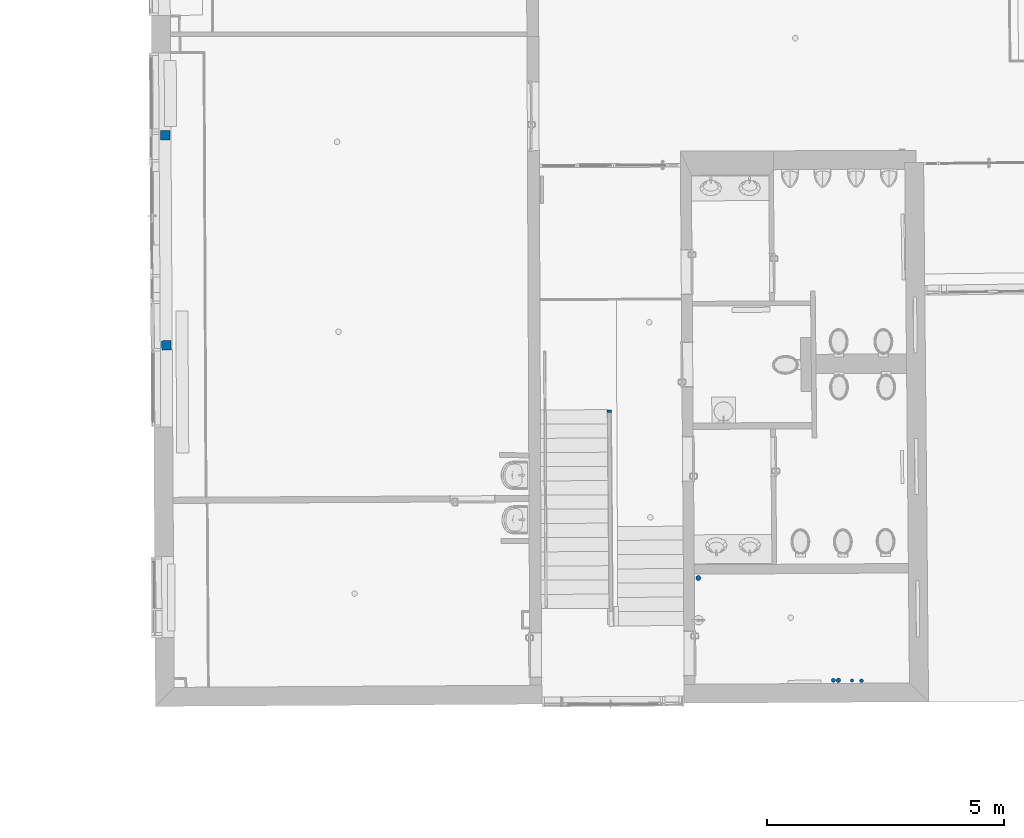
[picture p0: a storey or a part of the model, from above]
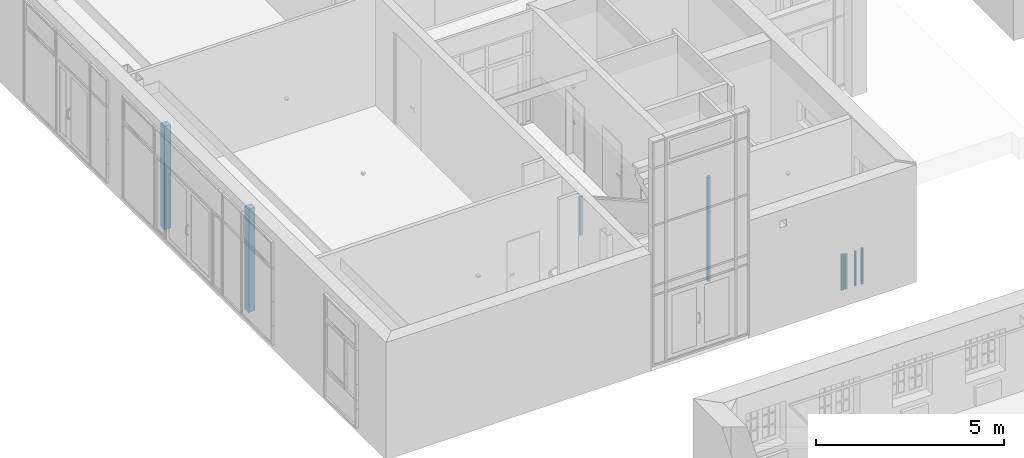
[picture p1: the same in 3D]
Properties of the parts of a building model (IFC2X3), part 1 of 4

# File
Description: ViewDefinition [CoordinationView_V2.0], Option [Elements to export: Filtered elements], Option [Partial Structure Display: Entire Model], Option [IFC Domain: Custom], Option [Structural Function: All Elements], Option [Convert Grid elements: On], Option [Convert IFC Annotations and ARCHICAD 2D elements: Off], Option [Convert 2D symbols of Doors and Windows: Off], Option [Export geometries that Participates in Collision Detection only: Off], Option [Split complex elements: Off], Option [Material Preservation: Explode where necessary], Option [Elements in Solid Element Operations: Extruded/revolved], Option [Elements with junctions: Extruded/revolved without junctions], Option [IFC Model position: Survey Point and Project Origin], Option [Curtain Wall export mode: Single Element], Option [Railing export mode: Single Element], Option [Stair export mode: Single Element], Option [Properties To Export: All properties], Option [Space containment: Off], Option [Bounding Box: Off], Option [Geometry to type objects: Off], Option [Element Properties: Off], Option [Building Material Properties: Off], Option [Element Parameters: Off], Option [Component Parameters: Off], Option [IFC Base Quantities: Off], Option [Door Window Parameters: Off], Option [IFC Space boundaries: Off], Option [ARCHICAD Zone Categories as IFC Space classification data: Off], Option [Element Classifications: On]
File name: C:\Users\BEB-Olaf\BEB\BEB - Dokumente\Mitarbeiter Cloud\1. Projekte\23-643_EichwaldeHumboldGym_Bahnhofstr_80\231116 Eichwalde, Bahnhofstr. 80\3D\231116_Eichwalde_Humbold_Gymnasium_Bahnhofstr_80.ifc
Time: 2023-11-17T09:39:34
Author: Architect
Organization: Jantzen 3D-Vermessung & 3D-Modellierung
Written by: The EXPRESS Data Manager Version 5.02.0100.09 : 26 Sep 2013
Made in: IFC file generated by GRAPHISOFT ARCHICAD 25.0.0 GER FULL Windows version (IFC add-on version: 6000 GER FULL).
Authorization: The authorising person

# IfcSite, Gelände
RefLatitude: 52, 31, 0, 0; RefLongitude: 13, 24, 0, 0; RefElevation: 0 m

# IfcBuildingStorey (6)
In: Gebäude
Name | Elevation (m)
SPITZBODEN | 13.9
DACHGESCHOSS | 10.9
2.OBERGESCHOSS | 7.9
1.OBERGESCHOSS | 3.7
ERDGESCHOSS | 0
KELLERGESCHOSS | -3

# IfcSpace: Bildung, Unterricht und Kultur
In: 1.OBERGESCHOSS
LongName: Lehrerzimmer 215; InteriorOrExteriorSpace: INTERNAL
Pset_SpaceCommon - Category: Bildung, Unterricht und Kultur
AC_Pset_RenovationAndPhasing - Renovation Status: Existing

# IfcSpace: Sonstige Nutzungen (9)
In: 1.OBERGESCHOSS
InteriorOrExteriorSpace: INTERNAL
Pset_SpaceCommon - Category: Sonstige Nutzungen
AC_Pset_RenovationAndPhasing - Renovation Status: Existing
Name | LongName
3 x  | Flur
 | Toiletten Herren 217
001 | Toiletten Herren 216
001 | Toiletten Damen 219
002 | Toiletten Herren 216
002 | Toiletten Damen 219
003 | Toiletten Damen 219

# IfcSpace: Wohnen und Aufenthalt (132)
InteriorOrExteriorSpace: INTERNAL
Pset_SpaceCommon - Category: Wohnen und Aufenthalt
AC_Pset_RenovationAndPhasing - Renovation Status: Existing
Name | In | LongName
 | 2.OBERGESCHOSS | Klassenraum Mathematik 308
 | 2.OBERGESCHOSS | 315
 | 2.OBERGESCHOSS | 301
 | 2.OBERGESCHOSS | Informatik 310
 | 2.OBERGESCHOSS | Behindertentoilette 311
 | 2.OBERGESCHOSS | Klassenraum Mathematik 306
 | 2.OBERGESCHOSS | Mathematik 304
 | 2.OBERGESCHOSS | Abstellraum 305
 | 2.OBERGESCHOSS | Klassenraum Mathematik 303
 | 2.OBERGESCHOSS | Vorbereitung/Sammlung Mathematik/Informatik 302
 | 2.OBERGESCHOSS | Informatik 309
 | 2.OBERGESCHOSS | Kammer 314
 | 2.OBERGESCHOSS | Aula 307
001 | 2.OBERGESCHOSS | Toilette Damen 313
001 | 2.OBERGESCHOSS | Flur
001 | 2.OBERGESCHOSS | Toilette Herren 312
002 | 2.OBERGESCHOSS | Toilette Herren 312
002 | 2.OBERGESCHOSS | Flur
002 | 2.OBERGESCHOSS | Toilette Damen 313
003 | 2.OBERGESCHOSS | Flur
004 | 2.OBERGESCHOSS | Flur
 | 1.OBERGESCHOSS | Beratungsraum 214
 | 1.OBERGESCHOSS | Sekretariat 205
 | 1.OBERGESCHOSS | Klassenraum 220
 | 1.OBERGESCHOSS | 213/214
 | 1.OBERGESCHOSS | Keine Bezeichnung
 | 1.OBERGESCHOSS | Klassenraum 202
 | 1.OBERGESCHOSS | Sanitätsraum 213
 | 1.OBERGESCHOSS | Stellv. Schulleiter 204
 | 1.OBERGESCHOSS | Klassenraum 201
 | 1.OBERGESCHOSS | Schulleiter 206
 | 1.OBERGESCHOSS | Klassenraum 203
 | 1.OBERGESCHOSS | Vorbereitung Bio 211
001 | 1.OBERGESCHOSS | Flur
002 | 1.OBERGESCHOSS | Flur
003 | 1.OBERGESCHOSS | Flur
Chemie | 1.OBERGESCHOSS | Klassenraum 208
Chemie | 1.OBERGESCHOSS | Vorbereitung 209
Chemie | 1.OBERGESCHOSS | Klassenraum 210
Chemie | 1.OBERGESCHOSS | Klassenraum 207
 | ERDGESCHOSS | N 2.6
 | ERDGESCHOSS | Kunst Vorbereitung N 2.2
 | ERDGESCHOSS | Klassenraum 102
 | ERDGESCHOSS | Klassenraum 105
 | ERDGESCHOSS | Klassenraum 101
 | ERDGESCHOSS | Treppenhaus
 | ERDGESCHOSS | Kunst N 2.3
 | ERDGESCHOSS | Klassenraum 104
 | ERDGESCHOSS | Geschichte N 2.4
 | ERDGESCHOSS | Flur
 | ERDGESCHOSS | Vorbereitung Physik 107
 | ERDGESCHOSS | Vorbereitungsraum Erdkunde 110
 | ERDGESCHOSS | Vorbereitungsraum Erdkunde 111
 | ERDGESCHOSS | Toiletten Herren 114
 | ERDGESCHOSS | Physik 106
 | ERDGESCHOSS | Klassenraum 117
 | ERDGESCHOSS | Toiletten Damen 115
 | ERDGESCHOSS | Kunst N 2.1
 | ERDGESCHOSS | N 2.5
 | ERDGESCHOSS | Schulsozialarbeit 109
 | ERDGESCHOSS | Physik 108
 | ERDGESCHOSS | Klassenraum 103
001 | ERDGESCHOSS | Toiletten Herren 113
001 | ERDGESCHOSS | Toiletten Damen 116
001 | ERDGESCHOSS | Vorbereitungsraum 112
001 | ERDGESCHOSS | Flur
002 | ERDGESCHOSS | Flur
002 | ERDGESCHOSS | Treppenhaus
002 | ERDGESCHOSS | Toiletten Damen 116
002 | ERDGESCHOSS | Vorbereitungsraum 112
002 | ERDGESCHOSS | Toiletten Herren 113
003 | ERDGESCHOSS | Flur
003 | ERDGESCHOSS | Toiletten Damen 116
004 | ERDGESCHOSS | Flur
005 | ERDGESCHOSS | Flur
006 | ERDGESCHOSS | Flur
 | KELLERGESCHOSS | N 1.6
2 x  | KELLERGESCHOSS | Treppenhaus
3 x  | KELLERGESCHOSS
 | KELLERGESCHOSS | Hausanschlussraum 003
 | KELLERGESCHOSS | Sammlungsraum 002
 | KELLERGESCHOSS | Kammer 022
2 x  | KELLERGESCHOSS | Flur
 | KELLERGESCHOSS | Klassenraum 004
 | KELLERGESCHOSS | Hausmeister Herr Hoppe 014
 | KELLERGESCHOSS | Sprachenvorbereitung 005
 | KELLERGESCHOSS | Heizung 016
 | KELLERGESCHOSS | N 1.3
 | KELLERGESCHOSS | Klassenraum 007
 | KELLERGESCHOSS | Buchraum 006
 | KELLERGESCHOSS | Klassenraum 009
 | KELLERGESCHOSS | Klassenraum 010
 | KELLERGESCHOSS | Klassenraum 011
 | KELLERGESCHOSS | 09
 | KELLERGESCHOSS | Klassenraum 008
 | KELLERGESCHOSS | Toilette Damen 019
 | KELLERGESCHOSS | 05
 | KELLERGESCHOSS | Bad Hausmeister 014
 | KELLERGESCHOSS | Toilette Herren 018
 | KELLERGESCHOSS | 02
 | KELLERGESCHOSS | 04
 | KELLERGESCHOSS | 03
 | KELLERGESCHOSS | 07
 | KELLERGESCHOSS | 06
 | KELLERGESCHOSS | 08
 | KELLERGESCHOSS | 01
 | KELLERGESCHOSS | Klassenraum 001
 | KELLERGESCHOSS | N 1.7
 | KELLERGESCHOSS | N 1.8
 | KELLERGESCHOSS | N 1.1
 | KELLERGESCHOSS | N 1.2
001 | KELLERGESCHOSS | 021
001 | KELLERGESCHOSS | Toilette Damen 020
001 | KELLERGESCHOSS | Toilette Herren 017
001 | KELLERGESCHOSS | N 1.5
001 | KELLERGESCHOSS | Flur
001 | KELLERGESCHOSS | Windfang
002 | KELLERGESCHOSS | Toilette Damen 020
002 | KELLERGESCHOSS | 021
3 x 002 | KELLERGESCHOSS | Flur
002 | KELLERGESCHOSS | Heizung 016
2 x 002 | KELLERGESCHOSS | N 1.5
002 | KELLERGESCHOSS | Toilette Herren 017
002 | KELLERGESCHOSS | N 1.7
003 | KELLERGESCHOSS | Toilette Damen 020

# IfcBeam: 01_ALLGEMEIN - BAUTEIL 40 x 40 (6)
Type - PredefinedType: LINTEL
Classification: 351 Deckenkonstruktionen (Classification DIN 267:2018-12); Sturz (ARCHICAD Klassifizierung); Material: 01_ALLGEMEIN - BAUTEIL
Pset_BeamCommon - LoadBearing: yes; IsExternal: no; Reference: 01_ALLGEMEIN - BAUTEIL 40 x 40
AC_Pset_RenovationAndPhasing - Renovation Status: Existing
Name | In | Slope (deg)
Unterzug-007 | ERDGESCHOSS | -0.144917
Unterzug-008 | ERDGESCHOSS | -0.259196
Unterzug-009 | ERDGESCHOSS | 29.8521
Unterzug-010 | ERDGESCHOSS | -0.082967
Unterzug-006 | KELLERGESCHOSS | -0.317002
Unterzug-007 | KELLERGESCHOSS | 29.8123

# IfcBeam: 01_ALLGEMEIN - BAUTEIL 422 x 500 (15)
Type - PredefinedType: LINTEL
Classification: 351 Deckenkonstruktionen (Classification DIN 267:2018-12); Sturz (ARCHICAD Klassifizierung); Material: 01_ALLGEMEIN - BAUTEIL
Pset_BeamCommon - LoadBearing: yes; IsExternal: no; Reference: 01_ALLGEMEIN - BAUTEIL 422 x 500
AC_Pset_RenovationAndPhasing - Renovation Status: Existing
Name | In | Slope (deg)
Unterzug-023 | SPITZBODEN | 0.172647
Unterzug-023 | DACHGESCHOSS | -5.87816
Unterzug-024 | DACHGESCHOSS | 3.50653
Unterzug-024 | DACHGESCHOSS | 2.12091
Unterzug-025 | DACHGESCHOSS | -0.357447
Unterzug-025 | DACHGESCHOSS | -0.617514
Unterzug-026 | DACHGESCHOSS | 2.24426
Unterzug-026 | DACHGESCHOSS | 2.85977
Unterzug-027 | DACHGESCHOSS | -0.105432
Unterzug-027 | DACHGESCHOSS | -0.701471
Unterzug-028 | DACHGESCHOSS | 0.353788
Unterzug-029 | DACHGESCHOSS | 0.289334
Unterzug-030 | DACHGESCHOSS | -3.50915
Unterzug-031 | DACHGESCHOSS | 1.33837
Unterzug-032 | DACHGESCHOSS | -1.38192

# IfcBeam: 01_ALLGEMEIN - BAUTEIL 500 x 500, Unterzug-022
In: SPITZBODEN
Type - PredefinedType: LINTEL
Classification: 351 Deckenkonstruktionen (Classification DIN 267:2018-12); Sturz (ARCHICAD Klassifizierung); Material: 01_ALLGEMEIN - BAUTEIL
Pset_BeamCommon - Slope: -1.53467 deg; LoadBearing: yes; IsExternal: no; Reference: 01_ALLGEMEIN - BAUTEIL 500 x 500
AC_Pset_RenovationAndPhasing - Renovation Status: Existing

# IfcBeam: 01_ALLGEMEIN - BAUTEIL 90 x 50, Unterzug-005
In: ERDGESCHOSS
Type - PredefinedType: LINTEL
Classification: 351 Deckenkonstruktionen (Classification DIN 267:2018-12); Sturz (ARCHICAD Klassifizierung); Material: 01_ALLGEMEIN - BAUTEIL
Pset_BeamCommon - Slope: 0 deg; LoadBearing: yes; IsExternal: no; Reference: 01_ALLGEMEIN - BAUTEIL 90 x 50
AC_Pset_RenovationAndPhasing - Renovation Status: Existing

# IfcBeam: 05_ALLGEMEIN - TRAGENDE BAUTEILE 100 x 100, Unterzug-027
In: SPITZBODEN
Type - PredefinedType: LINTEL
Classification: 351 Deckenkonstruktionen (Classification DIN 267:2018-12); Sturz (ARCHICAD Klassifizierung); Material: 05_ALLGEMEIN - TRAGENDE BAUTEILE
Pset_BeamCommon - Slope: 0.170074 deg; LoadBearing: yes; IsExternal: no; Reference: 05_ALLGEMEIN - TRAGENDE BAUTEILE 100 x 100
AC_Pset_RenovationAndPhasing - Renovation Status: Existing

# IfcBeam: 05_ALLGEMEIN - TRAGENDE BAUTEILE 100 x 120 (11)
In: ERDGESCHOSS
Type - PredefinedType: LINTEL
Classification: 351 Deckenkonstruktionen (Classification DIN 267:2018-12); Sturz (ARCHICAD Klassifizierung); Material: 05_ALLGEMEIN - TRAGENDE BAUTEILE
Pset_BeamCommon - LoadBearing: yes; IsExternal: no; Reference: 05_ALLGEMEIN - TRAGENDE BAUTEILE 100 x 120
AC_Pset_RenovationAndPhasing - Renovation Status: Existing
Name | Slope (deg)
Unterzug-063 | -0.0255391
Unterzug-063 | -0.409344
5 x Unterzug-064 | 0.19738
Unterzug-065 | 0.271111
Unterzug-066 | -0.169375
Unterzug-067 | 0.141631
Unterzug-068 | -0.118367

# IfcBeam: 05_ALLGEMEIN - TRAGENDE BAUTEILE 102 x 390, Unterzug-020
In: ERDGESCHOSS
Type - PredefinedType: LINTEL
Classification: 351 Deckenkonstruktionen (Classification DIN 267:2018-12); Sturz (ARCHICAD Klassifizierung); Material: 05_ALLGEMEIN - TRAGENDE BAUTEILE
Pset_BeamCommon - Slope: -26.8116 deg; LoadBearing: yes; IsExternal: no; Reference: 05_ALLGEMEIN - TRAGENDE BAUTEILE 102 x 390
AC_Pset_RenovationAndPhasing - Renovation Status: Existing

# IfcBeam: 05_ALLGEMEIN - TRAGENDE BAUTEILE 115 x 120 (2)
In: KELLERGESCHOSS
Type - PredefinedType: LINTEL
Classification: 351 Deckenkonstruktionen (Classification DIN 267:2018-12); Sturz (ARCHICAD Klassifizierung); Material: 05_ALLGEMEIN - TRAGENDE BAUTEILE
Pset_BeamCommon - LoadBearing: yes; IsExternal: no; Reference: 05_ALLGEMEIN - TRAGENDE BAUTEILE 115 x 120
AC_Pset_RenovationAndPhasing - Renovation Status: Existing
Name | Slope (deg)
Unterzug-026 | -0.242095
Unterzug-027 | 0.171309

# IfcBeam: 05_ALLGEMEIN - TRAGENDE BAUTEILE 120 x 140 (8)
In: 2.OBERGESCHOSS
Type - PredefinedType: LINTEL
Classification: 351 Deckenkonstruktionen (Classification DIN 267:2018-12); Sturz (ARCHICAD Klassifizierung); Material: 05_ALLGEMEIN - TRAGENDE BAUTEILE
Pset_BeamCommon - LoadBearing: yes; IsExternal: no; Reference: 05_ALLGEMEIN - TRAGENDE BAUTEILE 120 x 140
AC_Pset_RenovationAndPhasing - Renovation Status: Existing
Name | Slope (deg)
Unterzug-090 | -44.3282
Unterzug-091 | -44.0647
Unterzug-091 | 44.0561
Unterzug-092 | -44.0622
Unterzug-093 | -45.7999
Unterzug-093 | 45.2487
Unterzug-094 | 44.4827
Unterzug-094 | -43.8498

# IfcBeam: 05_ALLGEMEIN - TRAGENDE BAUTEILE 122 x 160 (2)
Type - PredefinedType: LINTEL
Classification: 351 Deckenkonstruktionen (Classification DIN 267:2018-12); Sturz (ARCHICAD Klassifizierung); Material: 05_ALLGEMEIN - TRAGENDE BAUTEILE
Pset_BeamCommon - LoadBearing: yes; IsExternal: no; Reference: 05_ALLGEMEIN - TRAGENDE BAUTEILE 122 x 160
AC_Pset_RenovationAndPhasing - Renovation Status: Existing
Name | In | Slope (deg)
Unterzug-037 | SPITZBODEN | -0.151633
Unterzug-037 | DACHGESCHOSS | -0.0277064

# IfcBeam: 05_ALLGEMEIN - TRAGENDE BAUTEILE 130 x 160 (6)
In: DACHGESCHOSS
Type - PredefinedType: LINTEL
Classification: 351 Deckenkonstruktionen (Classification DIN 267:2018-12); Sturz (ARCHICAD Klassifizierung); Material: 05_ALLGEMEIN - TRAGENDE BAUTEILE
Pset_BeamCommon - LoadBearing: yes; IsExternal: no; Reference: 05_ALLGEMEIN - TRAGENDE BAUTEILE 130 x 160
AC_Pset_RenovationAndPhasing - Renovation Status: Existing
Name | Slope (deg)
Unterzug-064 | 0.103733
Unterzug-065 | 0.328985
Unterzug-066 | 1.14341
Unterzug-071 | 0.0835682
Unterzug-072 | 0.511564
Unterzug-073 | 1.18713

# IfcBeam: 05_ALLGEMEIN - TRAGENDE BAUTEILE 130 x 170 (41)
Type - PredefinedType: LINTEL
Classification: 351 Deckenkonstruktionen (Classification DIN 267:2018-12); Sturz (ARCHICAD Klassifizierung); Material: 05_ALLGEMEIN - TRAGENDE BAUTEILE
Pset_BeamCommon - LoadBearing: yes; IsExternal: no; Reference: 05_ALLGEMEIN - TRAGENDE BAUTEILE 130 x 170
AC_Pset_RenovationAndPhasing - Renovation Status: Existing
Name | In | Slope (deg)
Unterzug-056 | SPITZBODEN | 80.6286
Unterzug-057 | SPITZBODEN | -80.746
Unterzug-061 | SPITZBODEN | -78.8242
Unterzug-079 | SPITZBODEN | 80.5319
Unterzug-080 | SPITZBODEN | 0
Unterzug-081 | SPITZBODEN | 0
Unterzug-082 | SPITZBODEN | 0
Unterzug-083 | SPITZBODEN | 0
Unterzug-084 | SPITZBODEN | 24.3867
Unterzug-085 | SPITZBODEN | -23.3479
Unterzug-050 | DACHGESCHOSS | 50.7288
Unterzug-051 | DACHGESCHOSS | -50.4321
Unterzug-052 | DACHGESCHOSS | -50.3705
Unterzug-053 | DACHGESCHOSS | -49.253
Unterzug-054 | DACHGESCHOSS | 0.028561
Unterzug-055 | DACHGESCHOSS | 41.2954
Unterzug-057 | DACHGESCHOSS | -49.5741
Unterzug-058 | DACHGESCHOSS | -51.0679
Unterzug-059 | DACHGESCHOSS | -50.3902
Unterzug-060 | DACHGESCHOSS | 50.2729
Unterzug-062 | DACHGESCHOSS | -50.8759
Unterzug-063 | DACHGESCHOSS | -49.8978
Unterzug-064 | DACHGESCHOSS | -50.1063
Unterzug-065 | DACHGESCHOSS | -40.8446
Unterzug-066 | DACHGESCHOSS | 50.4026
Unterzug-068 | DACHGESCHOSS | 41.0425
Unterzug-069 | DACHGESCHOSS | 39.3935
Unterzug-070 | DACHGESCHOSS | 53.9665
2 x Unterzug-071 | DACHGESCHOSS | -40.8246
Unterzug-072 | DACHGESCHOSS | -51.0445
Unterzug-073 | DACHGESCHOSS | 50.9107
Unterzug-074 | DACHGESCHOSS | 42.2773
Unterzug-075 | DACHGESCHOSS | -44.0211
Unterzug-076 | DACHGESCHOSS | 0.0615184
Unterzug-077 | DACHGESCHOSS | 0.58419
Unterzug-078 | DACHGESCHOSS | 0.0397564
Unterzug-083 | DACHGESCHOSS | 0.513884
Unterzug-084 | DACHGESCHOSS | 44.6501
Unterzug-090 | DACHGESCHOSS | 45.4397
Unterzug-091 | DACHGESCHOSS | 44.0047

# IfcBeam: 05_ALLGEMEIN - TRAGENDE BAUTEILE 145 x 69, Unterzug-021
In: KELLERGESCHOSS
Type - PredefinedType: LINTEL
Classification: 351 Deckenkonstruktionen (Classification DIN 267:2018-12); Sturz (ARCHICAD Klassifizierung); Material: 05_ALLGEMEIN - TRAGENDE BAUTEILE
Pset_BeamCommon - Slope: 26.9878 deg; LoadBearing: yes; IsExternal: no; Reference: 05_ALLGEMEIN - TRAGENDE BAUTEILE 145 x 69
AC_Pset_RenovationAndPhasing - Renovation Status: Existing

# IfcBeam: 05_ALLGEMEIN - TRAGENDE BAUTEILE 145 x 74, Unterzug-021
In: ERDGESCHOSS
Type - PredefinedType: LINTEL
Classification: 351 Deckenkonstruktionen (Classification DIN 267:2018-12); Sturz (ARCHICAD Klassifizierung); Material: 05_ALLGEMEIN - TRAGENDE BAUTEILE
Pset_BeamCommon - Slope: 26.9878 deg; LoadBearing: yes; IsExternal: no; Reference: 05_ALLGEMEIN - TRAGENDE BAUTEILE 145 x 74
AC_Pset_RenovationAndPhasing - Renovation Status: Existing

# IfcBeam: 05_ALLGEMEIN - TRAGENDE BAUTEILE 145 x 80 (6)
Type - PredefinedType: LINTEL
Classification: 351 Deckenkonstruktionen (Classification DIN 267:2018-12); Sturz (ARCHICAD Klassifizierung); Material: 05_ALLGEMEIN - TRAGENDE BAUTEILE
Pset_BeamCommon - LoadBearing: yes; IsExternal: no; Reference: 05_ALLGEMEIN - TRAGENDE BAUTEILE 145 x 80
AC_Pset_RenovationAndPhasing - Renovation Status: Existing
Name | In | Slope (deg)
Unterzug-021 | 1.OBERGESCHOSS | -0.449914
Unterzug-022 | 1.OBERGESCHOSS | 26.5984
Unterzug-023 | 1.OBERGESCHOSS | 0
Unterzug-024 | 1.OBERGESCHOSS | 26.8204
Unterzug-020 | ERDGESCHOSS | 0
Unterzug-020 | ERDGESCHOSS | -26.5975

# IfcBeam: 05_ALLGEMEIN - TRAGENDE BAUTEILE 145 x 89, Unterzug-022
In: KELLERGESCHOSS
Type - PredefinedType: LINTEL
Classification: 351 Deckenkonstruktionen (Classification DIN 267:2018-12); Sturz (ARCHICAD Klassifizierung); Material: 05_ALLGEMEIN - TRAGENDE BAUTEILE
Pset_BeamCommon - Slope: -0.416528 deg; LoadBearing: yes; IsExternal: no; Reference: 05_ALLGEMEIN - TRAGENDE BAUTEILE 145 x 89
AC_Pset_RenovationAndPhasing - Renovation Status: Existing

# IfcBeam: 05_ALLGEMEIN - TRAGENDE BAUTEILE 150 x 105 (2)
In: KELLERGESCHOSS
Type - PredefinedType: LINTEL
Classification: 351 Deckenkonstruktionen (Classification DIN 267:2018-12); Sturz (ARCHICAD Klassifizierung); Material: 05_ALLGEMEIN - TRAGENDE BAUTEILE
Pset_BeamCommon - LoadBearing: yes; IsExternal: no; Reference: 05_ALLGEMEIN - TRAGENDE BAUTEILE 150 x 105
AC_Pset_RenovationAndPhasing - Renovation Status: Existing
Name | Slope (deg)
Unterzug-024 | -0.175032
Unterzug-025 | 0.579091

# IfcBeam: 05_ALLGEMEIN - TRAGENDE BAUTEILE 153 x 89 (2)
Type - PredefinedType: LINTEL
Classification: 351 Deckenkonstruktionen (Classification DIN 267:2018-12); Sturz (ARCHICAD Klassifizierung); Material: 05_ALLGEMEIN - TRAGENDE BAUTEILE
Pset_BeamCommon - LoadBearing: yes; IsExternal: no; Reference: 05_ALLGEMEIN - TRAGENDE BAUTEILE 153 x 89
AC_Pset_RenovationAndPhasing - Renovation Status: Existing
Name | In | Slope (deg)
Unterzug-024 | 2.OBERGESCHOSS | -0.317178
Unterzug-023 | KELLERGESCHOSS | -0.0473949

# IfcBeam: 05_ALLGEMEIN - TRAGENDE BAUTEILE 154 x 90, Unterzug-021
In: ERDGESCHOSS
Type - PredefinedType: LINTEL
Classification: 351 Deckenkonstruktionen (Classification DIN 267:2018-12); Sturz (ARCHICAD Klassifizierung); Material: 05_ALLGEMEIN - TRAGENDE BAUTEILE
Pset_BeamCommon - Slope: 0 deg; LoadBearing: yes; IsExternal: no; Reference: 05_ALLGEMEIN - TRAGENDE BAUTEILE 154 x 90
AC_Pset_RenovationAndPhasing - Renovation Status: Existing

# IfcBeam: 05_ALLGEMEIN - TRAGENDE BAUTEILE 160 x 168, Unterzug-027
In: SPITZBODEN
Type - PredefinedType: LINTEL
Classification: 351 Deckenkonstruktionen (Classification DIN 267:2018-12); Sturz (ARCHICAD Klassifizierung); Material: 05_ALLGEMEIN - TRAGENDE BAUTEILE
Pset_BeamCommon - Slope: 0.123751 deg; LoadBearing: yes; IsExternal: no; Reference: 05_ALLGEMEIN - TRAGENDE BAUTEILE 160 x 168
AC_Pset_RenovationAndPhasing - Renovation Status: Existing

# IfcBeam: 05_ALLGEMEIN - TRAGENDE BAUTEILE 160 x 90, Unterzug-026
In: SPITZBODEN
Type - PredefinedType: LINTEL
Classification: 351 Deckenkonstruktionen (Classification DIN 267:2018-12); Sturz (ARCHICAD Klassifizierung); Material: 05_ALLGEMEIN - TRAGENDE BAUTEILE
Pset_BeamCommon - Slope: 0.00334619 deg; LoadBearing: yes; IsExternal: no; Reference: 05_ALLGEMEIN - TRAGENDE BAUTEILE 160 x 90
AC_Pset_RenovationAndPhasing - Renovation Status: Existing

# IfcBeam: 05_ALLGEMEIN - TRAGENDE BAUTEILE 170 x 157 (2)
In: 1.OBERGESCHOSS
Type - PredefinedType: LINTEL
Classification: 351 Deckenkonstruktionen (Classification DIN 267:2018-12); Sturz (ARCHICAD Klassifizierung); Material: 05_ALLGEMEIN - TRAGENDE BAUTEILE
Pset_BeamCommon - LoadBearing: yes; IsExternal: no; Reference: 05_ALLGEMEIN - TRAGENDE BAUTEILE 170 x 157
AC_Pset_RenovationAndPhasing - Renovation Status: Existing
Name | Slope (deg)
Unterzug-020 | -26.5794
Unterzug-020 | 26.8213

# IfcBeam: 05_ALLGEMEIN - TRAGENDE BAUTEILE 170 x 390 (2)
In: ERDGESCHOSS
Type - PredefinedType: LINTEL
Classification: 351 Deckenkonstruktionen (Classification DIN 267:2018-12); Sturz (ARCHICAD Klassifizierung); Material: 05_ALLGEMEIN - TRAGENDE BAUTEILE
Pset_BeamCommon - LoadBearing: yes; IsExternal: no; Reference: 05_ALLGEMEIN - TRAGENDE BAUTEILE 170 x 390
AC_Pset_RenovationAndPhasing - Renovation Status: Existing
Name | Slope (deg)
Unterzug-020 | 26.5158
Unterzug-020 | -26.7289

# IfcBeam: 05_ALLGEMEIN - TRAGENDE BAUTEILE 186 x 160, Unterzug-030
In: DACHGESCHOSS
Type - PredefinedType: LINTEL
Classification: 351 Deckenkonstruktionen (Classification DIN 267:2018-12); Sturz (ARCHICAD Klassifizierung); Material: 05_ALLGEMEIN - TRAGENDE BAUTEILE
Pset_BeamCommon - Slope: 0 deg; LoadBearing: yes; IsExternal: no; Reference: 05_ALLGEMEIN - TRAGENDE BAUTEILE 186 x 160
AC_Pset_RenovationAndPhasing - Renovation Status: Existing

# IfcBeam: 05_ALLGEMEIN - TRAGENDE BAUTEILE 190 x 190, Unterzug-090
In: 2.OBERGESCHOSS
Type - PredefinedType: LINTEL
Classification: 351 Deckenkonstruktionen (Classification DIN 267:2018-12); Sturz (ARCHICAD Klassifizierung); Material: 05_ALLGEMEIN - TRAGENDE BAUTEILE
Pset_BeamCommon - Slope: 44.6414 deg; LoadBearing: yes; IsExternal: no; Reference: 05_ALLGEMEIN - TRAGENDE BAUTEILE 190 x 190
AC_Pset_RenovationAndPhasing - Renovation Status: Existing

# IfcBeam: 05_ALLGEMEIN - TRAGENDE BAUTEILE 190 x 275, Unterzug-089
In: 2.OBERGESCHOSS
Type - PredefinedType: LINTEL
Classification: 351 Deckenkonstruktionen (Classification DIN 267:2018-12); Sturz (ARCHICAD Klassifizierung); Material: 05_ALLGEMEIN - TRAGENDE BAUTEILE
Pset_BeamCommon - Slope: 40.7529 deg; LoadBearing: yes; IsExternal: no; Reference: 05_ALLGEMEIN - TRAGENDE BAUTEILE 190 x 275
AC_Pset_RenovationAndPhasing - Renovation Status: Existing

# IfcBeam: 05_ALLGEMEIN - TRAGENDE BAUTEILE 241 x 232, Unterzug-022
In: 1.OBERGESCHOSS
Type - PredefinedType: LINTEL
Classification: 351 Deckenkonstruktionen (Classification DIN 267:2018-12); Sturz (ARCHICAD Klassifizierung); Material: 05_ALLGEMEIN - TRAGENDE BAUTEILE
Pset_BeamCommon - Slope: 0 deg; LoadBearing: yes; IsExternal: no; Reference: 05_ALLGEMEIN - TRAGENDE BAUTEILE 241 x 232
AC_Pset_RenovationAndPhasing - Renovation Status: Existing

# IfcBeam: 05_ALLGEMEIN - TRAGENDE BAUTEILE 241 x 300, Unterzug-022
In: ERDGESCHOSS
Type - PredefinedType: LINTEL
Classification: 351 Deckenkonstruktionen (Classification DIN 267:2018-12); Sturz (ARCHICAD Klassifizierung); Material: 05_ALLGEMEIN - TRAGENDE BAUTEILE
Pset_BeamCommon - Slope: 0 deg; LoadBearing: yes; IsExternal: no; Reference: 05_ALLGEMEIN - TRAGENDE BAUTEILE 241 x 300
AC_Pset_RenovationAndPhasing - Renovation Status: Existing

# IfcBeam: 05_ALLGEMEIN - TRAGENDE BAUTEILE 241 x 310, Unterzug-023
In: KELLERGESCHOSS
Type - PredefinedType: LINTEL
Classification: 351 Deckenkonstruktionen (Classification DIN 267:2018-12); Sturz (ARCHICAD Klassifizierung); Material: 05_ALLGEMEIN - TRAGENDE BAUTEILE
Pset_BeamCommon - Slope: 0 deg; LoadBearing: yes; IsExternal: no; Reference: 05_ALLGEMEIN - TRAGENDE BAUTEILE 241 x 310
AC_Pset_RenovationAndPhasing - Renovation Status: Existing

# IfcBeam: 05_ALLGEMEIN - TRAGENDE BAUTEILE 245 x 298, Unterzug-021
In: KELLERGESCHOSS
Type - PredefinedType: LINTEL
Classification: 351 Deckenkonstruktionen (Classification DIN 267:2018-12); Sturz (ARCHICAD Klassifizierung); Material: 05_ALLGEMEIN - TRAGENDE BAUTEILE
Pset_BeamCommon - Slope: 0 deg; LoadBearing: yes; IsExternal: no; Reference: 05_ALLGEMEIN - TRAGENDE BAUTEILE 245 x 298
AC_Pset_RenovationAndPhasing - Renovation Status: Existing

# IfcBeam: 05_ALLGEMEIN - TRAGENDE BAUTEILE 270 x 190, Unterzug-089
In: 2.OBERGESCHOSS
Type - PredefinedType: LINTEL
Classification: 351 Deckenkonstruktionen (Classification DIN 267:2018-12); Sturz (ARCHICAD Klassifizierung); Material: 05_ALLGEMEIN - TRAGENDE BAUTEILE
Pset_BeamCommon - Slope: -43.8101 deg; LoadBearing: yes; IsExternal: no; Reference: 05_ALLGEMEIN - TRAGENDE BAUTEILE 270 x 190
AC_Pset_RenovationAndPhasing - Renovation Status: Existing

# IfcBeam: 05_ALLGEMEIN - TRAGENDE BAUTEILE 270 x 367, Unterzug-091
In: 2.OBERGESCHOSS
Type - PredefinedType: LINTEL
Classification: 351 Deckenkonstruktionen (Classification DIN 267:2018-12); Sturz (ARCHICAD Klassifizierung); Material: 05_ALLGEMEIN - TRAGENDE BAUTEILE
Pset_BeamCommon - Slope: 43.7801 deg; LoadBearing: yes; IsExternal: no; Reference: 05_ALLGEMEIN - TRAGENDE BAUTEILE 270 x 367
AC_Pset_RenovationAndPhasing - Renovation Status: Existing

# IfcBeam: 05_ALLGEMEIN - TRAGENDE BAUTEILE 270 x 371, Unterzug-090
In: 2.OBERGESCHOSS
Type - PredefinedType: LINTEL
Classification: 351 Deckenkonstruktionen (Classification DIN 267:2018-12); Sturz (ARCHICAD Klassifizierung); Material: 05_ALLGEMEIN - TRAGENDE BAUTEILE
Pset_BeamCommon - Slope: -43.6873 deg; LoadBearing: yes; IsExternal: no; Reference: 05_ALLGEMEIN - TRAGENDE BAUTEILE 270 x 371
AC_Pset_RenovationAndPhasing - Renovation Status: Existing

# IfcBeam: 05_ALLGEMEIN - TRAGENDE BAUTEILE 270 x 494, Unterzug-092
In: 2.OBERGESCHOSS
Type - PredefinedType: LINTEL
Classification: 351 Deckenkonstruktionen (Classification DIN 267:2018-12); Sturz (ARCHICAD Klassifizierung); Material: 05_ALLGEMEIN - TRAGENDE BAUTEILE
Pset_BeamCommon - Slope: 41.3567 deg; LoadBearing: yes; IsExternal: no; Reference: 05_ALLGEMEIN - TRAGENDE BAUTEILE 270 x 494
AC_Pset_RenovationAndPhasing - Renovation Status: Existing

# IfcBeam: 05_ALLGEMEIN - TRAGENDE BAUTEILE 270 x 502, Unterzug-089
In: 2.OBERGESCHOSS
Type - PredefinedType: LINTEL
Classification: 351 Deckenkonstruktionen (Classification DIN 267:2018-12); Sturz (ARCHICAD Klassifizierung); Material: 05_ALLGEMEIN - TRAGENDE BAUTEILE
Pset_BeamCommon - Slope: -42.8155 deg; LoadBearing: yes; IsExternal: no; Reference: 05_ALLGEMEIN - TRAGENDE BAUTEILE 270 x 502
AC_Pset_RenovationAndPhasing - Renovation Status: Existing

# IfcBeam: 05_ALLGEMEIN - TRAGENDE BAUTEILE 274 x 411, Unterzug-089
In: 2.OBERGESCHOSS
Type - PredefinedType: LINTEL
Classification: 351 Deckenkonstruktionen (Classification DIN 267:2018-12); Sturz (ARCHICAD Klassifizierung); Material: 05_ALLGEMEIN - TRAGENDE BAUTEILE
Pset_BeamCommon - Slope: 43.4225 deg; LoadBearing: yes; IsExternal: no; Reference: 05_ALLGEMEIN - TRAGENDE BAUTEILE 274 x 411
AC_Pset_RenovationAndPhasing - Renovation Status: Existing

# IfcBeam: 05_ALLGEMEIN - TRAGENDE BAUTEILE 280 x 679, Unterzug-089
In: 2.OBERGESCHOSS
Type - PredefinedType: LINTEL
Classification: 351 Deckenkonstruktionen (Classification DIN 267:2018-12); Sturz (ARCHICAD Klassifizierung); Material: 05_ALLGEMEIN - TRAGENDE BAUTEILE
Pset_BeamCommon - Slope: 45.1469 deg; LoadBearing: yes; IsExternal: no; Reference: 05_ALLGEMEIN - TRAGENDE BAUTEILE 280 x 679
AC_Pset_RenovationAndPhasing - Renovation Status: Existing

# IfcBeam: 05_ALLGEMEIN - TRAGENDE BAUTEILE 280 x 711, Unterzug-090
In: 2.OBERGESCHOSS
Type - PredefinedType: LINTEL
Classification: 351 Deckenkonstruktionen (Classification DIN 267:2018-12); Sturz (ARCHICAD Klassifizierung); Material: 05_ALLGEMEIN - TRAGENDE BAUTEILE
Pset_BeamCommon - Slope: 45.39 deg; LoadBearing: yes; IsExternal: no; Reference: 05_ALLGEMEIN - TRAGENDE BAUTEILE 280 x 711
AC_Pset_RenovationAndPhasing - Renovation Status: Existing

# IfcBeam: 05_ALLGEMEIN - TRAGENDE BAUTEILE 296 x 863 (4)
In: 2.OBERGESCHOSS
Type - PredefinedType: LINTEL
Classification: 351 Deckenkonstruktionen (Classification DIN 267:2018-12); Sturz (ARCHICAD Klassifizierung); Material: 05_ALLGEMEIN - TRAGENDE BAUTEILE
Pset_BeamCommon - LoadBearing: yes; IsExternal: no; Reference: 05_ALLGEMEIN - TRAGENDE BAUTEILE 296 x 863
AC_Pset_RenovationAndPhasing - Renovation Status: Existing
Name | Slope (deg)
Unterzug-010 | 41.03
Unterzug-010 | 45.72
Unterzug-010 | 45.47
Unterzug-010 | 42.92

# IfcBeam: 05_ALLGEMEIN - TRAGENDE BAUTEILE 30 x 78 (437)
In: DACHGESCHOSS
Type - PredefinedType: LINTEL
Classification: 351 Deckenkonstruktionen (Classification DIN 267:2018-12); Sturz (ARCHICAD Klassifizierung); Material: 05_ALLGEMEIN - TRAGENDE BAUTEILE
Pset_BeamCommon - LoadBearing: yes; IsExternal: no; Reference: 05_ALLGEMEIN - TRAGENDE BAUTEILE 30 x 78
AC_Pset_RenovationAndPhasing - Renovation Status: Existing
Name | Slope (deg)
50 x Unterzug-007 | -56.2002
43 x Unterzug-008 | 41.1565
50 x Unterzug-008 | -59.5113
43 x Unterzug-009 | 43.0346
50 x Unterzug-009 | -56.9957
50 x Unterzug-010 | -14.2852
50 x Unterzug-010 | 44.6007
50 x Unterzug-011 | 33.5419
Unterzug-011 | 15.0115
50 x Unterzug-012 | 25.0018

# IfcBeam: 05_ALLGEMEIN - TRAGENDE BAUTEILE 30 x 95 (201)
In: DACHGESCHOSS
Type - PredefinedType: LINTEL
Classification: 351 Deckenkonstruktionen (Classification DIN 267:2018-12); Sturz (ARCHICAD Klassifizierung); Material: 05_ALLGEMEIN - TRAGENDE BAUTEILE
Pset_BeamCommon - LoadBearing: yes; IsExternal: no; Reference: 05_ALLGEMEIN - TRAGENDE BAUTEILE 30 x 95
AC_Pset_RenovationAndPhasing - Renovation Status: Existing
Name | Slope (deg)
25 x Unterzug-005 | 14.2602
50 x Unterzug-007 | -14.2939
26 x Unterzug-007 | -14.22
50 x Unterzug-008 | -0.55142
25 x Unterzug-008 | 14.26
25 x Unterzug-008 | 14.1414

# IfcBeam: 05_ALLGEMEIN - TRAGENDE BAUTEILE 320 x 320, Unterzug-099
In: 2.OBERGESCHOSS
Type - PredefinedType: LINTEL
Classification: 351 Deckenkonstruktionen (Classification DIN 267:2018-12); Sturz (ARCHICAD Klassifizierung); Material: 05_ALLGEMEIN - TRAGENDE BAUTEILE
Pset_BeamCommon - Slope: -1.2162 deg; LoadBearing: yes; IsExternal: no; Reference: 05_ALLGEMEIN - TRAGENDE BAUTEILE 320 x 320
AC_Pset_RenovationAndPhasing - Renovation Status: Existing

# IfcBeam: 05_ALLGEMEIN - TRAGENDE BAUTEILE 35 x 95 (50)
In: DACHGESCHOSS
Type - PredefinedType: LINTEL
Classification: 351 Deckenkonstruktionen (Classification DIN 267:2018-12); Sturz (ARCHICAD Klassifizierung); Material: 05_ALLGEMEIN - TRAGENDE BAUTEILE
Pset_BeamCommon - Slope: -0.312147 deg; LoadBearing: yes; IsExternal: no; Reference: 05_ALLGEMEIN - TRAGENDE BAUTEILE 35 x 95
AC_Pset_RenovationAndPhasing - Renovation Status: Existing

# IfcBeam: 05_ALLGEMEIN - TRAGENDE BAUTEILE 359 x 190, Unterzug-089
In: 2.OBERGESCHOSS
Type - PredefinedType: LINTEL
Classification: 351 Deckenkonstruktionen (Classification DIN 267:2018-12); Sturz (ARCHICAD Klassifizierung); Material: 05_ALLGEMEIN - TRAGENDE BAUTEILE
Pset_BeamCommon - Slope: 0.285634 deg; LoadBearing: yes; IsExternal: no; Reference: 05_ALLGEMEIN - TRAGENDE BAUTEILE 359 x 190
AC_Pset_RenovationAndPhasing - Renovation Status: Existing

# IfcBeam: 05_ALLGEMEIN - TRAGENDE BAUTEILE 422 x 500, Unterzug-023
In: DACHGESCHOSS
Type - PredefinedType: LINTEL
Classification: 351 Deckenkonstruktionen (Classification DIN 267:2018-12); Sturz (ARCHICAD Klassifizierung); Material: 05_ALLGEMEIN - TRAGENDE BAUTEILE
Pset_BeamCommon - Slope: -1.28797 deg; LoadBearing: yes; IsExternal: no; Reference: 05_ALLGEMEIN - TRAGENDE BAUTEILE 422 x 500
AC_Pset_RenovationAndPhasing - Renovation Status: Existing

# IfcBeam: 05_ALLGEMEIN - TRAGENDE BAUTEILE 436 x 80, Unterzug-023
In: KELLERGESCHOSS
Type - PredefinedType: LINTEL
Classification: 351 Deckenkonstruktionen (Classification DIN 267:2018-12); Sturz (ARCHICAD Klassifizierung); Material: 05_ALLGEMEIN - TRAGENDE BAUTEILE
Pset_BeamCommon - Slope: 25.6535 deg; LoadBearing: yes; IsExternal: no; Reference: 05_ALLGEMEIN - TRAGENDE BAUTEILE 436 x 80
AC_Pset_RenovationAndPhasing - Renovation Status: Existing

# IfcBeam: 05_ALLGEMEIN - TRAGENDE BAUTEILE 50 x 190 (3)
Type - PredefinedType: LINTEL
Classification: 351 Deckenkonstruktionen (Classification DIN 267:2018-12); Sturz (ARCHICAD Klassifizierung); Material: 05_ALLGEMEIN - TRAGENDE BAUTEILE
Pset_BeamCommon - LoadBearing: yes; IsExternal: no; Reference: 05_ALLGEMEIN - TRAGENDE BAUTEILE 50 x 190
AC_Pset_RenovationAndPhasing - Renovation Status: Existing
Name | In | Slope (deg)
Unterzug-026 | SPITZBODEN | 0.0386013
Unterzug-027 | SPITZBODEN | 0.0874415
Unterzug-026 | DACHGESCHOSS | -0.411591

# IfcBeam: 05_ALLGEMEIN - TRAGENDE BAUTEILE 55 x 226 (50)
In: DACHGESCHOSS
Type - PredefinedType: LINTEL
Classification: 351 Deckenkonstruktionen (Classification DIN 267:2018-12); Sturz (ARCHICAD Klassifizierung); Material: 05_ALLGEMEIN - TRAGENDE BAUTEILE
Pset_BeamCommon - Slope: 0 deg; LoadBearing: yes; IsExternal: no; Reference: 05_ALLGEMEIN - TRAGENDE BAUTEILE 55 x 226
AC_Pset_RenovationAndPhasing - Renovation Status: Existing

# IfcBeam: 05_ALLGEMEIN - TRAGENDE BAUTEILE 55 x 250 (50)
In: DACHGESCHOSS
Type - PredefinedType: LINTEL
Classification: 351 Deckenkonstruktionen (Classification DIN 267:2018-12); Sturz (ARCHICAD Klassifizierung); Material: 05_ALLGEMEIN - TRAGENDE BAUTEILE
Pset_BeamCommon - Slope: 0 deg; LoadBearing: yes; IsExternal: no; Reference: 05_ALLGEMEIN - TRAGENDE BAUTEILE 55 x 250
AC_Pset_RenovationAndPhasing - Renovation Status: Existing

# IfcBeam: 05_ALLGEMEIN - TRAGENDE BAUTEILE 55 x 364 (54)
In: DACHGESCHOSS
Type - PredefinedType: LINTEL
Classification: 351 Deckenkonstruktionen (Classification DIN 267:2018-12); Sturz (ARCHICAD Klassifizierung); Material: 05_ALLGEMEIN - TRAGENDE BAUTEILE
Pset_BeamCommon - Slope: -1.42677 deg; LoadBearing: yes; IsExternal: no; Reference: 05_ALLGEMEIN - TRAGENDE BAUTEILE 55 x 364
AC_Pset_RenovationAndPhasing - Renovation Status: Existing

# IfcBeam: 05_ALLGEMEIN - TRAGENDE BAUTEILE 566 x 343, Unterzug-021
In: ERDGESCHOSS
Type - PredefinedType: LINTEL
Classification: 351 Deckenkonstruktionen (Classification DIN 267:2018-12); Sturz (ARCHICAD Klassifizierung); Material: 05_ALLGEMEIN - TRAGENDE BAUTEILE
Pset_BeamCommon - Slope: 0 deg; LoadBearing: yes; IsExternal: no; Reference: 05_ALLGEMEIN - TRAGENDE BAUTEILE 566 x 343
AC_Pset_RenovationAndPhasing - Renovation Status: Existing

# IfcBeam: 05_ALLGEMEIN - TRAGENDE BAUTEILE 70 x 160 (22)
Type - PredefinedType: LINTEL
Classification: 351 Deckenkonstruktionen (Classification DIN 267:2018-12); Sturz (ARCHICAD Klassifizierung); Material: 05_ALLGEMEIN - TRAGENDE BAUTEILE
Pset_BeamCommon - LoadBearing: yes; IsExternal: no; Reference: 05_ALLGEMEIN - TRAGENDE BAUTEILE 70 x 160
AC_Pset_RenovationAndPhasing - Renovation Status: Existing
Name | In | Slope (deg)
Unterzug-030 | SPITZBODEN | -51.9765
Unterzug-031 | SPITZBODEN | -51.3314
Unterzug-032 | SPITZBODEN | -51.164
Unterzug-033 | SPITZBODEN | 51.2457
2 x Unterzug-029 | DACHGESCHOSS | -52.1774
12 x Unterzug-030 | DACHGESCHOSS | 52.1177
Unterzug-030 | DACHGESCHOSS | 51.2152
Unterzug-031 | DACHGESCHOSS | -52.0279
Unterzug-032 | DACHGESCHOSS | -51.5675
Unterzug-033 | DACHGESCHOSS | 51.7717

# IfcBeam: 05_ALLGEMEIN - TRAGENDE BAUTEILE 70 x 170 (8)
Type - PredefinedType: LINTEL
Classification: 351 Deckenkonstruktionen (Classification DIN 267:2018-12); Sturz (ARCHICAD Klassifizierung); Material: 05_ALLGEMEIN - TRAGENDE BAUTEILE
Pset_BeamCommon - LoadBearing: yes; IsExternal: no; Reference: 05_ALLGEMEIN - TRAGENDE BAUTEILE 70 x 170
AC_Pset_RenovationAndPhasing - Renovation Status: Existing
Name | In | Slope (deg)
2 x Unterzug-045 | SPITZBODEN | 0.407212
2 x Unterzug-047 | SPITZBODEN | 0
Unterzug-044 | DACHGESCHOSS | -0.0459399
Unterzug-045 | DACHGESCHOSS | 0.0652591
Unterzug-046 | DACHGESCHOSS | 0.0597068
Unterzug-047 | DACHGESCHOSS | -0.393458

# IfcBeam: 05_ALLGEMEIN - TRAGENDE BAUTEILE 80 x 98 (28)
In: ERDGESCHOSS
Type - PredefinedType: LINTEL
Classification: 351 Deckenkonstruktionen (Classification DIN 267:2018-12); Sturz (ARCHICAD Klassifizierung); Material: 05_ALLGEMEIN - TRAGENDE BAUTEILE
Pset_BeamCommon - LoadBearing: yes; IsExternal: no; Reference: 05_ALLGEMEIN - TRAGENDE BAUTEILE 80 x 98
AC_Pset_RenovationAndPhasing - Renovation Status: Existing
Name | Slope (deg)
Unterzug-069 | 13.06
Unterzug-069 | -13.6855
Unterzug-070 | -13.1177
Unterzug-070 | -13.0555
Unterzug-071 | 13.3271
Unterzug-071 | 13.0034
3 x Unterzug-073 | 13.2527
Unterzug-073 | 13.4348
3 x Unterzug-074 | -12.5909
Unterzug-075 | -12.3453
Unterzug-075 | 12.9581
Unterzug-076 | -12.6052
Unterzug-076 | -13.5022
Unterzug-077 | 13.3951
Unterzug-077 | 12.216
Unterzug-078 | 13.0594
Unterzug-079 | 0.159758
Unterzug-079 | -0.0556737
Unterzug-080 | 0.218957
Unterzug-080 | -0.7458
Unterzug-081 | 44.322
Unterzug-081 | -46.0396
Unterzug-082 | 44.8422
Unterzug-083 | 45.4776

# IfcBeam: 05_ALLGEMEIN - TRAGENDE BAUTEILE 90 x 160 (3)
In: DACHGESCHOSS
Type - PredefinedType: LINTEL
Classification: 351 Deckenkonstruktionen (Classification DIN 267:2018-12); Sturz (ARCHICAD Klassifizierung); Material: 05_ALLGEMEIN - TRAGENDE BAUTEILE
Pset_BeamCommon - LoadBearing: yes; IsExternal: no; Reference: 05_ALLGEMEIN - TRAGENDE BAUTEILE 90 x 160
AC_Pset_RenovationAndPhasing - Renovation Status: Existing
Name | Slope (deg)
Unterzug-053 | -25.8595
Unterzug-054 | -25.2578
Unterzug-055 | -25.8552

# IfcBeam: 05_ALLGEMEIN - TRAGENDE BAUTEILE 90 x 235 (5)
In: DACHGESCHOSS
Type - PredefinedType: LINTEL
Classification: 351 Deckenkonstruktionen (Classification DIN 267:2018-12); Sturz (ARCHICAD Klassifizierung); Material: 05_ALLGEMEIN - TRAGENDE BAUTEILE
Pset_BeamCommon - LoadBearing: yes; IsExternal: no; Reference: 05_ALLGEMEIN - TRAGENDE BAUTEILE 90 x 235
AC_Pset_RenovationAndPhasing - Renovation Status: Existing
Name | Slope (deg)
Unterzug-051 | -6.38436
Unterzug-052 | -6.2965
Unterzug-053 | 6.05541
Unterzug-054 | 5.97059
Unterzug-055 | 26.1068

# IfcBeam: 05_ALLGEMEIN - TRAGENDE BAUTEILE 90 x 50 (5)
Type - PredefinedType: LINTEL
Classification: 351 Deckenkonstruktionen (Classification DIN 267:2018-12); Sturz (ARCHICAD Klassifizierung); Material: 05_ALLGEMEIN - TRAGENDE BAUTEILE
Pset_BeamCommon - LoadBearing: yes; IsExternal: no; Reference: 05_ALLGEMEIN - TRAGENDE BAUTEILE 90 x 50
AC_Pset_RenovationAndPhasing - Renovation Status: Existing
Name | In | Slope (deg)
Unterzug-004 | ERDGESCHOSS | 30.0017
Unterzug-004 | ERDGESCHOSS | 29.9524
Unterzug-005 | ERDGESCHOSS | 0
Unterzug-003 | KELLERGESCHOSS | 29.2822
Unterzug-004 | KELLERGESCHOSS | 0

# IfcBeam: 05_ALLGEMEIN - TRAGENDE BAUTEILE 90 x 57, Unterzug-005
In: KELLERGESCHOSS
Type - PredefinedType: LINTEL
Classification: 351 Deckenkonstruktionen (Classification DIN 267:2018-12); Sturz (ARCHICAD Klassifizierung); Material: 05_ALLGEMEIN - TRAGENDE BAUTEILE
Pset_BeamCommon - Slope: 0 deg; LoadBearing: yes; IsExternal: no; Reference: 05_ALLGEMEIN - TRAGENDE BAUTEILE 90 x 57
AC_Pset_RenovationAndPhasing - Renovation Status: Existing

# IfcBeam: 05_ALLGEMEIN - TRAGENDE BAUTEILE 95 x 100, Unterzug-058
In: DACHGESCHOSS
Type - PredefinedType: LINTEL
Classification: 351 Deckenkonstruktionen (Classification DIN 267:2018-12); Sturz (ARCHICAD Klassifizierung); Material: 05_ALLGEMEIN - TRAGENDE BAUTEILE
Pset_BeamCommon - Slope: 0 deg; LoadBearing: yes; IsExternal: no; Reference: 05_ALLGEMEIN - TRAGENDE BAUTEILE 95 x 100
AC_Pset_RenovationAndPhasing - Renovation Status: Existing

# IfcBeam: 05_ALLGEMEIN - TRAGENDE BAUTEILE 95 x 130 (4)
In: DACHGESCHOSS
Type - PredefinedType: LINTEL
Classification: 351 Deckenkonstruktionen (Classification DIN 267:2018-12); Sturz (ARCHICAD Klassifizierung); Material: 05_ALLGEMEIN - TRAGENDE BAUTEILE
Pset_BeamCommon - LoadBearing: yes; IsExternal: no; Reference: 05_ALLGEMEIN - TRAGENDE BAUTEILE 95 x 130
AC_Pset_RenovationAndPhasing - Renovation Status: Existing
Name | Slope (deg)
Unterzug-038 | -45.1705
Unterzug-056 | 45.2975
Unterzug-056 | -45.0859
Unterzug-057 | 44.7397

# IfcBeam: 05_ALLGEMEIN - TRAGENDE BAUTEILE 95 x 160 (66)
Type - PredefinedType: LINTEL
Classification: 351 Deckenkonstruktionen (Classification DIN 267:2018-12); Sturz (ARCHICAD Klassifizierung); Material: 05_ALLGEMEIN - TRAGENDE BAUTEILE
Pset_BeamCommon - LoadBearing: yes; IsExternal: no; Reference: 05_ALLGEMEIN - TRAGENDE BAUTEILE 95 x 160
AC_Pset_RenovationAndPhasing - Renovation Status: Existing
Name | In | Slope (deg)
Unterzug-026 | SPITZBODEN | -0.0985715
2 x Unterzug-025 | DACHGESCHOSS | 52.7441
Unterzug-026 | DACHGESCHOSS | -41.0894
2 x Unterzug-026 | DACHGESCHOSS | 52.0843
Unterzug-026 | DACHGESCHOSS | 42.7951
Unterzug-026 | DACHGESCHOSS | 43.4024
Unterzug-027 | DACHGESCHOSS | 51.8652
2 x Unterzug-027 | DACHGESCHOSS | 51.6762
2 x Unterzug-028 | DACHGESCHOSS | 51.056
Unterzug-028 | DACHGESCHOSS | 52.6736
2 x Unterzug-028 | DACHGESCHOSS | 51.4334
2 x Unterzug-029 | DACHGESCHOSS | 51.1049
Unterzug-029 | DACHGESCHOSS | 41.1629
Unterzug-029 | DACHGESCHOSS | -51.2444
Unterzug-030 | DACHGESCHOSS | 51.2951
Unterzug-030 | DACHGESCHOSS | 52.3297
Unterzug-030 | DACHGESCHOSS | 51.489
Unterzug-031 | DACHGESCHOSS | 51.6902
Unterzug-031 | DACHGESCHOSS | -51.7772
Unterzug-031 | DACHGESCHOSS | -52.5657
Unterzug-031 | DACHGESCHOSS | -51.5028
Unterzug-032 | DACHGESCHOSS | 51.8551
Unterzug-032 | DACHGESCHOSS | 51.5977
Unterzug-032 | DACHGESCHOSS | -0.0516444
Unterzug-033 | DACHGESCHOSS | 51.7284
Unterzug-034 | DACHGESCHOSS | -52.1224
Unterzug-034 | DACHGESCHOSS | -51.6526
2 x Unterzug-034 | DACHGESCHOSS | -51.0233
Unterzug-035 | DACHGESCHOSS | 50.8735
Unterzug-035 | DACHGESCHOSS | -52.4029
Unterzug-036 | DACHGESCHOSS | 52.0134
Unterzug-036 | DACHGESCHOSS | -51.045
Unterzug-037 | DACHGESCHOSS | 52.2575
Unterzug-039 | DACHGESCHOSS | 52.5036
Unterzug-040 | DACHGESCHOSS | -52.053
Unterzug-041 | DACHGESCHOSS | 51.4732
Unterzug-042 | DACHGESCHOSS | -51.73
Unterzug-043 | DACHGESCHOSS | -51.0824
Unterzug-043 | DACHGESCHOSS | -51.8293
Unterzug-044 | DACHGESCHOSS | 52.0695
Unterzug-045 | DACHGESCHOSS | -52.11
Unterzug-046 | DACHGESCHOSS | -51.6995
Unterzug-046 | DACHGESCHOSS | 52.1089
2 x Unterzug-047 | DACHGESCHOSS | -51.9888
Unterzug-047 | DACHGESCHOSS | -52.8233
Unterzug-048 | DACHGESCHOSS | 51.7857
Unterzug-048 | DACHGESCHOSS | -52.8912
Unterzug-049 | DACHGESCHOSS | 53.2363
Unterzug-049 | DACHGESCHOSS | 52.2212
Unterzug-050 | DACHGESCHOSS | -52.4372
Unterzug-050 | DACHGESCHOSS | -51.9196
Unterzug-051 | DACHGESCHOSS | 51.7169
Unterzug-051 | DACHGESCHOSS | -52.2977
Unterzug-052 | DACHGESCHOSS | 52.2354
Unterzug-052 | DACHGESCHOSS | 50.4376
Unterzug-053 | DACHGESCHOSS | 52.0473
Unterzug-054 | DACHGESCHOSS | 51.7938
Unterzug-055 | DACHGESCHOSS | 51.6103

# IfcBeam: 05_ALLGEMEIN - TRAGENDE BAUTEILE 95 x 189, Unterzug-026
In: SPITZBODEN
Type - PredefinedType: LINTEL
Classification: 351 Deckenkonstruktionen (Classification DIN 267:2018-12); Sturz (ARCHICAD Klassifizierung); Material: 05_ALLGEMEIN - TRAGENDE BAUTEILE
Pset_BeamCommon - Slope: 0.443231 deg; LoadBearing: yes; IsExternal: no; Reference: 05_ALLGEMEIN - TRAGENDE BAUTEILE 95 x 189
AC_Pset_RenovationAndPhasing - Renovation Status: Existing

# IfcBeam: 05_ALLGEMEIN - TRAGENDE BAUTEILE D190 (4)
In: 2.OBERGESCHOSS
Type - PredefinedType: LINTEL
Classification: 351 Deckenkonstruktionen (Classification DIN 267:2018-12); Sturz (ARCHICAD Klassifizierung); Material: 05_ALLGEMEIN - TRAGENDE BAUTEILE
Pset_BeamCommon - LoadBearing: yes; IsExternal: no; Reference: 05_ALLGEMEIN - TRAGENDE BAUTEILE D190
AC_Pset_RenovationAndPhasing - Renovation Status: Existing
Name | Slope (deg)
Unterzug-095 | -2.60874
Unterzug-096 | -2.79581
Unterzug-097 | -0.377016
Unterzug-098 | 0.480719

# IfcBeam: 47_Holz, Bauholz 130 x 130 (20)
Type - PredefinedType: LINTEL
Classification: 351 Deckenkonstruktionen (Classification DIN 267:2018-12); Sturz (ARCHICAD Klassifizierung); Material: 47_Holz, Bauholz
Pset_BeamCommon - LoadBearing: yes; IsExternal: no; Reference: 47_Holz, Bauholz 130 x 130
AC_Pset_RenovationAndPhasing - Renovation Status: Existing
Name | In | Slope (deg)
Unterzug-058 | SPITZBODEN | 0.796995
Unterzug-061 | SPITZBODEN | 45.0864
Unterzug-061 | SPITZBODEN | 0.375688
Unterzug-062 | SPITZBODEN | -44.706
Unterzug-062 | SPITZBODEN | 47.9643
Unterzug-063 | SPITZBODEN | 47.4877
Unterzug-064 | SPITZBODEN | -49.3613
2 x Unterzug-053 | DACHGESCHOSS | 63.0363
Unterzug-054 | DACHGESCHOSS | 63.537
Unterzug-055 | DACHGESCHOSS | 64.197
Unterzug-056 | DACHGESCHOSS | 63.9196
Unterzug-057 | DACHGESCHOSS | 63.5842
Unterzug-058 | DACHGESCHOSS | 0.796995
Unterzug-059 | DACHGESCHOSS | -64.3594
Unterzug-060 | DACHGESCHOSS | -65.148
Unterzug-061 | DACHGESCHOSS | -64.6806
2 x Unterzug-062 | DACHGESCHOSS | 64.7354
Unterzug-062 | DACHGESCHOSS | -64.5574

# IfcBeam: 47_Holz, Bauholz 130 x 160 (7)
In: DACHGESCHOSS
Type - PredefinedType: LINTEL
Classification: 351 Deckenkonstruktionen (Classification DIN 267:2018-12); Sturz (ARCHICAD Klassifizierung); Material: 47_Holz, Bauholz
Pset_BeamCommon - LoadBearing: yes; IsExternal: no; Reference: 47_Holz, Bauholz 130 x 160
AC_Pset_RenovationAndPhasing - Renovation Status: Existing
Name | Slope (deg)
Unterzug-061 | 0.372428
Unterzug-062 | 0.0443469
Unterzug-063 | 0.238502
Unterzug-067 | 0.561724
Unterzug-068 | 0.0260913
Unterzug-069 | -2.11706
Unterzug-070 | 0.0927769

# IfcBeam: 47_Holz, Bauholz 145 x 80, Unterzug-021
In: ERDGESCHOSS
Type - PredefinedType: LINTEL
Classification: 351 Deckenkonstruktionen (Classification DIN 267:2018-12); Sturz (ARCHICAD Klassifizierung); Material: 47_Holz, Bauholz
Pset_BeamCommon - Slope: 0 deg; LoadBearing: yes; IsExternal: no; Reference: 47_Holz, Bauholz 145 x 80
AC_Pset_RenovationAndPhasing - Renovation Status: Existing

# IfcBeam: 47_Holz, Bauholz 154 x 160 (12)
In: ERDGESCHOSS
Type - PredefinedType: LINTEL
Classification: 351 Deckenkonstruktionen (Classification DIN 267:2018-12); Sturz (ARCHICAD Klassifizierung); Material: 47_Holz, Bauholz
Pset_BeamCommon - LoadBearing: yes; IsExternal: no; Reference: 47_Holz, Bauholz 154 x 160
AC_Pset_RenovationAndPhasing - Renovation Status: Existing
Name | Slope (deg)
Unterzug-006 | 22.1532
Unterzug-007 | 29.6543
Unterzug-008 | 29.7887
Unterzug-009 | 22.1148
Unterzug-010 | 29.7034
Unterzug-012 | 29.6297
Unterzug-013 | -22.2383
Unterzug-014 | -29.7425
Unterzug-015 | -29.6541
Unterzug-015 | -22.1617
Unterzug-016 | -29.8434
Unterzug-017 | -29.7236

# IfcBeam: 47_Holz, Bauholz 60 x 110 (7)
Type - PredefinedType: LINTEL
Classification: 351 Deckenkonstruktionen (Classification DIN 267:2018-12); Sturz (ARCHICAD Klassifizierung); Material: 47_Holz, Bauholz
Pset_BeamCommon - LoadBearing: yes; IsExternal: no; Reference: 47_Holz, Bauholz 60 x 110
AC_Pset_RenovationAndPhasing - Renovation Status: Existing
Name | In | Slope (deg)
Unterzug-065 | SPITZBODEN | 63.7148
Unterzug-062 | DACHGESCHOSS | -64.1714
Unterzug-063 | DACHGESCHOSS | -64.9418
Unterzug-064 | DACHGESCHOSS | -65.33
Unterzug-065 | DACHGESCHOSS | -65.17
Unterzug-066 | DACHGESCHOSS | -64.7828
Unterzug-067 | DACHGESCHOSS | 64.6768

# IfcBeam: 47_Holz, Bauholz 61 x 110, Unterzug-069
In: DACHGESCHOSS
Type - PredefinedType: LINTEL
Classification: 351 Deckenkonstruktionen (Classification DIN 267:2018-12); Sturz (ARCHICAD Klassifizierung); Material: 47_Holz, Bauholz
Pset_BeamCommon - Slope: 63.8512 deg; LoadBearing: yes; IsExternal: no; Reference: 47_Holz, Bauholz 61 x 110
AC_Pset_RenovationAndPhasing - Renovation Status: Existing

# IfcBeam: 47_Holz, Bauholz 70 x 163 (4)
In: DACHGESCHOSS
Type - PredefinedType: LINTEL
Classification: 351 Deckenkonstruktionen (Classification DIN 267:2018-12); Sturz (ARCHICAD Klassifizierung); Material: 47_Holz, Bauholz
Pset_BeamCommon - LoadBearing: yes; IsExternal: no; Reference: 47_Holz, Bauholz 70 x 163
AC_Pset_RenovationAndPhasing - Renovation Status: Existing
Name | Slope (deg)
Unterzug-063 | 0.207704
Unterzug-063 | 0.623673
Unterzug-064 | 0.362238
Unterzug-065 | -0.556636

# IfcBeam: 47_Holz, Bauholz 75 x 110, Unterzug-068
In: DACHGESCHOSS
Type - PredefinedType: LINTEL
Classification: 351 Deckenkonstruktionen (Classification DIN 267:2018-12); Sturz (ARCHICAD Klassifizierung); Material: 47_Holz, Bauholz
Pset_BeamCommon - Slope: 63.6043 deg; LoadBearing: yes; IsExternal: no; Reference: 47_Holz, Bauholz 75 x 110
AC_Pset_RenovationAndPhasing - Renovation Status: Existing

# IfcBeam: 56_Metall, Stahl verzinkt 15 x 280 (2)
In: ERDGESCHOSS
Type - PredefinedType: LINTEL
Classification: 351 Deckenkonstruktionen (Classification DIN 267:2018-12); Sturz (ARCHICAD Klassifizierung); Material: 56_Metall, Stahl verzinkt
Pset_BeamCommon - Slope: 0 deg; LoadBearing: yes; IsExternal: no; Reference: 56_Metall, Stahl verzinkt 15 x 280
AC_Pset_RenovationAndPhasing - Renovation Status: Existing

# IfcBeam: 56_Metall, Stahl verzinkt 20 x 267 (4)
In: ERDGESCHOSS
Type - PredefinedType: LINTEL
Classification: 351 Deckenkonstruktionen (Classification DIN 267:2018-12); Sturz (ARCHICAD Klassifizierung); Material: 56_Metall, Stahl verzinkt
Pset_BeamCommon - Slope: 0 deg; LoadBearing: yes; IsExternal: no; Reference: 56_Metall, Stahl verzinkt 20 x 267
AC_Pset_RenovationAndPhasing - Renovation Status: Existing
Name
Unterzug-004
Unterzug-005
Unterzug-006
Unterzug-007

# IfcBeam: 56_Metall, Stahl verzinkt 20 x 291 (2)
In: ERDGESCHOSS
Type - PredefinedType: LINTEL
Classification: 351 Deckenkonstruktionen (Classification DIN 267:2018-12); Sturz (ARCHICAD Klassifizierung); Material: 56_Metall, Stahl verzinkt
Pset_BeamCommon - Slope: 0 deg; LoadBearing: yes; IsExternal: no; Reference: 56_Metall, Stahl verzinkt 20 x 291
AC_Pset_RenovationAndPhasing - Renovation Status: Existing
Name
Unterzug-005
Unterzug-006

# IfcBeam: 56_Metall, Stahl verzinkt D60 (4)
Type - PredefinedType: LINTEL
Classification: 351 Deckenkonstruktionen (Classification DIN 267:2018-12); Sturz (ARCHICAD Klassifizierung); Material: 56_Metall, Stahl verzinkt
Pset_BeamCommon - Slope: 0 deg; LoadBearing: yes; IsExternal: no; Reference: 56_Metall, Stahl verzinkt D60
AC_Pset_RenovationAndPhasing - Renovation Status: Existing
Name | In
Unterzug-018 | 2.OBERGESCHOSS
Unterzug-018 | 1.OBERGESCHOSS
Unterzug-018 | ERDGESCHOSS
Unterzug-018 | KELLERGESCHOSS

# IfcBeam: Dachsims (1) 1070 x 1189 (4)
In: DACHGESCHOSS
Type - PredefinedType: LINTEL
Classification: 351 Deckenkonstruktionen (Classification DIN 267:2018-12); Sturz (ARCHICAD Klassifizierung); Material: 05_ALLGEMEIN - TRAGENDE BAUTEILE
Pset_BeamCommon - Slope: 0 deg; LoadBearing: yes; IsExternal: no; Reference: Dachsims (1) 1070 x 1189
AC_Pset_RenovationAndPhasing - Renovation Status: Existing

# IfcBeam: Dachsims Hof Treppenhaus 564 x 1687 (3)
In: 2.OBERGESCHOSS
Type - PredefinedType: LINTEL
Classification: 351 Deckenkonstruktionen (Classification DIN 267:2018-12); Sturz (ARCHICAD Klassifizierung); Material: 05_ALLGEMEIN - TRAGENDE BAUTEILE
Pset_BeamCommon - Slope: 0 deg; LoadBearing: yes; IsExternal: no; Reference: Dachsims Hof Treppenhaus 564 x 1687
AC_Pset_RenovationAndPhasing - Renovation Status: Existing
Name
2 x Unterzug-013
Unterzug-014

# IfcBeam: Deckendeko 101 x 50 (64)
In: 2.OBERGESCHOSS
Type - PredefinedType: LINTEL
Classification: 351 Deckenkonstruktionen (Classification DIN 267:2018-12); Sturz (ARCHICAD Klassifizierung); Material: 01_ALLGEMEIN - BAUTEIL
Pset_BeamCommon - Slope: 0 deg; LoadBearing: yes; IsExternal: no; Reference: Deckendeko 101 x 50
AC_Pset_RenovationAndPhasing - Renovation Status: Existing
Name
Unterzug-025
Unterzug-026
Unterzug-027
Unterzug-028
Unterzug-029
Unterzug-030
Unterzug-031
Unterzug-032
Unterzug-033
Unterzug-034
Unterzug-035
Unterzug-036
Unterzug-037
Unterzug-038
Unterzug-039
Unterzug-040
Unterzug-041
Unterzug-042
Unterzug-043
Unterzug-044
Unterzug-045
Unterzug-046
Unterzug-047
Unterzug-048
Unterzug-049
Unterzug-050
Unterzug-051
Unterzug-052
Unterzug-053
Unterzug-054
Unterzug-055
Unterzug-056
Unterzug-057
Unterzug-058
Unterzug-059
Unterzug-060
Unterzug-061
Unterzug-062
Unterzug-063
Unterzug-064
Unterzug-065
Unterzug-066
Unterzug-067
Unterzug-068
Unterzug-069
Unterzug-070
Unterzug-071
Unterzug-072
Unterzug-073
Unterzug-074
Unterzug-075
Unterzug-076
Unterzug-077
Unterzug-078
Unterzug-079
Unterzug-080
Unterzug-081
Unterzug-082
Unterzug-083
Unterzug-084
Unterzug-085
Unterzug-086
Unterzug-087
Unterzug-088

# IfcBeam: Gesims Holz 294 x 365 (4)
In: DACHGESCHOSS
Type - PredefinedType: LINTEL
Classification: 351 Deckenkonstruktionen (Classification DIN 267:2018-12); Sturz (ARCHICAD Klassifizierung); Material: 05_ALLGEMEIN - TRAGENDE BAUTEILE
Pset_BeamCommon - Slope: 0 deg; LoadBearing: yes; IsExternal: no; Reference: Gesims Holz 294 x 365
AC_Pset_RenovationAndPhasing - Renovation Status: Existing

# IfcBeam: HD260X142 265 x 278, Unterzug-023
In: KELLERGESCHOSS
Type - PredefinedType: LINTEL
Classification: 351 Deckenkonstruktionen (Classification DIN 267:2018-12); Sturz (ARCHICAD Klassifizierung); Material: Stahl verzinkt
Pset_BeamCommon - Slope: 0 deg; LoadBearing: yes; IsExternal: no; Reference: HD260X142 265 x 278
AC_Pset_RenovationAndPhasing - Renovation Status: Existing

# IfcBeam: HEB200 200 x 200 (4)
In: ERDGESCHOSS
Type - PredefinedType: LINTEL
Classification: 351 Deckenkonstruktionen (Classification DIN 267:2018-12); Sturz (ARCHICAD Klassifizierung); Material: Stahl verzinkt
Pset_BeamCommon - Slope: 0 deg; LoadBearing: yes; IsExternal: no; Reference: HEB200 200 x 200
AC_Pset_RenovationAndPhasing - Renovation Status: Existing

# IfcBeam: IPEA160 82 x 157 (2)
In: 1.OBERGESCHOSS
Type - PredefinedType: LINTEL
Classification: 351 Deckenkonstruktionen (Classification DIN 267:2018-12); Sturz (ARCHICAD Klassifizierung); Material: Stahl verzinkt
Pset_BeamCommon - LoadBearing: yes; IsExternal: no; Reference: IPEA160 82 x 157
AC_Pset_RenovationAndPhasing - Renovation Status: Existing
Name | Slope (deg)
Unterzug-019 | 0.486693
Unterzug-019 | 0

# IfcBeam: Sims 1 95 x 211 (43)
In: 2.OBERGESCHOSS
Type - PredefinedType: LINTEL
Classification: 351 Deckenkonstruktionen (Classification DIN 267:2018-12); Sturz (ARCHICAD Klassifizierung); Material: 05_ALLGEMEIN - TRAGENDE BAUTEILE
Pset_BeamCommon - LoadBearing: yes; IsExternal: no; Reference: Sims 1 95 x 211
AC_Pset_RenovationAndPhasing - Renovation Status: Existing
Name | Slope (deg)
Unterzug-015 | 0
Unterzug-016 | 0
2 x Unterzug-017 | 0
Unterzug-018 | 0
Unterzug-019 | 0
Unterzug-020 | 0
Unterzug-021 | 0
Unterzug-022 | 0
Unterzug-023 | 0
Unterzug-024 | 0
Unterzug-025 | 0
Unterzug-026 | 0
Unterzug-027 | 0
Unterzug-028 | 0
Unterzug-029 | 0
Unterzug-030 | 0
Unterzug-031 | 0
Unterzug-032 | 0
Unterzug-033 | 0
Unterzug-034 | 0
Unterzug-035 | 0
Unterzug-036 | 0
Unterzug-037 | 0
3 x Unterzug-038 | 0
2 x Unterzug-039 | 0
Unterzug-040 | 0
Unterzug-041 | 0
Unterzug-042 | 0
Unterzug-043 | 0
Unterzug-044 | 0
Unterzug-045 | 0
Unterzug-046 | 0
Unterzug-047 | 0
Unterzug-048 | -0.943581
Unterzug-049 | 0
Unterzug-050 | 0
Unterzug-051 | 0
Unterzug-052 | 0
Unterzug-053 | 0

# IfcBeam: U200 75 x 200 (2)
In: ERDGESCHOSS
Type - PredefinedType: LINTEL
Classification: 351 Deckenkonstruktionen (Classification DIN 267:2018-12); Sturz (ARCHICAD Klassifizierung); Material: Stahl verzinkt
Pset_BeamCommon - Slope: 0.136768 deg; LoadBearing: yes; IsExternal: no; Reference: U200 75 x 200
AC_Pset_RenovationAndPhasing - Renovation Status: Existing

# IfcBeam: Verzierung 1 299 x 894 (3)
In: 1.OBERGESCHOSS
Type - PredefinedType: LINTEL
Classification: 351 Deckenkonstruktionen (Classification DIN 267:2018-12); Sturz (ARCHICAD Klassifizierung); Material: 05_ALLGEMEIN - TRAGENDE BAUTEILE
Pset_BeamCommon - Slope: 0 deg; LoadBearing: yes; IsExternal: no; Reference: Verzierung 1 299 x 894
AC_Pset_RenovationAndPhasing - Renovation Status: Existing
Name
Unterzug-010
2 x Unterzug-011

# IfcBeam: sims 374 x 425 (9)
Type - PredefinedType: LINTEL
Classification: 351 Deckenkonstruktionen (Classification DIN 267:2018-12); Sturz (ARCHICAD Klassifizierung)
Pset_BeamCommon - Slope: 0 deg; LoadBearing: yes; IsExternal: no; Reference: sims 374 x 425
AC_Pset_RenovationAndPhasing - Renovation Status: Existing
Name | In
4 x Unterzug-083 | 1.OBERGESCHOSS
5 x Unterzug-083 | ERDGESCHOSS

# IfcBeam: sims kant. 700 x 863 (2)
In: ERDGESCHOSS
Type - PredefinedType: LINTEL
Classification: 351 Deckenkonstruktionen (Classification DIN 267:2018-12); Sturz (ARCHICAD Klassifizierung); Material: 01_ALLGEMEIN - BAUTEIL
Pset_BeamCommon - Slope: 0 deg; LoadBearing: yes; IsExternal: no; Reference: sims kant. 700 x 863
AC_Pset_RenovationAndPhasing - Renovation Status: Existing

# IfcBeam: sims kantine 289 x 434 (4)
In: ERDGESCHOSS
Type - PredefinedType: LINTEL
Classification: 351 Deckenkonstruktionen (Classification DIN 267:2018-12); Sturz (ARCHICAD Klassifizierung); Material: 05_ALLGEMEIN - TRAGENDE BAUTEILE
Pset_BeamCommon - Slope: 0 deg; LoadBearing: yes; IsExternal: no; Reference: sims kantine 289 x 434
AC_Pset_RenovationAndPhasing - Renovation Status: Existing
Name
3 x Unterzug-006
Unterzug-007

# IfcBuildingElementPart (1988)
Name | In | Material
3 x 47_Holz, Bauholz | DACHGESCHOSS | 47_Holz, Bauholz
2 x 56_Metall, Stahl verzinkt | 2.OBERGESCHOSS | 56_Metall, Stahl verzinkt
2 x 56_Metall, Stahl verzinkt | 1.OBERGESCHOSS | 56_Metall, Stahl verzinkt
59 x 05_ALLGEMEIN - TRAGENDE BAUTEILE | 1.OBERGESCHOSS | 05_ALLGEMEIN - TRAGENDE BAUTEILE
4 x 33_Dach, Stehfalz | 1.OBERGESCHOSS | 33_Dach, Stehfalz
6 x 01_ALLGEMEIN - BAUTEIL | 1.OBERGESCHOSS | 01_ALLGEMEIN - BAUTEIL
470 x 53_Metall, Aluminium | ERDGESCHOSS | 53_Metall, Aluminium
102 x 45_Glas, Normalglas | ERDGESCHOSS | 45_Glas, Normalglas
2 x 54_Metall, Edelstahl | ERDGESCHOSS | 54_Metall, Edelstahl
79 x 56_Metall, Stahl verzinkt | ERDGESCHOSS | 56_Metall, Stahl verzinkt
102 x 05_ALLGEMEIN - TRAGENDE BAUTEILE | ERDGESCHOSS | 05_ALLGEMEIN - TRAGENDE BAUTEILE
5 x 33_Dach, Stehfalz | ERDGESCHOSS | 33_Dach, Stehfalz
48 x 01_ALLGEMEIN - BAUTEIL | ERDGESCHOSS | 01_ALLGEMEIN - BAUTEIL
818 x 53_Metall, Aluminium | KELLERGESCHOSS | 53_Metall, Aluminium
177 x 45_Glas, Normalglas | KELLERGESCHOSS | 45_Glas, Normalglas
7 x 54_Metall, Edelstahl | KELLERGESCHOSS | 54_Metall, Edelstahl
24 x 56_Metall, Stahl verzinkt | KELLERGESCHOSS | 56_Metall, Stahl verzinkt
78 x 05_ALLGEMEIN - TRAGENDE BAUTEILE | KELLERGESCHOSS | 05_ALLGEMEIN - TRAGENDE BAUTEILE

# IfcBuildingElementProxy: 01_ALLGEMEIN - BAUTEIL (377)
Material: 01_ALLGEMEIN - BAUTEIL
AC_Pset_RenovationAndPhasing - Renovation Status: Existing
Name | In
4 x Morph-312 | SPITZBODEN
Morph-313 | SPITZBODEN
2 x Morph-340 | SPITZBODEN
Morph-349 | SPITZBODEN
2 x Morph-316 | DACHGESCHOSS
Morph-017 | 2.OBERGESCHOSS
Morph-018 | 2.OBERGESCHOSS
Morph-172 | 2.OBERGESCHOSS
6 x Morph-306 | 2.OBERGESCHOSS
10 x Morph-314 | 2.OBERGESCHOSS
6 x Morph-315 | 2.OBERGESCHOSS
12 x Morph-316 | 2.OBERGESCHOSS
10 x Morph-317 | 2.OBERGESCHOSS
13 x Morph-322 | 2.OBERGESCHOSS
16 x Morph-338 | 2.OBERGESCHOSS
Morph-313 | 1.OBERGESCHOSS
3 x Morph-314 | 1.OBERGESCHOSS
5 x Morph-315 | 1.OBERGESCHOSS
70 x Morph-316 | 1.OBERGESCHOSS
5 x Morph-317 | 1.OBERGESCHOSS
6 x Morph-323 | 1.OBERGESCHOSS
28 x Morph-329 | 1.OBERGESCHOSS
21 x Morph-331 | 1.OBERGESCHOSS
4 x Morph-337 | 1.OBERGESCHOSS
2 x Morph-352 | 1.OBERGESCHOSS
Morph-173 | ERDGESCHOSS
3 x Morph-174 | ERDGESCHOSS
3 x Morph-175 | ERDGESCHOSS
3 x Morph-176 | ERDGESCHOSS
3 x Morph-177 | ERDGESCHOSS
3 x Morph-178 | ERDGESCHOSS
3 x Morph-179 | ERDGESCHOSS
3 x Morph-180 | ERDGESCHOSS
3 x Morph-181 | ERDGESCHOSS
3 x Morph-182 | ERDGESCHOSS
3 x Morph-183 | ERDGESCHOSS
3 x Morph-184 | ERDGESCHOSS
3 x Morph-185 | ERDGESCHOSS
6 x Morph-186 | ERDGESCHOSS
Morph-188 | ERDGESCHOSS
6 x Morph-286 | ERDGESCHOSS
6 x Morph-287 | ERDGESCHOSS
10 x Morph-288 | ERDGESCHOSS
10 x Morph-289 | ERDGESCHOSS
10 x Morph-290 | ERDGESCHOSS
10 x Morph-291 | ERDGESCHOSS
10 x Morph-292 | ERDGESCHOSS
4 x Morph-293 | ERDGESCHOSS
Morph-294 | ERDGESCHOSS
9 x Morph-295 | ERDGESCHOSS
3 x Morph-297 | ERDGESCHOSS
12 x Morph-302 | ERDGESCHOSS
5 x Morph-320 | ERDGESCHOSS
Morph-329 | ERDGESCHOSS
Morph-330 | ERDGESCHOSS
Morph-331 | ERDGESCHOSS
Morph-341 | ERDGESCHOSS
Morph-344 | ERDGESCHOSS
Morph-021 | KELLERGESCHOSS

# IfcBuildingElementProxy: 05_ALLGEMEIN - TRAGENDE BAUTEILE (233)
Material: 05_ALLGEMEIN - TRAGENDE BAUTEILE
AC_Pset_RenovationAndPhasing - Renovation Status: Existing
Name | In
28 x Morph-316 | 2.OBERGESCHOSS
2 x Morph-313 | 1.OBERGESCHOSS
104 x Morph-316 | 1.OBERGESCHOSS
99 x Morph-316 | ERDGESCHOSS

# IfcBuildingElementProxy: 1-Flügelfenster 25 (142)
Classification: Öffnung (ARCHICAD Klassifizierung)
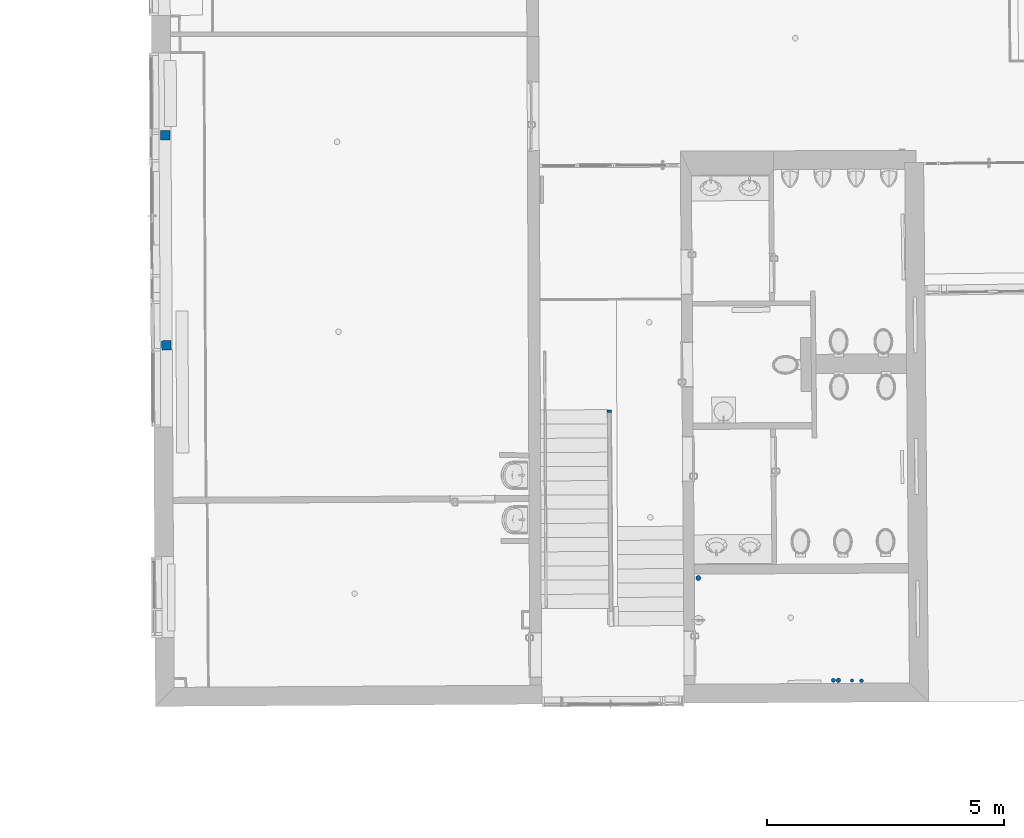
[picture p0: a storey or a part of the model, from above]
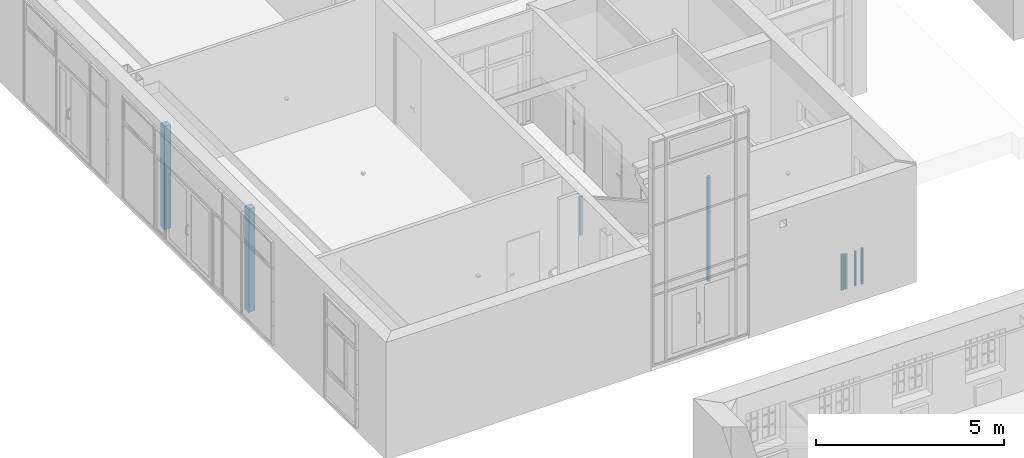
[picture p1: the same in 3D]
Properties of the parts of a building model (IFC2X3), part 2 of 4

# IfcBuildingElementProxy: 1-Flügelfenster 25 (142)
Pset_WindowCommon - SmokeStop: no; ThermalTransmittance: 0
AC_Pset_RenovationAndPhasing - Renovation Status: Existing
Name | In
39 x Fenster-015 | 2.OBERGESCHOSS
37 x Fenster-015 | 1.OBERGESCHOSS
2 x Fenster-017 | 1.OBERGESCHOSS
39 x Fenster-015 | ERDGESCHOSS
Fenster-016 | ERDGESCHOSS
2 x Fenster-017 | ERDGESCHOSS
Fenster-016 | KELLERGESCHOSS
21 x Fenster-015 | KELLERGESCHOSS

# IfcBuildingElementProxy: 2-Flügelfenster 1+1 25 (14)
Classification: Öffnung (ARCHICAD Klassifizierung)
Pset_WindowCommon - SmokeStop: no; ThermalTransmittance: 0
AC_Pset_RenovationAndPhasing - Renovation Status: Existing
Name | In
4 x Fenster-016 | 2.OBERGESCHOSS
4 x Fenster-016 | 1.OBERGESCHOSS
4 x Fenster-016 | ERDGESCHOSS
2 x Fenster-016 | KELLERGESCHOSS

# IfcBuildingElementProxy: 2-Flügelfenster 25 (84)
Classification: Öffnung (ARCHICAD Klassifizierung)
Pset_WindowCommon - SmokeStop: no; ThermalTransmittance: 0
AC_Pset_RenovationAndPhasing - Renovation Status: Existing
Name | In
19 x Fenster-015 | 2.OBERGESCHOSS
20 x Fenster-015 | 1.OBERGESCHOSS
20 x Fenster-015 | ERDGESCHOSS
18 x Fenster-015 | KELLERGESCHOSS
7 x Fenster-014 | KELLERGESCHOSS

# IfcBuildingElementProxy: 56_Metall, Stahl verzinkt (7)
Material: 56_Metall, Stahl verzinkt
AC_Pset_RenovationAndPhasing - Renovation Status: Existing
Name | In
Morph-328 | 1.OBERGESCHOSS
04 | ERDGESCHOSS
Morph-013 | ERDGESCHOSS
Morph-325 | ERDGESCHOSS
Morph-329 | ERDGESCHOSS
Stütze-011 | ERDGESCHOSS
Stütze-012 | ERDGESCHOSS

# IfcBuildingElementProxy: Dreieckfenster Fest 2 25, Fenster-025
In: 2.OBERGESCHOSS
Classification: Öffnung (ARCHICAD Klassifizierung)
Pset_WindowCommon - SmokeStop: no; ThermalTransmittance: 0
AC_Pset_RenovationAndPhasing - Renovation Status: Existing

# IfcBuildingElementProxy: Duschwanne 01 25, Objekt-00220
In: KELLERGESCHOSS
AC_Pset_RenovationAndPhasing - Renovation Status: Existing

# IfcBuildingElementProxy: Ellipsoid 02 25 (3)
In: SPITZBODEN
AC_Pset_RenovationAndPhasing - Renovation Status: Existing

# IfcBuildingElementProxy: F Altbau 1-Fl 25 (2)
In: KELLERGESCHOSS
Classification: Öffnung (ARCHICAD Klassifizierung)
Pset_WindowCommon - SmokeStop: no; ThermalTransmittance: 0
AC_Pset_RenovationAndPhasing - Renovation Status: Existing

# IfcBuildingElementProxy: F Segment-Abschluss 1-Fl 25 (21)
Classification: Öffnung (ARCHICAD Klassifizierung)
Pset_WindowCommon - SmokeStop: no; ThermalTransmittance: 0
AC_Pset_RenovationAndPhasing - Renovation Status: Existing
Name | In
8 x Fenster-015 | 2.OBERGESCHOSS
7 x Fenster-015 | 1.OBERGESCHOSS
6 x Fenster-015 | ERDGESCHOSS

# IfcBuildingElementProxy: F Segment-Abschluss 2-Fl 25 (11)
Classification: Öffnung (ARCHICAD Klassifizierung)
Pset_WindowCommon - SmokeStop: no; ThermalTransmittance: 0
AC_Pset_RenovationAndPhasing - Renovation Status: Existing
Name | In
Fenster-015 | 2.OBERGESCHOSS
Fenster-015 | 1.OBERGESCHOSS
Fenster-015 | ERDGESCHOSS
8 x Fenster-015 | KELLERGESCHOSS

# IfcBuildingElementProxy: Fallrohr 25 (3)
AC_Pset_RenovationAndPhasing - Renovation Status: Existing
Name | In
Objekt-00223 | 1.OBERGESCHOSS
Objekt-00223 | ERDGESCHOSS
Objekt-00223 | KELLERGESCHOSS

# IfcBuildingElementProxy: Fallrohr Ellbogen 25, Objekt-00225
In: KELLERGESCHOSS
AC_Pset_RenovationAndPhasing - Renovation Status: Existing

# IfcBuildingElementProxy: Fallrohr Vorsprung 25 (3)
AC_Pset_RenovationAndPhasing - Renovation Status: Existing
Name | In
2 x Objekt-00224 | DACHGESCHOSS
Objekt-00224 | KELLERGESCHOSS

# IfcBuildingElementProxy: Fassadentyp (24)
Pset_CurtainWallCommon - ThermalTransmittance: 0
AC_Pset_RenovationAndPhasing - Renovation Status: Existing
Name | In
8 x Fassade-002 | ERDGESCHOSS
16 x Fassade-002 | KELLERGESCHOSS

# IfcBuildingElementProxy: Feuerlöscher 3D 25 (21)
AC_Pset_RenovationAndPhasing - Renovation Status: Existing
Name | In
3 x Objekt-00219 | 2.OBERGESCHOSS
6 x Objekt-00219 | 1.OBERGESCHOSS
5 x Objekt-00219 | ERDGESCHOSS
7 x Objekt-00219 | KELLERGESCHOSS

# IfcBuildingElementProxy: Feuermelder 3D 25 (23)
AC_Pset_RenovationAndPhasing - Renovation Status: Existing
Name | In
5 x Objekt-00219 | 2.OBERGESCHOSS
4 x Objekt-00219 | 1.OBERGESCHOSS
9 x Objekt-00219 | ERDGESCHOSS
5 x Objekt-00219 | KELLERGESCHOSS

# IfcBuildingElementProxy: Flexijet Standort, Objekt-00222
In: KELLERGESCHOSS
AC_Pset_RenovationAndPhasing - Renovation Status: Existing

# IfcBuildingElementProxy: Geländerart (4)
In: ERDGESCHOSS
AC_Pset_RenovationAndPhasing - Renovation Status: Existing

# IfcBuildingElementProxy: Glasziegelfenster 25, Fenster-016
In: KELLERGESCHOSS
Classification: Öffnung (ARCHICAD Klassifizierung)
Pset_WindowCommon - SmokeStop: no; ThermalTransmittance: 0
AC_Pset_RenovationAndPhasing - Renovation Status: Existing

# IfcBuildingElementProxy: Mehrfach Waschbecken 25 (2)
In: KELLERGESCHOSS
AC_Pset_RenovationAndPhasing - Renovation Status: Existing

# IfcBuildingElementProxy: Pyramide 25 (3)
In: SPITZBODEN
AC_Pset_RenovationAndPhasing - Renovation Status: Existing

# IfcBuildingElementProxy: Rauchmelder 25 (44)
AC_Pset_RenovationAndPhasing - Renovation Status: Existing
Name | In
11 x Objekt-00219 | 2.OBERGESCHOSS
8 x Objekt-00219 | 1.OBERGESCHOSS
11 x Objekt-00219 | ERDGESCHOSS
7 x Objekt-00219 | KELLERGESCHOSS
7 x Objekt-00220 | KELLERGESCHOSS

# IfcBuildingElementProxy: Regenrinne 25, Objekt-00226
In: DACHGESCHOSS
AC_Pset_RenovationAndPhasing - Renovation Status: Existing

# IfcBuildingElementProxy: Rundfenster 25, Fenster-015
In: DACHGESCHOSS
Classification: Öffnung (ARCHICAD Klassifizierung)
Pset_WindowCommon - SmokeStop: no; ThermalTransmittance: 0
AC_Pset_RenovationAndPhasing - Renovation Status: Existing

# IfcBuildingElementProxy: Stand WC 25, Objekt-00221
In: 2.OBERGESCHOSS
AC_Pset_RenovationAndPhasing - Renovation Status: Existing

# IfcBuildingElementProxy: Urinal 1 25 (16)
AC_Pset_RenovationAndPhasing - Renovation Status: Existing
Name | In
4 x Objekt-00222 | 1.OBERGESCHOSS
4 x Objekt-00219 | ERDGESCHOSS
4 x Objekt-00219 | KELLERGESCHOSS
4 x Objekt-00220 | KELLERGESCHOSS

# IfcBuildingElementProxy: WC Set 1 25 (9)
In: 1.OBERGESCHOSS
AC_Pset_RenovationAndPhasing - Renovation Status: Existing

# IfcBuildingElementProxy: Wand WC 25 (26)
AC_Pset_RenovationAndPhasing - Renovation Status: Existing
Name | In
7 x Objekt-00219 | ERDGESCHOSS
11 x Objekt-00219 | KELLERGESCHOSS
8 x Objekt-00220 | KELLERGESCHOSS

# IfcBuildingElementProxy: Wandhydrant 3D 25 (4)
AC_Pset_RenovationAndPhasing - Renovation Status: Existing
Name | In
Objekt-00219 | 2.OBERGESCHOSS
Objekt-00219 | 1.OBERGESCHOSS
Objekt-00219 | ERDGESCHOSS
Objekt-00219 | KELLERGESCHOSS

# IfcBuildingElementProxy: Waschbecken 01 25 (50)
AC_Pset_RenovationAndPhasing - Renovation Status: Existing
Name | In
12 x Objekt-00222 | 1.OBERGESCHOSS
16 x Objekt-00219 | ERDGESCHOSS
8 x Objekt-00219 | KELLERGESCHOSS
14 x Objekt-00220 | KELLERGESCHOSS

# IfcBuildingElementProxy: Waschbecken 2 25, Objekt-00219
In: KELLERGESCHOSS
AC_Pset_RenovationAndPhasing - Renovation Status: Existing

# IfcBuildingElementProxy: quickArch Kreuzgratgewölbe_1.0 (5)
AC_Pset_RenovationAndPhasing - Renovation Status: Existing
Name | In
2 x Objekt-00221 | 1.OBERGESCHOSS
3 x Objekt-00221 | ERDGESCHOSS

# IfcColumn: 05_ALLGEMEIN - TRAGENDE BAUTEILE 100 x 100 (3)
In: ERDGESCHOSS
Type - ElementType: PILASTER; PredefinedType: USERDEFINED
Classification: 333 Außenstützen (Classification DIN 267:2018-12); Pfeiler (ARCHICAD Klassifizierung); Material: 05_ALLGEMEIN - TRAGENDE BAUTEILE
Pset_ColumnCommon - Slope: 90 deg; LoadBearing: yes; Reference: 05_ALLGEMEIN - TRAGENDE BAUTEILE 100 x 100
AC_Pset_RenovationAndPhasing - Renovation Status: Existing

# IfcColumn: 05_ALLGEMEIN - TRAGENDE BAUTEILE 1085 x 169, Stütze-009
In: ERDGESCHOSS
Type - ElementType: PILASTER; PredefinedType: USERDEFINED
Classification: 333 Außenstützen (Classification DIN 267:2018-12); Pfeiler (ARCHICAD Klassifizierung); Material: 05_ALLGEMEIN - TRAGENDE BAUTEILE
Pset_ColumnCommon - Slope: 90 deg; LoadBearing: yes; Reference: 05_ALLGEMEIN - TRAGENDE BAUTEILE 1085 x 169
AC_Pset_RenovationAndPhasing - Renovation Status: Existing

# IfcColumn: 05_ALLGEMEIN - TRAGENDE BAUTEILE 150 x 125 (6)
Type - ElementType: PILASTER; PredefinedType: USERDEFINED
Classification: 333 Außenstützen (Classification DIN 267:2018-12); Pfeiler (ARCHICAD Klassifizierung); Material: 05_ALLGEMEIN - TRAGENDE BAUTEILE
Pset_ColumnCommon - Slope: 90 deg; LoadBearing: yes; Reference: 05_ALLGEMEIN - TRAGENDE BAUTEILE 150 x 125
AC_Pset_RenovationAndPhasing - Renovation Status: Existing
Name | In
Stütze-008 | SPITZBODEN
5 x Stütze-008 | DACHGESCHOSS

# IfcColumn: 05_ALLGEMEIN - TRAGENDE BAUTEILE 150 x 150 (4)
In: 2.OBERGESCHOSS
Type - PredefinedType: COLUMN
Classification: 333 Außenstützen (Classification DIN 267:2018-12); Stütze (ARCHICAD Klassifizierung); Material: 05_ALLGEMEIN - TRAGENDE BAUTEILE
Pset_ColumnCommon - Slope: 90 deg; LoadBearing: yes; Reference: 05_ALLGEMEIN - TRAGENDE BAUTEILE 150 x 150
AC_Pset_RenovationAndPhasing - Renovation Status: Existing

# IfcColumn: 05_ALLGEMEIN - TRAGENDE BAUTEILE 155 x 155 (4)
In: DACHGESCHOSS
Type - ElementType: PILASTER; PredefinedType: USERDEFINED
Classification: 333 Außenstützen (Classification DIN 267:2018-12); Pfeiler (ARCHICAD Klassifizierung); Material: 05_ALLGEMEIN - TRAGENDE BAUTEILE
Pset_ColumnCommon - Slope: 90 deg; LoadBearing: yes; Reference: 05_ALLGEMEIN - TRAGENDE BAUTEILE 155 x 155
AC_Pset_RenovationAndPhasing - Renovation Status: Existing

# IfcColumn: 05_ALLGEMEIN - TRAGENDE BAUTEILE 160 x 125 (4)
In: DACHGESCHOSS
Type - ElementType: PILASTER; PredefinedType: USERDEFINED
Classification: 333 Außenstützen (Classification DIN 267:2018-12); Pfeiler (ARCHICAD Klassifizierung); Material: 05_ALLGEMEIN - TRAGENDE BAUTEILE
Pset_ColumnCommon - Slope: 90 deg; LoadBearing: yes; Reference: 05_ALLGEMEIN - TRAGENDE BAUTEILE 160 x 125
AC_Pset_RenovationAndPhasing - Renovation Status: Existing

# IfcColumn: 05_ALLGEMEIN - TRAGENDE BAUTEILE 200 x 200 (2)
In: KELLERGESCHOSS
Type - PredefinedType: COLUMN
Classification: 333 Außenstützen (Classification DIN 267:2018-12); Stütze (ARCHICAD Klassifizierung); Material: 05_ALLGEMEIN - TRAGENDE BAUTEILE
Pset_ColumnCommon - Slope: 90 deg; LoadBearing: yes; Reference: 05_ALLGEMEIN - TRAGENDE BAUTEILE 200 x 200
AC_Pset_RenovationAndPhasing - Renovation Status: Existing

# IfcColumn: 05_ALLGEMEIN - TRAGENDE BAUTEILE 30 x 75 (25)
In: DACHGESCHOSS
Type - ElementType: PILASTER; PredefinedType: USERDEFINED
Classification: 333 Außenstützen (Classification DIN 267:2018-12); Pfeiler (ARCHICAD Klassifizierung); Material: 05_ALLGEMEIN - TRAGENDE BAUTEILE
Pset_ColumnCommon - Slope: 88.441 deg; LoadBearing: yes; Reference: 05_ALLGEMEIN - TRAGENDE BAUTEILE 30 x 75
AC_Pset_RenovationAndPhasing - Renovation Status: Existing

# IfcColumn: 05_ALLGEMEIN - TRAGENDE BAUTEILE 391 x 156, Stütze-010
In: 1.OBERGESCHOSS
Type - ElementType: PILASTER; PredefinedType: USERDEFINED
Classification: 333 Außenstützen (Classification DIN 267:2018-12); Pfeiler (ARCHICAD Klassifizierung); Material: 05_ALLGEMEIN - TRAGENDE BAUTEILE
Pset_ColumnCommon - Slope: 90 deg; LoadBearing: yes; Reference: 05_ALLGEMEIN - TRAGENDE BAUTEILE 391 x 156
AC_Pset_RenovationAndPhasing - Renovation Status: Existing

# IfcColumn: 05_ALLGEMEIN - TRAGENDE BAUTEILE 40 x 40, Stütze-008
In: KELLERGESCHOSS
Type - PredefinedType: COLUMN
Classification: 333 Außenstützen (Classification DIN 267:2018-12); Stütze (ARCHICAD Klassifizierung); Material: 05_ALLGEMEIN - TRAGENDE BAUTEILE
Pset_ColumnCommon - Slope: 90 deg; LoadBearing: yes; Reference: 05_ALLGEMEIN - TRAGENDE BAUTEILE 40 x 40
AC_Pset_RenovationAndPhasing - Renovation Status: Existing

# IfcColumn: 05_ALLGEMEIN - TRAGENDE BAUTEILE 425 x 425, Stütze-008
In: KELLERGESCHOSS
Type - PredefinedType: COLUMN
Classification: 333 Außenstützen (Classification DIN 267:2018-12); Stütze (ARCHICAD Klassifizierung); Material: 05_ALLGEMEIN - TRAGENDE BAUTEILE
Pset_ColumnCommon - Slope: 90 deg; LoadBearing: yes; Reference: 05_ALLGEMEIN - TRAGENDE BAUTEILE 425 x 425
AC_Pset_RenovationAndPhasing - Renovation Status: Existing

# IfcColumn: 05_ALLGEMEIN - TRAGENDE BAUTEILE 431 x 422, Stütze-008
In: DACHGESCHOSS
Type - ElementType: PILASTER; PredefinedType: USERDEFINED
Classification: 333 Außenstützen (Classification DIN 267:2018-12); Pfeiler (ARCHICAD Klassifizierung); Material: 05_ALLGEMEIN - TRAGENDE BAUTEILE
Pset_ColumnCommon - Slope: 90 deg; LoadBearing: yes; Reference: 05_ALLGEMEIN - TRAGENDE BAUTEILE 431 x 422
AC_Pset_RenovationAndPhasing - Renovation Status: Existing

# IfcColumn: 05_ALLGEMEIN - TRAGENDE BAUTEILE 463 x 291, Stütze-009
In: KELLERGESCHOSS
Type - ElementType: PILASTER; PredefinedType: USERDEFINED
Classification: 333 Außenstützen (Classification DIN 267:2018-12); Pfeiler (ARCHICAD Klassifizierung); Material: 05_ALLGEMEIN - TRAGENDE BAUTEILE
Pset_ColumnCommon - Slope: 90 deg; LoadBearing: yes; Reference: 05_ALLGEMEIN - TRAGENDE BAUTEILE 463 x 291
AC_Pset_RenovationAndPhasing - Renovation Status: Existing

# IfcColumn: 05_ALLGEMEIN - TRAGENDE BAUTEILE 490 x 490 (3)
In: KELLERGESCHOSS
Type - ElementType: PILASTER; PredefinedType: USERDEFINED
Classification: 333 Außenstützen (Classification DIN 267:2018-12); Pfeiler (ARCHICAD Klassifizierung); Material: 05_ALLGEMEIN - TRAGENDE BAUTEILE
Pset_ColumnCommon - Slope: 90 deg; LoadBearing: yes; Reference: 05_ALLGEMEIN - TRAGENDE BAUTEILE 490 x 490
AC_Pset_RenovationAndPhasing - Renovation Status: Existing

# IfcColumn: 05_ALLGEMEIN - TRAGENDE BAUTEILE 490 x 535 (2)
In: KELLERGESCHOSS
Type - ElementType: PILASTER; PredefinedType: USERDEFINED
Classification: 333 Außenstützen (Classification DIN 267:2018-12); Pfeiler (ARCHICAD Klassifizierung); Material: 05_ALLGEMEIN - TRAGENDE BAUTEILE
Pset_ColumnCommon - Slope: 90 deg; LoadBearing: yes; Reference: 05_ALLGEMEIN - TRAGENDE BAUTEILE 490 x 535
AC_Pset_RenovationAndPhasing - Renovation Status: Existing

# IfcColumn: 05_ALLGEMEIN - TRAGENDE BAUTEILE 645 x 645 (2)
In: ERDGESCHOSS
Type - ElementType: PILASTER; PredefinedType: USERDEFINED
Classification: 333 Außenstützen (Classification DIN 267:2018-12); Pfeiler (ARCHICAD Klassifizierung); Material: 05_ALLGEMEIN - TRAGENDE BAUTEILE
Pset_ColumnCommon - Slope: 90 deg; LoadBearing: yes; Reference: 05_ALLGEMEIN - TRAGENDE BAUTEILE 645 x 645
AC_Pset_RenovationAndPhasing - Renovation Status: Existing

# IfcColumn: 05_ALLGEMEIN - TRAGENDE BAUTEILE 70 x 50 (100)
In: DACHGESCHOSS
Type - ElementType: PILASTER; PredefinedType: USERDEFINED
Classification: 333 Außenstützen (Classification DIN 267:2018-12); Pfeiler (ARCHICAD Klassifizierung); Material: 05_ALLGEMEIN - TRAGENDE BAUTEILE
Pset_ColumnCommon - Slope: 90 deg; LoadBearing: yes; Reference: 05_ALLGEMEIN - TRAGENDE BAUTEILE 70 x 50
AC_Pset_RenovationAndPhasing - Renovation Status: Existing

# IfcColumn: 05_ALLGEMEIN - TRAGENDE BAUTEILE 75 x 30 (50)
In: DACHGESCHOSS
Type - ElementType: PILASTER; PredefinedType: USERDEFINED
Classification: 333 Außenstützen (Classification DIN 267:2018-12); Pfeiler (ARCHICAD Klassifizierung); Material: 05_ALLGEMEIN - TRAGENDE BAUTEILE
Pset_ColumnCommon - Slope: 90 deg; LoadBearing: yes; Reference: 05_ALLGEMEIN - TRAGENDE BAUTEILE 75 x 30
AC_Pset_RenovationAndPhasing - Renovation Status: Existing

# IfcColumn: 05_ALLGEMEIN - TRAGENDE BAUTEILE 75 x 37 (150)
In: DACHGESCHOSS
Type - ElementType: PILASTER; PredefinedType: USERDEFINED
Classification: 333 Außenstützen (Classification DIN 267:2018-12); Pfeiler (ARCHICAD Klassifizierung); Material: 05_ALLGEMEIN - TRAGENDE BAUTEILE
Pset_ColumnCommon - Slope: 90 deg; LoadBearing: yes; Reference: 05_ALLGEMEIN - TRAGENDE BAUTEILE 75 x 37
AC_Pset_RenovationAndPhasing - Renovation Status: Existing

# IfcColumn: 05_ALLGEMEIN - TRAGENDE BAUTEILE 90 x 50 (3)
Type - PredefinedType: COLUMN
Classification: 333 Außenstützen (Classification DIN 267:2018-12); Stütze (ARCHICAD Klassifizierung); Material: 05_ALLGEMEIN - TRAGENDE BAUTEILE
Pset_ColumnCommon - Slope: 90 deg; LoadBearing: yes; Reference: 05_ALLGEMEIN - TRAGENDE BAUTEILE 90 x 50
AC_Pset_RenovationAndPhasing - Renovation Status: Existing
Name | In
2 x Stütze-008 | ERDGESCHOSS
Stütze-008 | KELLERGESCHOSS

# IfcColumn: 05_ALLGEMEIN - TRAGENDE BAUTEILE D106 (2)
Type - PredefinedType: COLUMN
Classification: 333 Außenstützen (Classification DIN 267:2018-12); Stütze (ARCHICAD Klassifizierung); Material: 05_ALLGEMEIN - TRAGENDE BAUTEILE
Pset_ColumnCommon - Slope: 90 deg; LoadBearing: yes; Reference: 05_ALLGEMEIN - TRAGENDE BAUTEILE D106
AC_Pset_RenovationAndPhasing - Renovation Status: Existing
Name | In
Stütze-008 | ERDGESCHOSS
Stütze-008 | KELLERGESCHOSS

# IfcColumn: 05_ALLGEMEIN - TRAGENDE BAUTEILE D284, Stütze-008
In: 1.OBERGESCHOSS
Type - ElementType: PILASTER; PredefinedType: USERDEFINED
Classification: 333 Außenstützen (Classification DIN 267:2018-12); Pfeiler (ARCHICAD Klassifizierung); Material: 05_ALLGEMEIN - TRAGENDE BAUTEILE
Pset_ColumnCommon - Slope: 90 deg; LoadBearing: yes; Reference: 05_ALLGEMEIN - TRAGENDE BAUTEILE D284
AC_Pset_RenovationAndPhasing - Renovation Status: Existing

# IfcColumn: 05_ALLGEMEIN - TRAGENDE BAUTEILE D69, Stütze-008
In: KELLERGESCHOSS
Type - PredefinedType: COLUMN
Classification: 333 Außenstützen (Classification DIN 267:2018-12); Stütze (ARCHICAD Klassifizierung); Material: 05_ALLGEMEIN - TRAGENDE BAUTEILE
Pset_ColumnCommon - Slope: 90 deg; LoadBearing: yes; Reference: 05_ALLGEMEIN - TRAGENDE BAUTEILE D69
AC_Pset_RenovationAndPhasing - Renovation Status: Existing

# IfcColumn: 05_ALLGEMEIN - TRAGENDE BAUTEILE D82, Stütze-008
In: KELLERGESCHOSS
Type - PredefinedType: COLUMN
Classification: 333 Außenstützen (Classification DIN 267:2018-12); Stütze (ARCHICAD Klassifizierung); Material: 05_ALLGEMEIN - TRAGENDE BAUTEILE
Pset_ColumnCommon - Slope: 90 deg; LoadBearing: yes; Reference: 05_ALLGEMEIN - TRAGENDE BAUTEILE D82
AC_Pset_RenovationAndPhasing - Renovation Status: Existing

# IfcColumn: 05_ALLGEMEIN - TRAGENDE BAUTEILE D86, Stütze-008
In: KELLERGESCHOSS
Type - PredefinedType: COLUMN
Classification: 333 Außenstützen (Classification DIN 267:2018-12); Stütze (ARCHICAD Klassifizierung); Material: 05_ALLGEMEIN - TRAGENDE BAUTEILE
Pset_ColumnCommon - Slope: 90 deg; LoadBearing: yes; Reference: 05_ALLGEMEIN - TRAGENDE BAUTEILE D86
AC_Pset_RenovationAndPhasing - Renovation Status: Existing

# IfcColumn: 05_ALLGEMEIN - TRAGENDE BAUTEILE D96, Stütze-008
In: KELLERGESCHOSS
Type - PredefinedType: COLUMN
Classification: 333 Außenstützen (Classification DIN 267:2018-12); Stütze (ARCHICAD Klassifizierung); Material: 05_ALLGEMEIN - TRAGENDE BAUTEILE
Pset_ColumnCommon - Slope: 90 deg; LoadBearing: yes; Reference: 05_ALLGEMEIN - TRAGENDE BAUTEILE D96
AC_Pset_RenovationAndPhasing - Renovation Status: Existing

# IfcColumn: 43_Gipskarton 258 x 270, Stütze-010
In: 2.OBERGESCHOSS
Type - ElementType: PILASTER; PredefinedType: USERDEFINED
Classification: 333 Außenstützen (Classification DIN 267:2018-12); Pfeiler (ARCHICAD Klassifizierung); Material: 43_Gipskarton
Pset_ColumnCommon - Slope: 90 deg; LoadBearing: yes; Reference: 43_Gipskarton 258 x 270
AC_Pset_RenovationAndPhasing - Renovation Status: Existing

# IfcColumn: 43_Gipskarton 261 x 280 (2)
In: 2.OBERGESCHOSS
Type - ElementType: PILASTER; PredefinedType: USERDEFINED
Classification: 333 Außenstützen (Classification DIN 267:2018-12); Pfeiler (ARCHICAD Klassifizierung); Material: 43_Gipskarton
Pset_ColumnCommon - Slope: 90 deg; LoadBearing: yes; Reference: 43_Gipskarton 261 x 280
AC_Pset_RenovationAndPhasing - Renovation Status: Existing

# IfcColumn: 43_Gipskarton 270 x 270, Stütze-010
In: 2.OBERGESCHOSS
Type - ElementType: PILASTER; PredefinedType: USERDEFINED
Classification: 333 Außenstützen (Classification DIN 267:2018-12); Pfeiler (ARCHICAD Klassifizierung); Material: 43_Gipskarton
Pset_ColumnCommon - Slope: 90 deg; LoadBearing: yes; Reference: 43_Gipskarton 270 x 270
AC_Pset_RenovationAndPhasing - Renovation Status: Existing

# IfcColumn: 43_Gipskarton 274 x 337, Stütze-010
In: 2.OBERGESCHOSS
Type - ElementType: PILASTER; PredefinedType: USERDEFINED
Classification: 333 Außenstützen (Classification DIN 267:2018-12); Pfeiler (ARCHICAD Klassifizierung); Material: 43_Gipskarton
Pset_ColumnCommon - Slope: 90 deg; LoadBearing: yes; Reference: 43_Gipskarton 274 x 337
AC_Pset_RenovationAndPhasing - Renovation Status: Existing

# IfcColumn: 43_Gipskarton 280 x 270, Stütze-010
In: 2.OBERGESCHOSS
Type - ElementType: PILASTER; PredefinedType: USERDEFINED
Classification: 333 Außenstützen (Classification DIN 267:2018-12); Pfeiler (ARCHICAD Klassifizierung); Material: 43_Gipskarton
Pset_ColumnCommon - Slope: 90 deg; LoadBearing: yes; Reference: 43_Gipskarton 280 x 270
AC_Pset_RenovationAndPhasing - Renovation Status: Existing

# IfcColumn: 43_Gipskarton 280 x 280 (2)
In: 2.OBERGESCHOSS
Type - ElementType: PILASTER; PredefinedType: USERDEFINED
Classification: 333 Außenstützen (Classification DIN 267:2018-12); Pfeiler (ARCHICAD Klassifizierung); Material: 43_Gipskarton
Pset_ColumnCommon - Slope: 90 deg; LoadBearing: yes; Reference: 43_Gipskarton 280 x 280
AC_Pset_RenovationAndPhasing - Renovation Status: Existing

# IfcColumn: 43_Gipskarton 86 x 100, Stütze-008
In: KELLERGESCHOSS
Type - ElementType: PILASTER; PredefinedType: USERDEFINED
Classification: 333 Außenstützen (Classification DIN 267:2018-12); Pfeiler (ARCHICAD Klassifizierung); Material: 43_Gipskarton
Pset_ColumnCommon - Slope: 90 deg; LoadBearing: yes; Reference: 43_Gipskarton 86 x 100
AC_Pset_RenovationAndPhasing - Renovation Status: Existing

# IfcColumn: 47_Holz, Bauholz 135 x 135 (2)
In: DACHGESCHOSS
Type - ElementType: PILASTER; PredefinedType: USERDEFINED
Classification: 333 Außenstützen (Classification DIN 267:2018-12); Pfeiler (ARCHICAD Klassifizierung); Material: 47_Holz, Bauholz
Pset_ColumnCommon - Slope: 90 deg; LoadBearing: yes; Reference: 47_Holz, Bauholz 135 x 135
AC_Pset_RenovationAndPhasing - Renovation Status: Existing

# IfcColumn: 56_Metall, Stahl verzinkt D219, Stütze-008
In: KELLERGESCHOSS
Type - PredefinedType: COLUMN
Classification: 333 Außenstützen (Classification DIN 267:2018-12); Stütze (ARCHICAD Klassifizierung)
Pset_ColumnCommon - Slope: 90 deg; LoadBearing: yes; Reference: 56_Metall, Stahl verzinkt D219
AC_Pset_RenovationAndPhasing - Renovation Status: Existing

# IfcColumn: 56_Metall, Stahl verzinkt D228, Stütze-008
In: KELLERGESCHOSS
Type - PredefinedType: COLUMN
Classification: 333 Außenstützen (Classification DIN 267:2018-12); Stütze (ARCHICAD Klassifizierung)
Pset_ColumnCommon - Slope: 90 deg; LoadBearing: yes; Reference: 56_Metall, Stahl verzinkt D228
AC_Pset_RenovationAndPhasing - Renovation Status: Existing

# IfcColumn: 56_Metall, Stahl verzinkt D229, Stütze-008
In: KELLERGESCHOSS
Type - PredefinedType: COLUMN
Classification: 333 Außenstützen (Classification DIN 267:2018-12); Stütze (ARCHICAD Klassifizierung)
Pset_ColumnCommon - Slope: 90 deg; LoadBearing: yes; Reference: 56_Metall, Stahl verzinkt D229
AC_Pset_RenovationAndPhasing - Renovation Status: Existing

# IfcColumn: 56_Metall, Stahl verzinkt D231 (4)
In: KELLERGESCHOSS
Type - PredefinedType: COLUMN
Classification: 333 Außenstützen (Classification DIN 267:2018-12); Stütze (ARCHICAD Klassifizierung)
Pset_ColumnCommon - Slope: 90 deg; LoadBearing: yes; Reference: 56_Metall, Stahl verzinkt D231
AC_Pset_RenovationAndPhasing - Renovation Status: Existing

# IfcColumn: 56_Metall, Stahl verzinkt D232 (2)
In: KELLERGESCHOSS
Type - PredefinedType: COLUMN
Classification: 333 Außenstützen (Classification DIN 267:2018-12); Stütze (ARCHICAD Klassifizierung)
Pset_ColumnCommon - Slope: 90 deg; LoadBearing: yes; Reference: 56_Metall, Stahl verzinkt D232
AC_Pset_RenovationAndPhasing - Renovation Status: Existing

# IfcColumn: 56_Metall, Stahl verzinkt D233, Stütze-008
In: KELLERGESCHOSS
Type - PredefinedType: COLUMN
Classification: 333 Außenstützen (Classification DIN 267:2018-12); Stütze (ARCHICAD Klassifizierung)
Pset_ColumnCommon - Slope: 90 deg; LoadBearing: yes; Reference: 56_Metall, Stahl verzinkt D233
AC_Pset_RenovationAndPhasing - Renovation Status: Existing

# IfcColumn: 56_Metall, Stahl verzinkt D234, Stütze-008
In: KELLERGESCHOSS
Type - PredefinedType: COLUMN
Classification: 333 Außenstützen (Classification DIN 267:2018-12); Stütze (ARCHICAD Klassifizierung)
Pset_ColumnCommon - Slope: 90 deg; LoadBearing: yes; Reference: 56_Metall, Stahl verzinkt D234
AC_Pset_RenovationAndPhasing - Renovation Status: Existing

# IfcColumn: 56_Metall, Stahl verzinkt D235, Stütze-008
In: KELLERGESCHOSS
Type - PredefinedType: COLUMN
Classification: 333 Außenstützen (Classification DIN 267:2018-12); Stütze (ARCHICAD Klassifizierung)
Pset_ColumnCommon - Slope: 90 deg; LoadBearing: yes; Reference: 56_Metall, Stahl verzinkt D235
AC_Pset_RenovationAndPhasing - Renovation Status: Existing

# IfcColumn: 56_Metall, Stahl verzinkt D37, Stütze-008
In: ERDGESCHOSS
Type - PredefinedType: COLUMN
Classification: 333 Außenstützen (Classification DIN 267:2018-12); Stütze (ARCHICAD Klassifizierung)
Pset_ColumnCommon - Slope: 90 deg; LoadBearing: yes; Reference: 56_Metall, Stahl verzinkt D37
AC_Pset_RenovationAndPhasing - Renovation Status: Existing

# IfcColumn: 56_Metall, Stahl verzinkt D60, Stütze-008
In: KELLERGESCHOSS
Type - PredefinedType: COLUMN
Classification: 333 Außenstützen (Classification DIN 267:2018-12); Stütze (ARCHICAD Klassifizierung); Material: 56_Metall, Stahl verzinkt
Pset_ColumnCommon - Slope: 90 deg; LoadBearing: yes; Reference: 56_Metall, Stahl verzinkt D60
AC_Pset_RenovationAndPhasing - Renovation Status: Existing

# IfcColumn: 56_Metall, Stahl verzinkt D70 (3)
Type - PredefinedType: COLUMN
Classification: 333 Außenstützen (Classification DIN 267:2018-12); Stütze (ARCHICAD Klassifizierung)
Pset_ColumnCommon - Slope: 90 deg; LoadBearing: yes; Reference: 56_Metall, Stahl verzinkt D70
AC_Pset_RenovationAndPhasing - Renovation Status: Existing
Name | In
Stütze-008 | 2.OBERGESCHOSS
Stütze-008 | 1.OBERGESCHOSS
Stütze-008 | ERDGESCHOSS

# IfcColumn: HEB240 240 x 240 (2)
In: ERDGESCHOSS
Type - PredefinedType: COLUMN
Classification: 333 Außenstützen (Classification DIN 267:2018-12); Stütze (ARCHICAD Klassifizierung); Material: Stahl verzinkt
Pset_ColumnCommon - Slope: 90 deg; LoadBearing: yes; Reference: HEB240 240 x 240
AC_Pset_RenovationAndPhasing - Renovation Status: Existing

# IfcColumn: Verschiedene Strukturen - 2 Segmente - 800 x 400 x 446 (188+258), Stütze-012
In: ERDGESCHOSS
Type - ElementType: PILASTER; PredefinedType: USERDEFINED
Classification: 333 Außenstützen (Classification DIN 267:2018-12); Pfeiler (ARCHICAD Klassifizierung)
Pset_ColumnCommon - Slope: 90 deg; LoadBearing: yes; Reference: Verschiedene Strukturen - 2 Segmente - 800 x 400 x 446 (188+258)
AC_Pset_RenovationAndPhasing - Renovation Status: Existing

# IfcCovering: 02_ALLGEMEIN - BEKLEIDUNG 40 (4)
In: ERDGESCHOSS
Type - PredefinedType: CEILING
Classification: Abgehängte Decke / Deckenbekleidung (ARCHICAD Klassifizierung); 354 Deckenbekleidungen (Classification DIN 267:2018-12); Material: 02_ALLGEMEIN - BEKLEIDUNG
Pset_SlabCommon - ThermalTransmittance: 0
Pset_CoveringCommon - Material: 02_ALLGEMEIN - BEKLEIDUNG; TotalThickness: 0.04 m
AC_Pset_RenovationAndPhasing - Renovation Status: Existing
Name
Dach-001
Dach-002
Dach-003
Dach-004

# IfcCovering: 05_ALLGEMEIN - TRAGENDE BAUTEILE 40 (40)
Type - PredefinedType: CEILING
Classification: Abgehängte Decke / Deckenbekleidung (ARCHICAD Klassifizierung); 354 Deckenbekleidungen (Classification DIN 267:2018-12); Material: 05_ALLGEMEIN - TRAGENDE BAUTEILE
Pset_SlabCommon - ThermalTransmittance: 0
Pset_CoveringCommon - Material: 05_ALLGEMEIN - TRAGENDE BAUTEILE; TotalThickness: 0.04 m
AC_Pset_RenovationAndPhasing - Renovation Status: Existing
Name | In
Dach-001 | 2.OBERGESCHOSS
Dach-004 | 2.OBERGESCHOSS
Dach-005 | 2.OBERGESCHOSS
Dach-006 | 2.OBERGESCHOSS
Dach-007 | 2.OBERGESCHOSS
Dach-008 | 2.OBERGESCHOSS
Dach-009 | 2.OBERGESCHOSS
Dach-010 | 2.OBERGESCHOSS
Dach-012 | 2.OBERGESCHOSS
Dach-013 | 2.OBERGESCHOSS
6 x Dach-014 | 2.OBERGESCHOSS
2 x Dach-015 | 2.OBERGESCHOSS
3 x Dach-016 | 2.OBERGESCHOSS
Dach-018 | 2.OBERGESCHOSS
Dach-019 | 2.OBERGESCHOSS
Dach-020 | 2.OBERGESCHOSS
Dach-021 | 2.OBERGESCHOSS
Dach-022 | 2.OBERGESCHOSS
Dach-023 | 2.OBERGESCHOSS
3 x Dach-024 | 2.OBERGESCHOSS
Dach-025 | 2.OBERGESCHOSS
Dach-026 | 2.OBERGESCHOSS
Dach-027 | 2.OBERGESCHOSS
Dach-028 | 2.OBERGESCHOSS
Dach-001 | KELLERGESCHOSS
2 x Dach-002 | KELLERGESCHOSS
Dach-003 | KELLERGESCHOSS
Dach-004 | KELLERGESCHOSS
Dach-005 | KELLERGESCHOSS

# IfcCovering: 29_Dach, Dachziegel rot 213 (2)
In: DACHGESCHOSS
Type - PredefinedType: CEILING
Classification: Abgehängte Decke / Deckenbekleidung (ARCHICAD Klassifizierung); 354 Deckenbekleidungen (Classification DIN 267:2018-12); Material: 29_Dach, Dachziegel rot
Pset_SlabCommon - ThermalTransmittance: 0
Pset_CoveringCommon - Material: 29_Dach, Dachziegel rot
AC_Pset_RenovationAndPhasing - Renovation Status: Existing
Name | TotalThickness (m)
Dach-002 | 0.213198
Dach-003 | 0.213184

# IfcCovering: 29_Dach, Dachziegel rot 80, Dach-014
In: DACHGESCHOSS
Type - PredefinedType: CEILING
Classification: Abgehängte Decke / Deckenbekleidung (ARCHICAD Klassifizierung); 354 Deckenbekleidungen (Classification DIN 267:2018-12); Material: 29_Dach, Dachziegel rot
Pset_SlabCommon - ThermalTransmittance: 0
Pset_CoveringCommon - Material: 29_Dach, Dachziegel rot; TotalThickness: 0.08 m
AC_Pset_RenovationAndPhasing - Renovation Status: Existing

# IfcDoor: Blockrahmentür 1-Fl 25 (71)
Type - OperationType: SINGLE_SWING_LEFT; ParameterTakesPrecedence: no; Sizeable: no
Classification: Tür / Tor (ARCHICAD Klassifizierung)
Pset_DoorCommon - IsExternal: yes
AC_Pset_RenovationAndPhasing - Renovation Status: Existing
Name | In | OverallHeight (m) | OverallWidth (m)
Tür-022 | 2.OBERGESCHOSS | 2.20892 | 0.982048
Tür-023 | 2.OBERGESCHOSS | 0.490811 | 0.493347
Tür-023 | 2.OBERGESCHOSS | 0.496632 | 0.396367
Tür-022 | 2.OBERGESCHOSS | 2.13301 | 1.02244
Tür-022 | 2.OBERGESCHOSS | 2.14135 | 1.09811
Tür-022 | 2.OBERGESCHOSS | 2.09163 | 0.82763
Tür-023 | 2.OBERGESCHOSS | 2.07465 | 1.01904
Tür-022 | 2.OBERGESCHOSS | 2.03629 | 0.891789
Tür-022 | 2.OBERGESCHOSS | 2.05518 | 0.963796
Tür-022 | 2.OBERGESCHOSS | 0.39965 | 0.397597
Tür-022 | 2.OBERGESCHOSS | 2.01692 | 0.938024
Tür-025 | 2.OBERGESCHOSS | 1.97065 | 0.997053
Tür-022 | 2.OBERGESCHOSS | 2.20759 | 1.01119
Tür-022 | 1.OBERGESCHOSS | 2.25056 | 1.02379
3 x Tür-022 | 1.OBERGESCHOSS | 2.33387 | 1.23908
Tür-024 | 1.OBERGESCHOSS | 2.0866 | 0.840428
Tür-025 | 1.OBERGESCHOSS | 2.0866 | 0.840428
Tür-022 | 1.OBERGESCHOSS | 2.01328 | 0.833369
2 x Tür-022 | 1.OBERGESCHOSS | 2.30725 | 1.24465
Tür-022 | 1.OBERGESCHOSS | 2.10545 | 0.973792
Tür-022 | 1.OBERGESCHOSS | 1.96287 | 0.705864
Tür-022 | 1.OBERGESCHOSS | 2.09792 | 0.963064
Tür-022 | 1.OBERGESCHOSS | 0.392939 | 0.402311
Tür-022 | 1.OBERGESCHOSS | 0.390717 | 0.403776
Tür-022 | 1.OBERGESCHOSS | 0.489548 | 0.492795
Tür-022 | 1.OBERGESCHOSS | 2.18412 | 0.772754
Tür-022 | 1.OBERGESCHOSS | 2.12423 | 1.02825
Tür-022 | ERDGESCHOSS | 2.10018 | 0.952213
Tür-022 | ERDGESCHOSS | 3.01456 | 1.05371 | Pset_DoorCommon - GlazingAreaFraction: 0.661346
Tür-022 | ERDGESCHOSS | 2.10092 | 0.947502
Tür-022 | ERDGESCHOSS | 0.24614 | 0.255161
Tür-022 | ERDGESCHOSS | 0.397411 | 0.397966
Tür-022 | ERDGESCHOSS | 0.407348 | 0.39563
Tür-022 | ERDGESCHOSS | 0.395277 | 0.403952
Brandschutzklappe | ERDGESCHOSS | 0.401117 | 0.402037
Tür-022 | ERDGESCHOSS | 0.399785 | 0.400057
2 x Tür-022 | ERDGESCHOSS | 2.33387 | 1.23908
Tür-022 | ERDGESCHOSS | 2.127 | 1.0219
Tür-022 | ERDGESCHOSS | 2.25056 | 1.00454
Tür-022 | ERDGESCHOSS | 2.11575 | 0.97088
Tür-022 | ERDGESCHOSS | 1.98177 | 0.70831
2 x Tür-022 | ERDGESCHOSS | 2.0866 | 0.840428
Tür-022 | ERDGESCHOSS | 2.00684 | 0.829851
Tür-026 | KELLERGESCHOSS | 2.10129 | 0.994788
Tür-022 | KELLERGESCHOSS | 2.1026 | 0.82067
Tür-022 | KELLERGESCHOSS | 2.12619 | 0.943245
Tür-022 | KELLERGESCHOSS | 2.09894 | 0.945781
Tür-022 | KELLERGESCHOSS | 2.09862 | 0.943903
Tür-022 | KELLERGESCHOSS | 2.10678 | 0.700921
Tür-022 | KELLERGESCHOSS | 2.11289 | 0.811911
Tür-022 | KELLERGESCHOSS | 2.10082 | 0.70574
Tür-023 | KELLERGESCHOSS | 1.97454 | 1.24064
Tür-022 | KELLERGESCHOSS | 2.21408 | 0.976938
3 x Tür-022 | KELLERGESCHOSS | 2.31029 | 1.28444
Tür-022 | KELLERGESCHOSS | 2.0628 | 0.932605
Tür-022 | KELLERGESCHOSS | 2.31029 | 1.18422
Tür-022 | KELLERGESCHOSS | 1.99499 | 0.835464
Tür-022 | KELLERGESCHOSS | 2.30392 | 1.26913
Tür-022 | KELLERGESCHOSS | 1.96468 | 1.00454
Tür-022 | KELLERGESCHOSS | 1.96879 | 0.875596
Tür-022 | KELLERGESCHOSS | 2.07053 | 0.982381
2 x Tür-022 | KELLERGESCHOSS | 2.0866 | 0.840428
Tür-022 | KELLERGESCHOSS | 1.99228 | 0.824257

# IfcDoor: Blockrahmentür 1-Fl 25 (95)
Type - OperationType: SINGLE_SWING_RIGHT; ParameterTakesPrecedence: no; Sizeable: no
Classification: Tür / Tor (ARCHICAD Klassifizierung)
Pset_DoorCommon - IsExternal: yes
AC_Pset_RenovationAndPhasing - Renovation Status: Existing
Name | In | OverallHeight (m) | OverallWidth (m)
Tür-023 | 2.OBERGESCHOSS | 0.490811 | 0.493347
2 x Tür-022 | 2.OBERGESCHOSS | 2.20759 | 1.01119
Tür-023 | 2.OBERGESCHOSS | 2.07465 | 1.01904
Tür-023 | 2.OBERGESCHOSS | 0.588496 | 0.586845
Tür-022 | 2.OBERGESCHOSS | 2.0866 | 1.03448
Tür-023 | 2.OBERGESCHOSS | 2.0866 | 0.840428
Tür-023 | 2.OBERGESCHOSS | 0.697407 | 0.782158
Tür-024 | 2.OBERGESCHOSS | 2.0866 | 0.840428
Tür-025 | 2.OBERGESCHOSS | 2.0866 | 0.840428
Tür-022 | 2.OBERGESCHOSS | 0.489541 | 0.49869
Tür-022 | 2.OBERGESCHOSS | 0.401782 | 0.400161
Tür-022 | 2.OBERGESCHOSS | 2.11332 | 0.838251
Tür-022 | 2.OBERGESCHOSS | 2.04509 | 0.940137
Tür-022 | 2.OBERGESCHOSS | 2.01692 | 0.938024
Tür-022 | 2.OBERGESCHOSS | 0.401113 | 0.396331
Tür-022 | 2.OBERGESCHOSS | 0.483125 | 0.496885
2 x Tür-022 | 1.OBERGESCHOSS | 2.30725 | 1.24465
3 x Tür-022 | 1.OBERGESCHOSS | 2.1069 | 0.965501
Tür-022 | 1.OBERGESCHOSS | 2.0866 | 0.840428
Tür-023 | 1.OBERGESCHOSS | 2.0866 | 0.840428
Tür-022 | 1.OBERGESCHOSS | 1.99643 | 0.83136
Tür-022 | 1.OBERGESCHOSS | 2.07096 | 0.921505
Tür-022 | 1.OBERGESCHOSS | 2.18892 | 1.02647
Tür-022 | 1.OBERGESCHOSS | 0.293011 | 0.301565
Tür-022 | 1.OBERGESCHOSS | 0.396842 | 0.405894
2 x Tür-022 | 1.OBERGESCHOSS | 2.24001 | 1.0399
Tür-022 | 1.OBERGESCHOSS | 2.13579 | 1.01327
Tür-022 | 1.OBERGESCHOSS | 1.96792 | 0.849239
Tür-022 | 1.OBERGESCHOSS | 2.10537 | 0.967373
Tür-022 | 1.OBERGESCHOSS | 0.482893 | 0.488492
Tür-022 | 1.OBERGESCHOSS | 0.391235 | 0.409033
Tür-022 | 1.OBERGESCHOSS | 2.33387 | 1.23908
Tür-022 | 1.OBERGESCHOSS | 0.396233 | 0.393651
Tür-022 | 1.OBERGESCHOSS | 2.18071 | 1.03221
Tür-022 | ERDGESCHOSS | 2.10124 | 0.954691
Tür-022 | ERDGESCHOSS | 0.396051 | 0.39761
Tür-022 | ERDGESCHOSS | 0.247427 | 0.251017
Tür-022 | ERDGESCHOSS | 0.48975 | 0.496701
Tür-022 | ERDGESCHOSS | 0.394103 | 0.403526
Tür-022 | ERDGESCHOSS | 0.399785 | 0.400057
Tür-023 | ERDGESCHOSS | 2.25786 | 1.17439
Tür-022 | ERDGESCHOSS | 2.25056 | 1.00454
Tür-022 | ERDGESCHOSS | 2.22878 | 1.03195
Tür-022 | ERDGESCHOSS | 2.28375 | 1.23908
Tür-022 | ERDGESCHOSS | 2.10389 | 0.966882
3 x Tür-023 | ERDGESCHOSS | 2.25842 | 1.17848
Tür-022 | ERDGESCHOSS | 2.18892 | 1.02647
Tür-022 | ERDGESCHOSS | 2.20315 | 1.02823
Tür-022 | ERDGESCHOSS | 2.127 | 1.0219
Brandschutzklappe | ERDGESCHOSS | 0.406453 | 0.392963
2 x Tür-022 | ERDGESCHOSS | 2.0866 | 0.840428
Tür-022 | ERDGESCHOSS | 1.97475 | 0.832134
Tür-022 | ERDGESCHOSS | 0.300507 | 0.304082
Tür-026 | KELLERGESCHOSS | 2.10129 | 0.994788
Tür-022 | KELLERGESCHOSS | 2.10265 | 0.823325
Tür-022 | KELLERGESCHOSS | 2.09796 | 0.943054
Tür-022 | KELLERGESCHOSS | 2.0934 | 0.946639
Tür-022 | KELLERGESCHOSS | 2.09903 | 0.943147
Tür-022 | KELLERGESCHOSS | 2.09074 | 0.8062
Tür-022 | KELLERGESCHOSS | 0.196508 | 0.147571
Tür-022 | KELLERGESCHOSS | 2.0843 | 0.814085
Tür-022 | KELLERGESCHOSS | 0.194955 | 0.202514
Tür-022 | KELLERGESCHOSS | 2.10341 | 0.823192
Tür-022 | KELLERGESCHOSS | 2.10051 | 0.689557
Tür-022 | KELLERGESCHOSS | 0.194292 | 0.200072
Tür-022 | KELLERGESCHOSS | 0.196641 | 0.202008
Tür-022 | KELLERGESCHOSS | 0.299404 | 0.295993
Tür-022 | KELLERGESCHOSS | 0.294192 | 0.296552
Tür-022 | KELLERGESCHOSS | 0.293476 | 0.306104
Tür-022 | KELLERGESCHOSS | 0.296812 | 0.297565
Tür-022 | KELLERGESCHOSS | 0.295869 | 0.300489
Tür-022 | KELLERGESCHOSS | 2.25921 | 1.25378
2 x Tür-022 | KELLERGESCHOSS | 2.31029 | 1.28444
Tür-022 | KELLERGESCHOSS | 2.06307 | 0.929114
Tür-022 | KELLERGESCHOSS | 1.98261 | 0.994295
Tür-022 | KELLERGESCHOSS | 2.27738 | 1.05454
Tür-022 | KELLERGESCHOSS | 2.22849 | 1.00009
Tür-022 | KELLERGESCHOSS | 2.18767 | 1.03335
Tür-022 | KELLERGESCHOSS | 1.99164 | 0.835564
Tür-022 | KELLERGESCHOSS | 0.291513 | 0.302128
Tür-022 | KELLERGESCHOSS | 2.06882 | 0.978926
2 x Tür-022 | KELLERGESCHOSS | 2.0866 | 0.840428
Tür-022 | KELLERGESCHOSS | 1.95459 | 0.987921
Tür-022 | KELLERGESCHOSS | 1.96495 | 0.732788
Tür-022 | KELLERGESCHOSS | 2.00126 | 0.850612

# IfcDoor: Blockrahmentür 2-Fl 25 (15)
Type - OperationType: DOUBLE_DOOR_SINGLE_SWING; ParameterTakesPrecedence: no; Sizeable: no
Classification: Tür / Tor (ARCHICAD Klassifizierung)
Pset_DoorCommon - IsExternal: yes
AC_Pset_RenovationAndPhasing - Renovation Status: Existing
Name | In | OverallHeight (m) | OverallWidth (m) | GlazingAreaFraction
Tür-023 | 2.OBERGESCHOSS | 2.12637 | 2.37089 | 2.74839
Tür-023 | 2.OBERGESCHOSS | 2.12643 | 2.37089 | 2.74849
Tür-022 | 2.OBERGESCHOSS | 2.12794 | 2.15179
2 x Tür-023 | 1.OBERGESCHOSS | 2.12297 | 2.37089 | 2.74264
Tür-023 | ERDGESCHOSS | 2.38809 | 2.17837
Tür-022 | ERDGESCHOSS | 2.10515 | 2.42481
Tür-023 | ERDGESCHOSS | 2.21285 | 1.26631
Tür-023 | ERDGESCHOSS | 2.12297 | 2.4792 | 2.91842
Tür-023 | ERDGESCHOSS | 2.12297 | 2.37089 | 2.74264
Tür-023 | KELLERGESCHOSS | 2.38809 | 2.17837
Tür-022 | KELLERGESCHOSS | 2.09349 | 2.42481
Tür-023 | KELLERGESCHOSS | 2.13172 | 1.84202 | 1.89445
Tür-023 | KELLERGESCHOSS | 2.53 | 2.62759 | 3.41825
Tür-023 | KELLERGESCHOSS | 2.38809 | 2.38006 | 2.93403

# IfcDoor: Tür Ol 1-Fl 1S 25 (2)
Type - OperationType: SINGLE_SWING_LEFT; ParameterTakesPrecedence: no; Sizeable: no
OverallWidth: 1.49151 m; Classification: Tür / Tor (ARCHICAD Klassifizierung)
Pset_DoorCommon - IsExternal: yes
AC_Pset_RenovationAndPhasing - Renovation Status: Existing
Name | In | OverallHeight (m) | GlazingAreaFraction
Tür-022 | ERDGESCHOSS | 3.01456 | 1.5686
Tür-022 | KELLERGESCHOSS | 2.99866 | 1.56388

# IfcDoor: Tür Ol 1-Fl 1S 25 (3)
Type - OperationType: SINGLE_SWING_RIGHT; ParameterTakesPrecedence: no; Sizeable: no
OverallWidth: 1.49151 m; Classification: Tür / Tor (ARCHICAD Klassifizierung)
Pset_DoorCommon - IsExternal: yes
AC_Pset_RenovationAndPhasing - Renovation Status: Existing
Name | In | OverallHeight (m) | GlazingAreaFraction
2 x Tür-022 | ERDGESCHOSS | 3.01456 | 1.5686
Tür-022 | KELLERGESCHOSS | 2.99866 | 1.56388

# IfcDoor: Tür Ol 1-Fl 25, Tür-022
In: KELLERGESCHOSS
Type - OperationType: SINGLE_SWING_RIGHT; ParameterTakesPrecedence: no; Sizeable: no
OverallHeight: 2.22532 m; OverallWidth: 1.00944 m; Classification: Tür / Tor (ARCHICAD Klassifizierung)
Pset_DoorCommon - GlazingAreaFraction: 1.06487; IsExternal: yes
AC_Pset_RenovationAndPhasing - Renovation Status: Existing

# IfcDoor: Tür Ol 2-Fl 25 (2)
Type - OperationType: DOUBLE_DOOR_SINGLE_SWING; ParameterTakesPrecedence: no; Sizeable: no
OverallHeight: 2.21756 m; OverallWidth: 1.77985 m; Classification: Tür / Tor (ARCHICAD Klassifizierung)
Pset_DoorCommon - IsExternal: yes
AC_Pset_RenovationAndPhasing - Renovation Status: Existing
Name | In
Tür-022 | ERDGESCHOSS
Tür-023 | KELLERGESCHOSS

# IfcDoor: Tür Segm 2-Fl 25 (5)
Type - OperationType: DOUBLE_DOOR_SINGLE_SWING; ParameterTakesPrecedence: no; Sizeable: no
Classification: Tür / Tor (ARCHICAD Klassifizierung)
Pset_DoorCommon - IsExternal: yes
AC_Pset_RenovationAndPhasing - Renovation Status: Existing
Name | In | OverallHeight (m) | OverallWidth (m) | GlazingAreaFraction
Tür-022 | 1.OBERGESCHOSS | 2.87585 | 1.3998 | 1.56573
Tür-022 | ERDGESCHOSS | 2.98658 | 1.78492
Tür-022 | ERDGESCHOSS | 3.3696 | 1.73632 | 0.851111
Tür-022 | KELLERGESCHOSS | 2.98658 | 1.78492
Tür-022 | KELLERGESCHOSS | 3.3696 | 1.73632 | 0.862356

# IfcOpeningElement (533)
Name | In
Dachfenster-003 | DACHGESCHOSS
10 x Dachfenster-002 | DACHGESCHOSS
Fenster-015 | DACHGESCHOSS
67 x Fenster-015 | 2.OBERGESCHOSS
4 x Fenster-016 | 2.OBERGESCHOSS
12 x Tür-023 | 2.OBERGESCHOSS
20 x Tür-022 | 2.OBERGESCHOSS
Tür-024 | 2.OBERGESCHOSS
2 x Tür-025 | 2.OBERGESCHOSS
Fenster-025 | 2.OBERGESCHOSS
65 x Fenster-015 | 1.OBERGESCHOSS
4 x Fenster-016 | 1.OBERGESCHOSS
10 x Tür-023 | 1.OBERGESCHOSS
38 x Tür-022 | 1.OBERGESCHOSS
2 x Fenster-017 | 1.OBERGESCHOSS
3 x Tür-024 | 1.OBERGESCHOSS
Tür-025 | 1.OBERGESCHOSS
66 x Fenster-015 | ERDGESCHOSS
8 x Tür-023 | ERDGESCHOSS
7 x Fenster-021 | ERDGESCHOSS
Fenster-020 | ERDGESCHOSS
45 x Tür-022 | ERDGESCHOSS
Fenster-022 | ERDGESCHOSS
DD-010 | ERDGESCHOSS | AC_Pset_RenovationAndPhasing - Renovation Status: Existing
2 x Brandschutzklappe | ERDGESCHOSS
5 x Fenster-016 | ERDGESCHOSS
2 x Fenster-017 | ERDGESCHOSS
54 x Fenster-015 | KELLERGESCHOSS
2 x Tür-026 | KELLERGESCHOSS
6 x Fenster-016 | KELLERGESCHOSS
7 x Fenster-014 | KELLERGESCHOSS
7 x Tür-023 | KELLERGESCHOSS
67 x Tür-022 | KELLERGESCHOSS
3 x Fenster-024 | KELLERGESCHOSS
3 x Fenster-025 | KELLERGESCHOSS
DD-002 | KELLERGESCHOSS | AC_Pset_RenovationAndPhasing - Renovation Status: Existing
Tür-024 | KELLERGESCHOSS
Fenster-019 | KELLERGESCHOSS
Fenster-018 | KELLERGESCHOSS

# IfcOpeningElement: RECESS (5)
Classification: Nische (ARCHICAD Klassifizierung)
AC_Pset_RenovationAndPhasing - Renovation Status: Existing
Name | In
2 x DD-015 | DACHGESCHOSS
DD-009 | ERDGESCHOSS
DD-010 | ERDGESCHOSS
DD-011 | ERDGESCHOSS

# IfcSlab: 01_ALLGEMEIN - BAUTEIL 105, Belag-005
In: ERDGESCHOSS
Classification: 351 Deckenkonstruktionen (Classification DIN 267:2018-12); Decke (ARCHICAD Klassifizierung); Material: 01_ALLGEMEIN - BAUTEIL 0.105 m
AC_Pset_RenovationAndPhasing - Renovation Status: Existing
Pset_SlabCommon - LoadBearing: no; IsExternal: no

# IfcSlab: 01_ALLGEMEIN - BAUTEIL 116, Belag-005
In: 2.OBERGESCHOSS
Classification: 351 Deckenkonstruktionen (Classification DIN 267:2018-12); Decke (ARCHICAD Klassifizierung); Material: 01_ALLGEMEIN - BAUTEIL 0.11609 m
AC_Pset_RenovationAndPhasing - Renovation Status: Existing
Pset_SlabCommon - LoadBearing: no; IsExternal: no

# IfcSlab: 01_ALLGEMEIN - BAUTEIL 120 (7)
In: KELLERGESCHOSS
Classification: 351 Deckenkonstruktionen (Classification DIN 267:2018-12); Decke (ARCHICAD Klassifizierung); Material: 01_ALLGEMEIN - BAUTEIL 0.12 m
AC_Pset_RenovationAndPhasing - Renovation Status: Existing
Pset_SlabCommon - LoadBearing: no; IsExternal: no
Name
6 x Belag-015
Belag-016

# IfcSlab: 01_ALLGEMEIN - BAUTEIL 129, Belag-004
In: 2.OBERGESCHOSS
Classification: 351 Deckenkonstruktionen (Classification DIN 267:2018-12); Decke (ARCHICAD Klassifizierung); Material: 01_ALLGEMEIN - BAUTEIL 0.128885 m
AC_Pset_RenovationAndPhasing - Renovation Status: Existing
Pset_SlabCommon - LoadBearing: no; IsExternal: no

# IfcSlab: 01_ALLGEMEIN - BAUTEIL 132, Belag-004
In: 2.OBERGESCHOSS
Classification: 351 Deckenkonstruktionen (Classification DIN 267:2018-12); Decke (ARCHICAD Klassifizierung); Material: 01_ALLGEMEIN - BAUTEIL 0.132429 m
AC_Pset_RenovationAndPhasing - Renovation Status: Existing
Pset_SlabCommon - LoadBearing: no; IsExternal: no

# IfcSlab: 01_ALLGEMEIN - BAUTEIL 142, Belag-004
In: 2.OBERGESCHOSS
Classification: 351 Deckenkonstruktionen (Classification DIN 267:2018-12); Decke (ARCHICAD Klassifizierung); Material: 01_ALLGEMEIN - BAUTEIL 0.142429 m
AC_Pset_RenovationAndPhasing - Renovation Status: Existing
Pset_SlabCommon - LoadBearing: no; IsExternal: no

# IfcSlab: 01_ALLGEMEIN - BAUTEIL 145, Belag-004
In: 2.OBERGESCHOSS
Classification: 351 Deckenkonstruktionen (Classification DIN 267:2018-12); Decke (ARCHICAD Klassifizierung); Material: 01_ALLGEMEIN - BAUTEIL 0.145335 m
AC_Pset_RenovationAndPhasing - Renovation Status: Existing
Pset_SlabCommon - LoadBearing: no; IsExternal: no

# IfcSlab: 01_ALLGEMEIN - BAUTEIL 160, Belag-014
In: KELLERGESCHOSS
Classification: 351 Deckenkonstruktionen (Classification DIN 267:2018-12); Decke (ARCHICAD Klassifizierung); Material: 01_ALLGEMEIN - BAUTEIL 0.16 m
AC_Pset_RenovationAndPhasing - Renovation Status: Existing
Pset_SlabCommon - LoadBearing: no; IsExternal: no

# IfcSlab: 01_ALLGEMEIN - BAUTEIL 162 (2)
In: 2.OBERGESCHOSS
Classification: 351 Deckenkonstruktionen (Classification DIN 267:2018-12); Decke (ARCHICAD Klassifizierung); Material: 01_ALLGEMEIN - BAUTEIL 0.162429 m
AC_Pset_RenovationAndPhasing - Renovation Status: Existing
Pset_SlabCommon - LoadBearing: no; IsExternal: no

# IfcSlab: 01_ALLGEMEIN - BAUTEIL 202, Belag-004
In: 2.OBERGESCHOSS
Classification: 351 Deckenkonstruktionen (Classification DIN 267:2018-12); Decke (ARCHICAD Klassifizierung); Material: 01_ALLGEMEIN - BAUTEIL 0.202429 m
AC_Pset_RenovationAndPhasing - Renovation Status: Existing
Pset_SlabCommon - LoadBearing: no; IsExternal: no

# IfcSlab: 01_ALLGEMEIN - BAUTEIL 220, Belag-004
In: ERDGESCHOSS
Classification: 351 Deckenkonstruktionen (Classification DIN 267:2018-12); Decke (ARCHICAD Klassifizierung); Material: 01_ALLGEMEIN - BAUTEIL 0.22 m
AC_Pset_RenovationAndPhasing - Renovation Status: Existing
Pset_SlabCommon - LoadBearing: no; IsExternal: no

# IfcSlab: 01_ALLGEMEIN - BAUTEIL 270, Belag-006
In: 2.OBERGESCHOSS
Classification: 351 Deckenkonstruktionen (Classification DIN 267:2018-12); Decke (ARCHICAD Klassifizierung); Material: 01_ALLGEMEIN - BAUTEIL 0.27 m
AC_Pset_RenovationAndPhasing - Renovation Status: Existing
Pset_SlabCommon - LoadBearing: no; IsExternal: no

# IfcSlab: 01_ALLGEMEIN - BAUTEIL 280, Belag-006
In: 2.OBERGESCHOSS
Classification: 351 Deckenkonstruktionen (Classification DIN 267:2018-12); Decke (ARCHICAD Klassifizierung); Material: 01_ALLGEMEIN - BAUTEIL 0.28 m
AC_Pset_RenovationAndPhasing - Renovation Status: Existing
Pset_SlabCommon - LoadBearing: no; IsExternal: no

# IfcSlab: 01_ALLGEMEIN - BAUTEIL 304 (2)
In: 2.OBERGESCHOSS
Classification: 351 Deckenkonstruktionen (Classification DIN 267:2018-12); Decke (ARCHICAD Klassifizierung); Material: 01_ALLGEMEIN - BAUTEIL 0.304179 m
AC_Pset_RenovationAndPhasing - Renovation Status: Existing
Pset_SlabCommon - LoadBearing: no; IsExternal: no

# IfcSlab: 01_ALLGEMEIN - BAUTEIL 316 (2)
In: 2.OBERGESCHOSS
Classification: 351 Deckenkonstruktionen (Classification DIN 267:2018-12); Decke (ARCHICAD Klassifizierung); Material: 01_ALLGEMEIN - BAUTEIL 0.315723 m
AC_Pset_RenovationAndPhasing - Renovation Status: Existing
Pset_SlabCommon - LoadBearing: no; IsExternal: no

# IfcSlab: 01_ALLGEMEIN - BAUTEIL 326 (2)
In: 2.OBERGESCHOSS
Classification: 351 Deckenkonstruktionen (Classification DIN 267:2018-12); Decke (ARCHICAD Klassifizierung); Material: 01_ALLGEMEIN - BAUTEIL 0.325988 m
AC_Pset_RenovationAndPhasing - Renovation Status: Existing
Pset_SlabCommon - LoadBearing: no; IsExternal: no

# IfcSlab: 01_ALLGEMEIN - BAUTEIL 345, Dach-006
In: DACHGESCHOSS
Type - PredefinedType: ROOF
Classification: Dach (ARCHICAD Klassifizierung); 363 Dachbeläge (Classification DIN 267:2018-12); Material: 01_ALLGEMEIN - BAUTEIL
Pset_SlabCommon - ThermalTransmittance: 0; LoadBearing: yes; IsExternal: yes
AC_Pset_RenovationAndPhasing - Renovation Status: Existing

# IfcSlab: 01_ALLGEMEIN - BAUTEIL 347, Dach-006
In: DACHGESCHOSS
Type - PredefinedType: ROOF
Classification: Dach (ARCHICAD Klassifizierung); 363 Dachbeläge (Classification DIN 267:2018-12); Material: 01_ALLGEMEIN - BAUTEIL
Pset_SlabCommon - ThermalTransmittance: 0; LoadBearing: yes; IsExternal: yes
AC_Pset_RenovationAndPhasing - Renovation Status: Existing

# IfcSlab: 01_ALLGEMEIN - BAUTEIL 400 (2)
In: 2.OBERGESCHOSS
Classification: 351 Deckenkonstruktionen (Classification DIN 267:2018-12); Decke (ARCHICAD Klassifizierung)
AC_Pset_RenovationAndPhasing - Renovation Status: Existing
Pset_SlabCommon - LoadBearing: no; IsExternal: no
Name | Material
Belag-006 | 01_ALLGEMEIN - BAUTEIL 0.4 m
Belag-007 | 01_ALLGEMEIN - BAUTEIL 0.399885 m

# IfcSlab: 01_ALLGEMEIN - BAUTEIL 433, Belag-005
In: 2.OBERGESCHOSS
Classification: 351 Deckenkonstruktionen (Classification DIN 267:2018-12); Decke (ARCHICAD Klassifizierung); Material: 01_ALLGEMEIN - BAUTEIL 0.432794 m
AC_Pset_RenovationAndPhasing - Renovation Status: Existing
Pset_SlabCommon - LoadBearing: no; IsExternal: no

# IfcSlab: 01_ALLGEMEIN - BAUTEIL 50 (68)
Classification: 351 Deckenkonstruktionen (Classification DIN 267:2018-12); Decke (ARCHICAD Klassifizierung); Material: 01_ALLGEMEIN - BAUTEIL 0.05 m
AC_Pset_RenovationAndPhasing - Renovation Status: Existing
Pset_SlabCommon - LoadBearing: no; IsExternal: no
Name | In
2 x Belag-004 | 2.OBERGESCHOSS
Belag-005 | 2.OBERGESCHOSS
4 x Belag-006 | 2.OBERGESCHOSS
Belag-007 | 2.OBERGESCHOSS
Belag-008 | 2.OBERGESCHOSS
Belag-009 | 2.OBERGESCHOSS
Belag-010 | 2.OBERGESCHOSS
28 x Belag-004 | ERDGESCHOSS
4 x Belag-004 | KELLERGESCHOSS
3 x Belag-005 | KELLERGESCHOSS
2 x Belag-006 | KELLERGESCHOSS
3 x Belag-007 | KELLERGESCHOSS
Belag-008 | KELLERGESCHOSS
3 x Belag-009 | KELLERGESCHOSS
3 x Belag-010 | KELLERGESCHOSS
3 x Belag-011 | KELLERGESCHOSS
2 x Belag-012 | KELLERGESCHOSS
3 x Belag-013 | KELLERGESCHOSS
2 x Belag-014 | KELLERGESCHOSS

# IfcSlab: 01_ALLGEMEIN - BAUTEIL 60 (16)
In: KELLERGESCHOSS
Classification: 351 Deckenkonstruktionen (Classification DIN 267:2018-12); Decke (ARCHICAD Klassifizierung); Material: 01_ALLGEMEIN - BAUTEIL 0.06 m
AC_Pset_RenovationAndPhasing - Renovation Status: Existing
Pset_SlabCommon - LoadBearing: no; IsExternal: no
Name
8 x Belag-004
5 x Belag-005
Belag-006
2 x Belag-007

# IfcSlab: 01_ALLGEMEIN - BAUTEIL 67, Belag-004
In: DACHGESCHOSS
Classification: 351 Deckenkonstruktionen (Classification DIN 267:2018-12); Decke (ARCHICAD Klassifizierung); Material: 01_ALLGEMEIN - BAUTEIL 0.066764 m
AC_Pset_RenovationAndPhasing - Renovation Status: Existing
Pset_SlabCommon - LoadBearing: no; IsExternal: no

# IfcSlab: 01_ALLGEMEIN - BAUTEIL 70 (2)
In: KELLERGESCHOSS
Classification: 351 Deckenkonstruktionen (Classification DIN 267:2018-12); Decke (ARCHICAD Klassifizierung); Material: 01_ALLGEMEIN - BAUTEIL 0.07 m
AC_Pset_RenovationAndPhasing - Renovation Status: Existing
Pset_SlabCommon - LoadBearing: no; IsExternal: no
Name
Belag-015
Belag-016

# IfcSlab: 01_ALLGEMEIN - BAUTEIL 90, Belag-013
In: KELLERGESCHOSS
Classification: 351 Deckenkonstruktionen (Classification DIN 267:2018-12); Decke (ARCHICAD Klassifizierung); Material: 01_ALLGEMEIN - BAUTEIL 0.09 m
AC_Pset_RenovationAndPhasing - Renovation Status: Existing
Pset_SlabCommon - LoadBearing: no; IsExternal: no

# IfcSlab: 01_ALLGEMEIN - BAUTEIL 97, Belag-005
In: 2.OBERGESCHOSS
Classification: 351 Deckenkonstruktionen (Classification DIN 267:2018-12); Decke (ARCHICAD Klassifizierung); Material: 01_ALLGEMEIN - BAUTEIL 0.0967517 m
AC_Pset_RenovationAndPhasing - Renovation Status: Existing
Pset_SlabCommon - LoadBearing: no; IsExternal: no

# IfcSlab: 05_ALLGEMEIN - TRAGENDE BAUTEILE 100 (28)
Classification: 351 Deckenkonstruktionen (Classification DIN 267:2018-12); Decke (ARCHICAD Klassifizierung); Material: 05_ALLGEMEIN - TRAGENDE BAUTEILE 0.1 m
AC_Pset_RenovationAndPhasing - Renovation Status: Existing
Pset_SlabCommon - LoadBearing: no; IsExternal: no
Name | In
4 x Belag-003 | ERDGESCHOSS
9 x Belag-004 | ERDGESCHOSS
5 x Belag-005 | ERDGESCHOSS
Belag-006 | ERDGESCHOSS
3 x Belag-007 | ERDGESCHOSS
Belag-005 | KELLERGESCHOSS
4 x Belag-008 | KELLERGESCHOSS
Belag-016 | KELLERGESCHOSS

# IfcSlab: 05_ALLGEMEIN - TRAGENDE BAUTEILE 105, Belag-004
In: ERDGESCHOSS
Classification: 351 Deckenkonstruktionen (Classification DIN 267:2018-12); Decke (ARCHICAD Klassifizierung); Material: 05_ALLGEMEIN - TRAGENDE BAUTEILE 0.105 m
AC_Pset_RenovationAndPhasing - Renovation Status: Existing
Pset_SlabCommon - LoadBearing: no; IsExternal: no

# IfcSlab: 05_ALLGEMEIN - TRAGENDE BAUTEILE 1050 (2)
In: 1.OBERGESCHOSS
Classification: 351 Deckenkonstruktionen (Classification DIN 267:2018-12); Decke (ARCHICAD Klassifizierung); Material: 05_ALLGEMEIN - TRAGENDE BAUTEILE 1.05 m
AC_Pset_RenovationAndPhasing - Renovation Status: Existing
Pset_SlabCommon - LoadBearing: no; IsExternal: no

# IfcSlab: 05_ALLGEMEIN - TRAGENDE BAUTEILE 1060, Belag-040
In: 1.OBERGESCHOSS
Classification: 351 Deckenkonstruktionen (Classification DIN 267:2018-12); Decke (ARCHICAD Klassifizierung); Material: 05_ALLGEMEIN - TRAGENDE BAUTEILE 1.06 m
AC_Pset_RenovationAndPhasing - Renovation Status: Existing
Pset_SlabCommon - LoadBearing: no; IsExternal: no

# IfcSlab: 05_ALLGEMEIN - TRAGENDE BAUTEILE 1080, Belag-038
In: 1.OBERGESCHOSS
Classification: 351 Deckenkonstruktionen (Classification DIN 267:2018-12); Decke (ARCHICAD Klassifizierung); Material: 05_ALLGEMEIN - TRAGENDE BAUTEILE 1.08 m
AC_Pset_RenovationAndPhasing - Renovation Status: Existing
Pset_SlabCommon - LoadBearing: no; IsExternal: no

# IfcSlab: 05_ALLGEMEIN - TRAGENDE BAUTEILE 110 (3)
Classification: 351 Deckenkonstruktionen (Classification DIN 267:2018-12); Decke (ARCHICAD Klassifizierung); Material: 05_ALLGEMEIN - TRAGENDE BAUTEILE 0.11 m
AC_Pset_RenovationAndPhasing - Renovation Status: Existing
Pset_SlabCommon - LoadBearing: no; IsExternal: no
Name | In
Belag-003 | ERDGESCHOSS
Belag-005 | ERDGESCHOSS
Belag-019 | KELLERGESCHOSS

# IfcSlab: 05_ALLGEMEIN - TRAGENDE BAUTEILE 120 (3)
In: KELLERGESCHOSS
Classification: 351 Deckenkonstruktionen (Classification DIN 267:2018-12); Decke (ARCHICAD Klassifizierung); Material: 05_ALLGEMEIN - TRAGENDE BAUTEILE 0.12 m
AC_Pset_RenovationAndPhasing - Renovation Status: Existing
Pset_SlabCommon - LoadBearing: no; IsExternal: no
Name
2 x Belag-005
Belag-009

# IfcSlab: 05_ALLGEMEIN - TRAGENDE BAUTEILE 122, Belag-007
In: KELLERGESCHOSS
Classification: 351 Deckenkonstruktionen (Classification DIN 267:2018-12); Decke (ARCHICAD Klassifizierung); Material: 05_ALLGEMEIN - TRAGENDE BAUTEILE 0.12183 m
AC_Pset_RenovationAndPhasing - Renovation Status: Existing
Pset_SlabCommon - LoadBearing: no; IsExternal: no

# IfcSlab: 05_ALLGEMEIN - TRAGENDE BAUTEILE 1290, Belag-038
In: 1.OBERGESCHOSS
Classification: 351 Deckenkonstruktionen (Classification DIN 267:2018-12); Decke (ARCHICAD Klassifizierung); Material: 05_ALLGEMEIN - TRAGENDE BAUTEILE 1.29 m
AC_Pset_RenovationAndPhasing - Renovation Status: Existing
Pset_SlabCommon - LoadBearing: no; IsExternal: no

# IfcSlab: 05_ALLGEMEIN - TRAGENDE BAUTEILE 130 (8)
Classification: 351 Deckenkonstruktionen (Classification DIN 267:2018-12); Decke (ARCHICAD Klassifizierung); Material: 05_ALLGEMEIN - TRAGENDE BAUTEILE 0.13 m
AC_Pset_RenovationAndPhasing - Renovation Status: Existing
Pset_SlabCommon - LoadBearing: no; IsExternal: no
Name | In
3 x Belag-003 | ERDGESCHOSS
Belag-005 | ERDGESCHOSS
Belag-006 | ERDGESCHOSS
Belag-007 | KELLERGESCHOSS
2 x Belag-011 | KELLERGESCHOSS

# IfcSlab: 05_ALLGEMEIN - TRAGENDE BAUTEILE 136, Belag-008
In: 2.OBERGESCHOSS
Classification: 351 Deckenkonstruktionen (Classification DIN 267:2018-12); Decke (ARCHICAD Klassifizierung); Material: 05_ALLGEMEIN - TRAGENDE BAUTEILE 0.136271 m
AC_Pset_RenovationAndPhasing - Renovation Status: Existing
Pset_SlabCommon - LoadBearing: no; IsExternal: no

# IfcSlab: 05_ALLGEMEIN - TRAGENDE BAUTEILE 1360, Belag-005
In: KELLERGESCHOSS
Classification: 351 Deckenkonstruktionen (Classification DIN 267:2018-12); Decke (ARCHICAD Klassifizierung); Material: 05_ALLGEMEIN - TRAGENDE BAUTEILE 1.36 m
AC_Pset_RenovationAndPhasing - Renovation Status: Existing
Pset_SlabCommon - LoadBearing: no; IsExternal: no

# IfcSlab: 05_ALLGEMEIN - TRAGENDE BAUTEILE 140 (4)
In: ERDGESCHOSS
Classification: 351 Deckenkonstruktionen (Classification DIN 267:2018-12); Decke (ARCHICAD Klassifizierung); Material: 05_ALLGEMEIN - TRAGENDE BAUTEILE 0.14 m
AC_Pset_RenovationAndPhasing - Renovation Status: Existing
Pset_SlabCommon - LoadBearing: no; IsExternal: no
Name
3 x Belag-003
Belag-004

# IfcSlab: 05_ALLGEMEIN - TRAGENDE BAUTEILE 146, Belag-025
In: 1.OBERGESCHOSS
Classification: 351 Deckenkonstruktionen (Classification DIN 267:2018-12); Decke (ARCHICAD Klassifizierung); Material: 05_ALLGEMEIN - TRAGENDE BAUTEILE 0.145758 m
AC_Pset_RenovationAndPhasing - Renovation Status: Existing
Pset_SlabCommon - LoadBearing: no; IsExternal: no

# IfcSlab: 05_ALLGEMEIN - TRAGENDE BAUTEILE 150 (12)
Classification: 351 Deckenkonstruktionen (Classification DIN 267:2018-12); Decke (ARCHICAD Klassifizierung); Material: 05_ALLGEMEIN - TRAGENDE BAUTEILE 0.15 m
AC_Pset_RenovationAndPhasing - Renovation Status: Existing
Pset_SlabCommon - LoadBearing: no; IsExternal: no
Name | In
Belag-017 | 2.OBERGESCHOSS
2 x Belag-018 | 2.OBERGESCHOSS
3 x Belag-018 | 1.OBERGESCHOSS
2 x Belag-019 | 1.OBERGESCHOSS
Belag-020 | 1.OBERGESCHOSS
Belag-021 | 1.OBERGESCHOSS
Belag-022 | 1.OBERGESCHOSS
Belag-004 | KELLERGESCHOSS

# IfcSlab: 05_ALLGEMEIN - TRAGENDE BAUTEILE 150 (2)
Type - PredefinedType: ROOF
Classification: Dach (ARCHICAD Klassifizierung); 363 Dachbeläge (Classification DIN 267:2018-12); Material: 05_ALLGEMEIN - TRAGENDE BAUTEILE 0.15 m
Pset_SlabCommon - ThermalTransmittance: 0; LoadBearing: yes; IsExternal: yes
AC_Pset_RenovationAndPhasing - Renovation Status: Existing
Name | In
Dach-013 | 1.OBERGESCHOSS
Dach-013 | ERDGESCHOSS

# IfcSlab: 05_ALLGEMEIN - TRAGENDE BAUTEILE 153, Belag-004
In: ERDGESCHOSS
Classification: 351 Deckenkonstruktionen (Classification DIN 267:2018-12); Decke (ARCHICAD Klassifizierung); Material: 05_ALLGEMEIN - TRAGENDE BAUTEILE 0.153352 m
AC_Pset_RenovationAndPhasing - Renovation Status: Existing
Pset_SlabCommon - LoadBearing: no; IsExternal: no

# IfcSlab: 05_ALLGEMEIN - TRAGENDE BAUTEILE 155, Belag-003
In: ERDGESCHOSS
Classification: 351 Deckenkonstruktionen (Classification DIN 267:2018-12); Decke (ARCHICAD Klassifizierung); Material: 05_ALLGEMEIN - TRAGENDE BAUTEILE 0.155 m
AC_Pset_RenovationAndPhasing - Renovation Status: Existing
Pset_SlabCommon - LoadBearing: no; IsExternal: no

# IfcSlab: 05_ALLGEMEIN - TRAGENDE BAUTEILE 1568 (2)
In: ERDGESCHOSS
Classification: 351 Deckenkonstruktionen (Classification DIN 267:2018-12); Decke (ARCHICAD Klassifizierung); Material: 05_ALLGEMEIN - TRAGENDE BAUTEILE 1.56764 m
AC_Pset_RenovationAndPhasing - Renovation Status: Existing
Pset_SlabCommon - LoadBearing: no; IsExternal: no

# IfcSlab: 05_ALLGEMEIN - TRAGENDE BAUTEILE 1572 (2)
In: 1.OBERGESCHOSS
Classification: 351 Deckenkonstruktionen (Classification DIN 267:2018-12); Decke (ARCHICAD Klassifizierung); Material: 05_ALLGEMEIN - TRAGENDE BAUTEILE 1.57184 m
AC_Pset_RenovationAndPhasing - Renovation Status: Existing
Pset_SlabCommon - LoadBearing: no; IsExternal: no

# IfcSlab: 05_ALLGEMEIN - TRAGENDE BAUTEILE 160 (7)
Classification: 351 Deckenkonstruktionen (Classification DIN 267:2018-12); Decke (ARCHICAD Klassifizierung); Material: 05_ALLGEMEIN - TRAGENDE BAUTEILE 0.16 m
AC_Pset_RenovationAndPhasing - Renovation Status: Existing
Pset_SlabCommon - LoadBearing: no; IsExternal: no
Name | In
Belag-004 | ERDGESCHOSS
Belag-007 | KELLERGESCHOSS
2 x Belag-008 | KELLERGESCHOSS
3 x Belag-009 | KELLERGESCHOSS

# IfcSlab: 05_ALLGEMEIN - TRAGENDE BAUTEILE 170 (22)
Classification: 351 Deckenkonstruktionen (Classification DIN 267:2018-12); Decke (ARCHICAD Klassifizierung); Material: 05_ALLGEMEIN - TRAGENDE BAUTEILE 0.17 m
AC_Pset_RenovationAndPhasing - Renovation Status: Existing
Pset_SlabCommon - LoadBearing: no; IsExternal: no
Name | In
2 x Belag-020 | 1.OBERGESCHOSS
Belag-021 | 1.OBERGESCHOSS
Belag-039 | 1.OBERGESCHOSS
2 x Belag-040 | 1.OBERGESCHOSS
Belag-041 | 1.OBERGESCHOSS
2 x Belag-007 | KELLERGESCHOSS
7 x Belag-008 | KELLERGESCHOSS
Belag-009 | KELLERGESCHOSS
Belag-010 | KELLERGESCHOSS
Belag-011 | KELLERGESCHOSS
Belag-012 | KELLERGESCHOSS
Belag-013 | KELLERGESCHOSS
Belag-020 | KELLERGESCHOSS

# IfcSlab: 05_ALLGEMEIN - TRAGENDE BAUTEILE 171, Belag-007
In: KELLERGESCHOSS
Classification: 351 Deckenkonstruktionen (Classification DIN 267:2018-12); Decke (ARCHICAD Klassifizierung); Material: 05_ALLGEMEIN - TRAGENDE BAUTEILE 0.171026 m
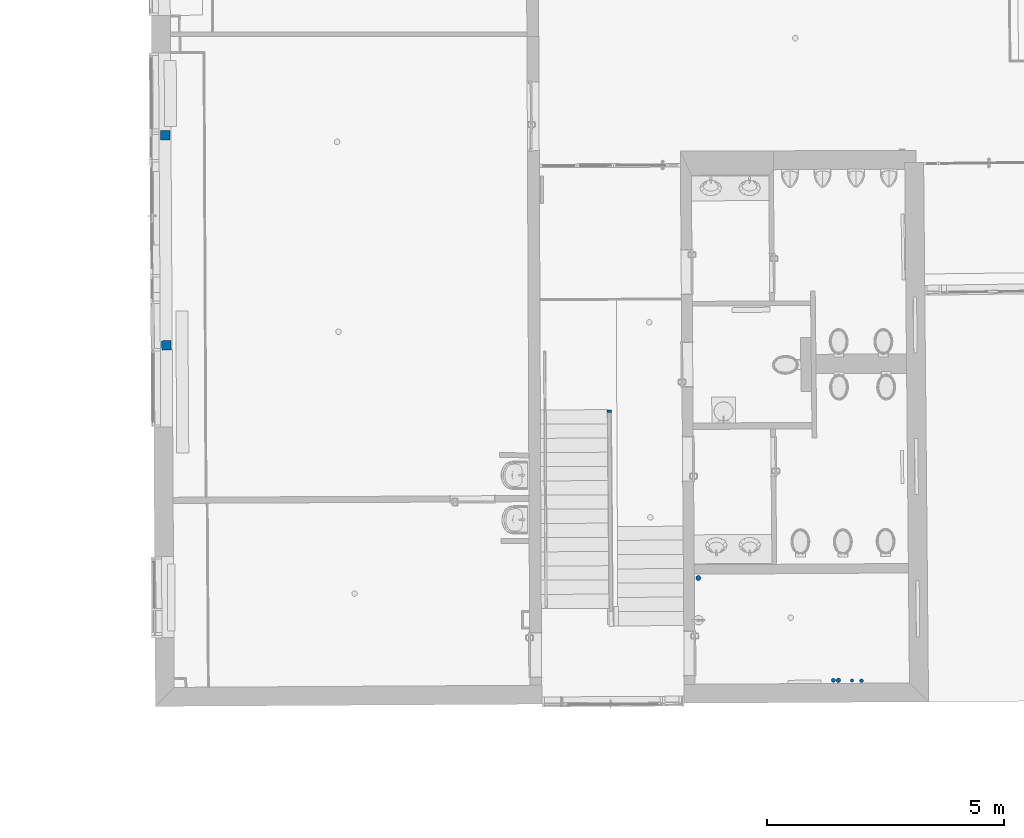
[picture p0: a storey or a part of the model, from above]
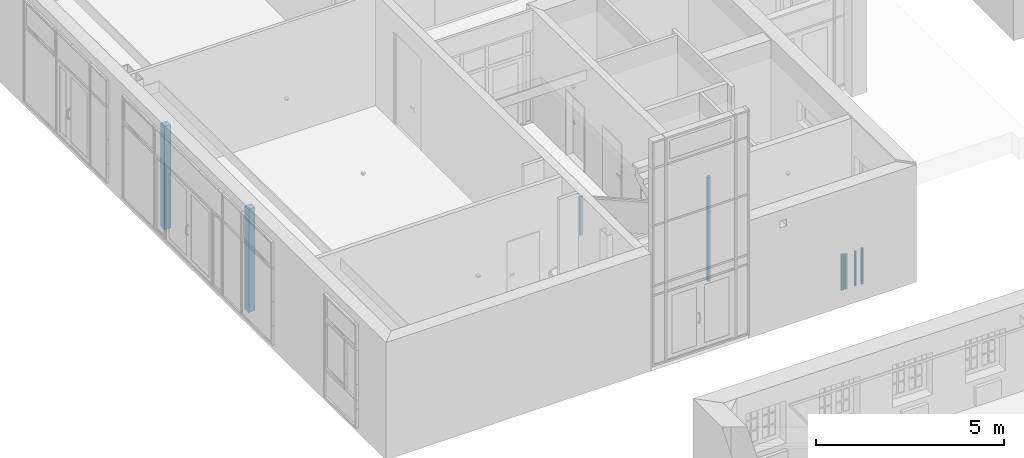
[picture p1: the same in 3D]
Properties of the parts of a building model (IFC2X3), part 3 of 4

# IfcSlab: 05_ALLGEMEIN - TRAGENDE BAUTEILE 171, Belag-007
AC_Pset_RenovationAndPhasing - Renovation Status: Existing
Pset_SlabCommon - LoadBearing: no; IsExternal: no

# IfcSlab: 05_ALLGEMEIN - TRAGENDE BAUTEILE 180 (13)
Classification: 351 Deckenkonstruktionen (Classification DIN 267:2018-12); Decke (ARCHICAD Klassifizierung); Material: 05_ALLGEMEIN - TRAGENDE BAUTEILE 0.18 m
AC_Pset_RenovationAndPhasing - Renovation Status: Existing
Pset_SlabCommon - LoadBearing: no; IsExternal: no
Name | In
2 x Belag-039 | 1.OBERGESCHOSS
2 x Belag-003 | ERDGESCHOSS
Belag-004 | ERDGESCHOSS
Belag-005 | ERDGESCHOSS
Belag-006 | ERDGESCHOSS
Belag-007 | ERDGESCHOSS
4 x Belag-011 | KELLERGESCHOSS
Belag-022 | KELLERGESCHOSS

# IfcSlab: 05_ALLGEMEIN - TRAGENDE BAUTEILE 183, Belag-030
In: 1.OBERGESCHOSS
Classification: 351 Deckenkonstruktionen (Classification DIN 267:2018-12); Decke (ARCHICAD Klassifizierung); Material: 05_ALLGEMEIN - TRAGENDE BAUTEILE 0.182958 m
AC_Pset_RenovationAndPhasing - Renovation Status: Existing
Pset_SlabCommon - LoadBearing: no; IsExternal: no

# IfcSlab: 05_ALLGEMEIN - TRAGENDE BAUTEILE 190 (4)
Classification: 351 Deckenkonstruktionen (Classification DIN 267:2018-12); Decke (ARCHICAD Klassifizierung); Material: 05_ALLGEMEIN - TRAGENDE BAUTEILE 0.19 m
AC_Pset_RenovationAndPhasing - Renovation Status: Existing
Pset_SlabCommon - LoadBearing: no; IsExternal: no
Name | In
Belag-034 | 1.OBERGESCHOSS
Belag-035 | 1.OBERGESCHOSS
Belag-020 | KELLERGESCHOSS
Belag-021 | KELLERGESCHOSS

# IfcSlab: 05_ALLGEMEIN - TRAGENDE BAUTEILE 200 (22)
Classification: 351 Deckenkonstruktionen (Classification DIN 267:2018-12); Decke (ARCHICAD Klassifizierung); Material: 05_ALLGEMEIN - TRAGENDE BAUTEILE 0.2 m
AC_Pset_RenovationAndPhasing - Renovation Status: Existing
Pset_SlabCommon - LoadBearing: no; IsExternal: no
Name | In
2 x Belag-023 | 1.OBERGESCHOSS
Belag-024 | 1.OBERGESCHOSS
2 x Belag-025 | 1.OBERGESCHOSS
Belag-026 | 1.OBERGESCHOSS
Belag-027 | 1.OBERGESCHOSS
Belag-028 | 1.OBERGESCHOSS
Belag-029 | 1.OBERGESCHOSS
Belag-030 | 1.OBERGESCHOSS
Belag-031 | 1.OBERGESCHOSS
Belag-032 | 1.OBERGESCHOSS
Belag-033 | 1.OBERGESCHOSS
Belag-034 | 1.OBERGESCHOSS
Belag-036 | 1.OBERGESCHOSS
3 x Belag-039 | 1.OBERGESCHOSS
Belag-003 | ERDGESCHOSS
Belag-005 | KELLERGESCHOSS
Belag-008 | KELLERGESCHOSS
Belag-014 | KELLERGESCHOSS

# IfcSlab: 05_ALLGEMEIN - TRAGENDE BAUTEILE 210 (4)
Classification: 351 Deckenkonstruktionen (Classification DIN 267:2018-12); Decke (ARCHICAD Klassifizierung); Material: 05_ALLGEMEIN - TRAGENDE BAUTEILE 0.21 m
AC_Pset_RenovationAndPhasing - Renovation Status: Existing
Pset_SlabCommon - LoadBearing: no; IsExternal: no
Name | In
Belag-019 | 1.OBERGESCHOSS
Belag-039 | 1.OBERGESCHOSS
Belag-005 | KELLERGESCHOSS
Belag-008 | KELLERGESCHOSS

# IfcSlab: 05_ALLGEMEIN - TRAGENDE BAUTEILE 220, Belag-003
In: ERDGESCHOSS
Classification: 351 Deckenkonstruktionen (Classification DIN 267:2018-12); Decke (ARCHICAD Klassifizierung); Material: 05_ALLGEMEIN - TRAGENDE BAUTEILE 0.22 m
AC_Pset_RenovationAndPhasing - Renovation Status: Existing
Pset_SlabCommon - LoadBearing: no; IsExternal: no

# IfcSlab: 05_ALLGEMEIN - TRAGENDE BAUTEILE 228 (2)
In: 1.OBERGESCHOSS
Classification: 351 Deckenkonstruktionen (Classification DIN 267:2018-12); Decke (ARCHICAD Klassifizierung); Material: 05_ALLGEMEIN - TRAGENDE BAUTEILE 0.228375 m
AC_Pset_RenovationAndPhasing - Renovation Status: Existing
Pset_SlabCommon - LoadBearing: no; IsExternal: no

# IfcSlab: 05_ALLGEMEIN - TRAGENDE BAUTEILE 230 (2)
In: 1.OBERGESCHOSS
Classification: 351 Deckenkonstruktionen (Classification DIN 267:2018-12); Decke (ARCHICAD Klassifizierung); Material: 05_ALLGEMEIN - TRAGENDE BAUTEILE 0.23 m
AC_Pset_RenovationAndPhasing - Renovation Status: Existing
Pset_SlabCommon - LoadBearing: no; IsExternal: no
Name
Belag-035
Belag-036

# IfcSlab: 05_ALLGEMEIN - TRAGENDE BAUTEILE 240 (3)
In: 1.OBERGESCHOSS
Classification: 351 Deckenkonstruktionen (Classification DIN 267:2018-12); Decke (ARCHICAD Klassifizierung); Material: 05_ALLGEMEIN - TRAGENDE BAUTEILE 0.24 m
AC_Pset_RenovationAndPhasing - Renovation Status: Existing
Pset_SlabCommon - LoadBearing: no; IsExternal: no
Name
Belag-032
2 x Belag-040

# IfcSlab: 05_ALLGEMEIN - TRAGENDE BAUTEILE 245, Belag-011
In: KELLERGESCHOSS
Classification: 351 Deckenkonstruktionen (Classification DIN 267:2018-12); Decke (ARCHICAD Klassifizierung); Material: 05_ALLGEMEIN - TRAGENDE BAUTEILE 0.2445 m
AC_Pset_RenovationAndPhasing - Renovation Status: Existing
Pset_SlabCommon - LoadBearing: no; IsExternal: no

# IfcSlab: 05_ALLGEMEIN - TRAGENDE BAUTEILE 25 (2)
In: DACHGESCHOSS
Classification: 351 Deckenkonstruktionen (Classification DIN 267:2018-12); Decke (ARCHICAD Klassifizierung); Material: 05_ALLGEMEIN - TRAGENDE BAUTEILE 0.025 m
AC_Pset_RenovationAndPhasing - Renovation Status: Existing
Pset_SlabCommon - LoadBearing: no; IsExternal: no
Name
Belag-026
Belag-027

# IfcSlab: 05_ALLGEMEIN - TRAGENDE BAUTEILE 250 (8)
Classification: 351 Deckenkonstruktionen (Classification DIN 267:2018-12); Decke (ARCHICAD Klassifizierung); Material: 05_ALLGEMEIN - TRAGENDE BAUTEILE 0.25 m
AC_Pset_RenovationAndPhasing - Renovation Status: Existing
Pset_SlabCommon - LoadBearing: no; IsExternal: no
Name | In
Belag-003 | ERDGESCHOSS
Belag-013 | ERDGESCHOSS
2 x Belag-004 | KELLERGESCHOSS
3 x Belag-005 | KELLERGESCHOSS
Belag-008 | KELLERGESCHOSS

# IfcSlab: 05_ALLGEMEIN - TRAGENDE BAUTEILE 260 (8)
Classification: 351 Deckenkonstruktionen (Classification DIN 267:2018-12); Decke (ARCHICAD Klassifizierung)
AC_Pset_RenovationAndPhasing - Renovation Status: Existing
Pset_SlabCommon - LoadBearing: no; IsExternal: no
Name | In | Material
Belag-016 | SPITZBODEN | 05_ALLGEMEIN - TRAGENDE BAUTEILE 0.259901 m
4 x Belag-006 | ERDGESCHOSS | 05_ALLGEMEIN - TRAGENDE BAUTEILE 0.26 m
Belag-004 | KELLERGESCHOSS | 05_ALLGEMEIN - TRAGENDE BAUTEILE 0.26 m
2 x Belag-005 | KELLERGESCHOSS | 05_ALLGEMEIN - TRAGENDE BAUTEILE 0.26 m

# IfcSlab: 05_ALLGEMEIN - TRAGENDE BAUTEILE 270 (3)
Classification: 351 Deckenkonstruktionen (Classification DIN 267:2018-12); Decke (ARCHICAD Klassifizierung); Material: 05_ALLGEMEIN - TRAGENDE BAUTEILE 0.27 m
AC_Pset_RenovationAndPhasing - Renovation Status: Existing
Pset_SlabCommon - LoadBearing: no; IsExternal: no
Name | In
Belag-034 | 1.OBERGESCHOSS
Belag-004 | ERDGESCHOSS
Belag-005 | KELLERGESCHOSS

# IfcSlab: 05_ALLGEMEIN - TRAGENDE BAUTEILE 273, Belag-005
In: KELLERGESCHOSS
Classification: 351 Deckenkonstruktionen (Classification DIN 267:2018-12); Decke (ARCHICAD Klassifizierung); Material: 05_ALLGEMEIN - TRAGENDE BAUTEILE 0.272925 m
AC_Pset_RenovationAndPhasing - Renovation Status: Existing
Pset_SlabCommon - LoadBearing: no; IsExternal: no

# IfcSlab: 05_ALLGEMEIN - TRAGENDE BAUTEILE 280 (7)
Classification: 351 Deckenkonstruktionen (Classification DIN 267:2018-12); Decke (ARCHICAD Klassifizierung)
AC_Pset_RenovationAndPhasing - Renovation Status: Existing
Pset_SlabCommon - LoadBearing: no; IsExternal: no
Name | In | Material
2 x Belag-006 | ERDGESCHOSS | 05_ALLGEMEIN - TRAGENDE BAUTEILE 0.28 m
Belag-006 | ERDGESCHOSS | 05_ALLGEMEIN - TRAGENDE BAUTEILE 0.280439 m
2 x Belag-006 | KELLERGESCHOSS | 05_ALLGEMEIN - TRAGENDE BAUTEILE 0.28 m
Belag-007 | KELLERGESCHOSS | 05_ALLGEMEIN - TRAGENDE BAUTEILE 0.28 m
Belag-009 | KELLERGESCHOSS | 05_ALLGEMEIN - TRAGENDE BAUTEILE 0.28 m

# IfcSlab: 05_ALLGEMEIN - TRAGENDE BAUTEILE 285, Belag-008
In: KELLERGESCHOSS
Classification: 351 Deckenkonstruktionen (Classification DIN 267:2018-12); Decke (ARCHICAD Klassifizierung); Material: 05_ALLGEMEIN - TRAGENDE BAUTEILE 0.285 m
AC_Pset_RenovationAndPhasing - Renovation Status: Existing
Pset_SlabCommon - LoadBearing: no; IsExternal: no

# IfcSlab: 05_ALLGEMEIN - TRAGENDE BAUTEILE 290 (2)
Classification: 351 Deckenkonstruktionen (Classification DIN 267:2018-12); Decke (ARCHICAD Klassifizierung); Material: 05_ALLGEMEIN - TRAGENDE BAUTEILE 0.29 m
AC_Pset_RenovationAndPhasing - Renovation Status: Existing
Pset_SlabCommon - LoadBearing: no; IsExternal: no
Name | In
Belag-006 | ERDGESCHOSS
Belag-005 | KELLERGESCHOSS

# IfcSlab: 05_ALLGEMEIN - TRAGENDE BAUTEILE 295 (3)
Classification: 351 Deckenkonstruktionen (Classification DIN 267:2018-12); Decke (ARCHICAD Klassifizierung); Material: 05_ALLGEMEIN - TRAGENDE BAUTEILE 0.295 m
AC_Pset_RenovationAndPhasing - Renovation Status: Existing
Pset_SlabCommon - LoadBearing: no; IsExternal: no
Name | In
Belag-007 | ERDGESCHOSS
Belag-008 | ERDGESCHOSS
Belag-008 | KELLERGESCHOSS

# IfcSlab: 05_ALLGEMEIN - TRAGENDE BAUTEILE 298, Belag-015
In: KELLERGESCHOSS
Classification: 351 Deckenkonstruktionen (Classification DIN 267:2018-12); Decke (ARCHICAD Klassifizierung); Material: 05_ALLGEMEIN - TRAGENDE BAUTEILE 0.297593 m
AC_Pset_RenovationAndPhasing - Renovation Status: Existing
Pset_SlabCommon - LoadBearing: no; IsExternal: no

# IfcSlab: 05_ALLGEMEIN - TRAGENDE BAUTEILE 30 (3)
Classification: 351 Deckenkonstruktionen (Classification DIN 267:2018-12); Decke (ARCHICAD Klassifizierung); Material: 05_ALLGEMEIN - TRAGENDE BAUTEILE 0.03 m
AC_Pset_RenovationAndPhasing - Renovation Status: Existing
Pset_SlabCommon - LoadBearing: no; IsExternal: no
Name | In
Belag-028 | DACHGESCHOSS
2 x Belag-004 | ERDGESCHOSS

# IfcSlab: 05_ALLGEMEIN - TRAGENDE BAUTEILE 310 (2)
Classification: 351 Deckenkonstruktionen (Classification DIN 267:2018-12); Decke (ARCHICAD Klassifizierung); Material: 05_ALLGEMEIN - TRAGENDE BAUTEILE 0.31 m
AC_Pset_RenovationAndPhasing - Renovation Status: Existing
Pset_SlabCommon - LoadBearing: no; IsExternal: no
Name | In
Belag-016 | 2.OBERGESCHOSS
Belag-003 | KELLERGESCHOSS

# IfcSlab: 05_ALLGEMEIN - TRAGENDE BAUTEILE 314, Belag-003
In: KELLERGESCHOSS
Classification: 351 Deckenkonstruktionen (Classification DIN 267:2018-12); Decke (ARCHICAD Klassifizierung); Material: 05_ALLGEMEIN - TRAGENDE BAUTEILE 0.314114 m
AC_Pset_RenovationAndPhasing - Renovation Status: Existing
Pset_SlabCommon - LoadBearing: no; IsExternal: no

# IfcSlab: 05_ALLGEMEIN - TRAGENDE BAUTEILE 315, Belag-008
In: ERDGESCHOSS
Classification: 351 Deckenkonstruktionen (Classification DIN 267:2018-12); Decke (ARCHICAD Klassifizierung); Material: 05_ALLGEMEIN - TRAGENDE BAUTEILE 0.315 m
AC_Pset_RenovationAndPhasing - Renovation Status: Existing
Pset_SlabCommon - LoadBearing: no; IsExternal: no

# IfcSlab: 05_ALLGEMEIN - TRAGENDE BAUTEILE 316, Belag-003
In: KELLERGESCHOSS
Classification: 351 Deckenkonstruktionen (Classification DIN 267:2018-12); Decke (ARCHICAD Klassifizierung); Material: 05_ALLGEMEIN - TRAGENDE BAUTEILE 0.315652 m
AC_Pset_RenovationAndPhasing - Renovation Status: Existing
Pset_SlabCommon - LoadBearing: no; IsExternal: no

# IfcSlab: 05_ALLGEMEIN - TRAGENDE BAUTEILE 318, Belag-019
In: 2.OBERGESCHOSS
Classification: 351 Deckenkonstruktionen (Classification DIN 267:2018-12); Decke (ARCHICAD Klassifizierung); Material: 05_ALLGEMEIN - TRAGENDE BAUTEILE 0.317835 m
AC_Pset_RenovationAndPhasing - Renovation Status: Existing
Pset_SlabCommon - LoadBearing: no; IsExternal: no

# IfcSlab: 05_ALLGEMEIN - TRAGENDE BAUTEILE 319, Belag-003
In: KELLERGESCHOSS
Classification: 351 Deckenkonstruktionen (Classification DIN 267:2018-12); Decke (ARCHICAD Klassifizierung); Material: 05_ALLGEMEIN - TRAGENDE BAUTEILE 0.318564 m
AC_Pset_RenovationAndPhasing - Renovation Status: Existing
Pset_SlabCommon - LoadBearing: no; IsExternal: no

# IfcSlab: 05_ALLGEMEIN - TRAGENDE BAUTEILE 320 (14)
Classification: 351 Deckenkonstruktionen (Classification DIN 267:2018-12); Decke (ARCHICAD Klassifizierung)
AC_Pset_RenovationAndPhasing - Renovation Status: Existing
Pset_SlabCommon - LoadBearing: no; IsExternal: no
Name | In | Material
2 x Belag-017 | 2.OBERGESCHOSS | 05_ALLGEMEIN - TRAGENDE BAUTEILE 0.32 m
Belag-020 | 2.OBERGESCHOSS | 05_ALLGEMEIN - TRAGENDE BAUTEILE 0.32 m
3 x Belag-004 | ERDGESCHOSS | 05_ALLGEMEIN - TRAGENDE BAUTEILE 0.32 m
Belag-005 | ERDGESCHOSS | 05_ALLGEMEIN - TRAGENDE BAUTEILE 0.32 m
Belag-003 | KELLERGESCHOSS | 05_ALLGEMEIN - TRAGENDE BAUTEILE 0.319572 m
4 x Belag-003 | KELLERGESCHOSS | 05_ALLGEMEIN - TRAGENDE BAUTEILE 0.32 m
2 x Belag-004 | KELLERGESCHOSS | 05_ALLGEMEIN - TRAGENDE BAUTEILE 0.32 m

# IfcSlab: 05_ALLGEMEIN - TRAGENDE BAUTEILE 326, Belag-003
In: KELLERGESCHOSS
Classification: 351 Deckenkonstruktionen (Classification DIN 267:2018-12); Decke (ARCHICAD Klassifizierung); Material: 05_ALLGEMEIN - TRAGENDE BAUTEILE 0.325632 m
AC_Pset_RenovationAndPhasing - Renovation Status: Existing
Pset_SlabCommon - LoadBearing: no; IsExternal: no

# IfcSlab: 05_ALLGEMEIN - TRAGENDE BAUTEILE 329 (3)
In: KELLERGESCHOSS
Classification: 351 Deckenkonstruktionen (Classification DIN 267:2018-12); Decke (ARCHICAD Klassifizierung); Material: 05_ALLGEMEIN - TRAGENDE BAUTEILE 0.328814 m
AC_Pset_RenovationAndPhasing - Renovation Status: Existing
Pset_SlabCommon - LoadBearing: no; IsExternal: no
Name
Belag-003
2 x Belag-004

# IfcSlab: 05_ALLGEMEIN - TRAGENDE BAUTEILE 330 (19)
Classification: 351 Deckenkonstruktionen (Classification DIN 267:2018-12); Decke (ARCHICAD Klassifizierung); Material: 05_ALLGEMEIN - TRAGENDE BAUTEILE 0.33 m
AC_Pset_RenovationAndPhasing - Renovation Status: Existing
Pset_SlabCommon - LoadBearing: no; IsExternal: no
Name | In
9 x Belag-016 | 2.OBERGESCHOSS
3 x Belag-017 | 2.OBERGESCHOSS
2 x Belag-018 | 2.OBERGESCHOSS
Belag-019 | 2.OBERGESCHOSS
2 x Belag-005 | KELLERGESCHOSS
Belag-006 | KELLERGESCHOSS
Belag-007 | KELLERGESCHOSS

# IfcSlab: 05_ALLGEMEIN - TRAGENDE BAUTEILE 340 (5)
Classification: 351 Deckenkonstruktionen (Classification DIN 267:2018-12); Decke (ARCHICAD Klassifizierung); Material: 05_ALLGEMEIN - TRAGENDE BAUTEILE 0.34 m
AC_Pset_RenovationAndPhasing - Renovation Status: Existing
Pset_SlabCommon - LoadBearing: no; IsExternal: no
Name | In
2 x Belag-004 | ERDGESCHOSS
2 x Belag-005 | KELLERGESCHOSS
Belag-006 | KELLERGESCHOSS

# IfcSlab: 05_ALLGEMEIN - TRAGENDE BAUTEILE 346 (2)
In: KELLERGESCHOSS
Classification: 351 Deckenkonstruktionen (Classification DIN 267:2018-12); Decke (ARCHICAD Klassifizierung); Material: 05_ALLGEMEIN - TRAGENDE BAUTEILE 0.345581 m
AC_Pset_RenovationAndPhasing - Renovation Status: Existing
Pset_SlabCommon - LoadBearing: no; IsExternal: no

# IfcSlab: 05_ALLGEMEIN - TRAGENDE BAUTEILE 350 (8)
Classification: 351 Deckenkonstruktionen (Classification DIN 267:2018-12); Decke (ARCHICAD Klassifizierung); Material: 05_ALLGEMEIN - TRAGENDE BAUTEILE 0.35 m
AC_Pset_RenovationAndPhasing - Renovation Status: Existing
Pset_SlabCommon - LoadBearing: no; IsExternal: no
Name | In
Belag-021 | 2.OBERGESCHOSS
Belag-022 | 2.OBERGESCHOSS
2 x Belag-004 | KELLERGESCHOSS
Belag-005 | KELLERGESCHOSS
Belag-008 | KELLERGESCHOSS
Belag-009 | KELLERGESCHOSS
Belag-014 | KELLERGESCHOSS

# IfcSlab: 05_ALLGEMEIN - TRAGENDE BAUTEILE 357, Belag-029
In: 1.OBERGESCHOSS
Classification: 351 Deckenkonstruktionen (Classification DIN 267:2018-12); Decke (ARCHICAD Klassifizierung); Material: 05_ALLGEMEIN - TRAGENDE BAUTEILE 0.356605 m
AC_Pset_RenovationAndPhasing - Renovation Status: Existing
Pset_SlabCommon - LoadBearing: no; IsExternal: no

# IfcSlab: 05_ALLGEMEIN - TRAGENDE BAUTEILE 358, Belag-011
In: KELLERGESCHOSS
Classification: 351 Deckenkonstruktionen (Classification DIN 267:2018-12); Decke (ARCHICAD Klassifizierung); Material: 05_ALLGEMEIN - TRAGENDE BAUTEILE 0.358228 m
AC_Pset_RenovationAndPhasing - Renovation Status: Existing
Pset_SlabCommon - LoadBearing: no; IsExternal: no

# IfcSlab: 05_ALLGEMEIN - TRAGENDE BAUTEILE 360 (5)
Classification: 351 Deckenkonstruktionen (Classification DIN 267:2018-12); Decke (ARCHICAD Klassifizierung); Material: 05_ALLGEMEIN - TRAGENDE BAUTEILE 0.36 m
AC_Pset_RenovationAndPhasing - Renovation Status: Existing
Pset_SlabCommon - LoadBearing: no; IsExternal: no
Name | In
Belag-039 | 1.OBERGESCHOSS
Belag-040 | 1.OBERGESCHOSS
2 x Belag-004 | KELLERGESCHOSS
Belag-010 | KELLERGESCHOSS

# IfcSlab: 05_ALLGEMEIN - TRAGENDE BAUTEILE 361, Belag-003
In: ERDGESCHOSS
Classification: 351 Deckenkonstruktionen (Classification DIN 267:2018-12); Decke (ARCHICAD Klassifizierung); Material: 05_ALLGEMEIN - TRAGENDE BAUTEILE 0.360708 m
AC_Pset_RenovationAndPhasing - Renovation Status: Existing
Pset_SlabCommon - LoadBearing: no; IsExternal: no

# IfcSlab: 05_ALLGEMEIN - TRAGENDE BAUTEILE 370 (3)
Classification: 351 Deckenkonstruktionen (Classification DIN 267:2018-12); Decke (ARCHICAD Klassifizierung); Material: 05_ALLGEMEIN - TRAGENDE BAUTEILE 0.37 m
AC_Pset_RenovationAndPhasing - Renovation Status: Existing
Pset_SlabCommon - LoadBearing: no; IsExternal: no
Name | In
Belag-017 | 2.OBERGESCHOSS
Belag-006 | ERDGESCHOSS
Belag-004 | KELLERGESCHOSS

# IfcSlab: 05_ALLGEMEIN - TRAGENDE BAUTEILE 373, Belag-009
In: ERDGESCHOSS
Classification: 351 Deckenkonstruktionen (Classification DIN 267:2018-12); Decke (ARCHICAD Klassifizierung); Material: 05_ALLGEMEIN - TRAGENDE BAUTEILE 0.3725 m
AC_Pset_RenovationAndPhasing - Renovation Status: Existing
Pset_SlabCommon - LoadBearing: no; IsExternal: no

# IfcSlab: 05_ALLGEMEIN - TRAGENDE BAUTEILE 380, Belag-039
In: 1.OBERGESCHOSS
Classification: 351 Deckenkonstruktionen (Classification DIN 267:2018-12); Decke (ARCHICAD Klassifizierung); Material: 05_ALLGEMEIN - TRAGENDE BAUTEILE 0.38 m
AC_Pset_RenovationAndPhasing - Renovation Status: Existing
Pset_SlabCommon - LoadBearing: no; IsExternal: no

# IfcSlab: 05_ALLGEMEIN - TRAGENDE BAUTEILE 385, Belag-004
In: KELLERGESCHOSS
Classification: 351 Deckenkonstruktionen (Classification DIN 267:2018-12); Decke (ARCHICAD Klassifizierung); Material: 05_ALLGEMEIN - TRAGENDE BAUTEILE 0.385308 m
AC_Pset_RenovationAndPhasing - Renovation Status: Existing
Pset_SlabCommon - LoadBearing: no; IsExternal: no

# IfcSlab: 05_ALLGEMEIN - TRAGENDE BAUTEILE 386, Belag-010
In: ERDGESCHOSS
Classification: 351 Deckenkonstruktionen (Classification DIN 267:2018-12); Decke (ARCHICAD Klassifizierung); Material: 05_ALLGEMEIN - TRAGENDE BAUTEILE 0.38625 m
AC_Pset_RenovationAndPhasing - Renovation Status: Existing
Pset_SlabCommon - LoadBearing: no; IsExternal: no

# IfcSlab: 05_ALLGEMEIN - TRAGENDE BAUTEILE 388 (2)
In: KELLERGESCHOSS
Classification: 351 Deckenkonstruktionen (Classification DIN 267:2018-12); Decke (ARCHICAD Klassifizierung); Material: 05_ALLGEMEIN - TRAGENDE BAUTEILE 0.38764 m
AC_Pset_RenovationAndPhasing - Renovation Status: Existing
Pset_SlabCommon - LoadBearing: no; IsExternal: no

# IfcSlab: 05_ALLGEMEIN - TRAGENDE BAUTEILE 390, Belag-004
In: ERDGESCHOSS
Classification: 351 Deckenkonstruktionen (Classification DIN 267:2018-12); Decke (ARCHICAD Klassifizierung); Material: 05_ALLGEMEIN - TRAGENDE BAUTEILE 0.39 m
AC_Pset_RenovationAndPhasing - Renovation Status: Existing
Pset_SlabCommon - LoadBearing: no; IsExternal: no

# IfcSlab: 05_ALLGEMEIN - TRAGENDE BAUTEILE 397, Belag-003
In: KELLERGESCHOSS
Classification: 351 Deckenkonstruktionen (Classification DIN 267:2018-12); Decke (ARCHICAD Klassifizierung); Material: 05_ALLGEMEIN - TRAGENDE BAUTEILE 0.397278 m
AC_Pset_RenovationAndPhasing - Renovation Status: Existing
Pset_SlabCommon - LoadBearing: no; IsExternal: no

# IfcSlab: 05_ALLGEMEIN - TRAGENDE BAUTEILE 400, Belag-017
In: ERDGESCHOSS
Classification: 351 Deckenkonstruktionen (Classification DIN 267:2018-12); Decke (ARCHICAD Klassifizierung); Material: 05_ALLGEMEIN - TRAGENDE BAUTEILE 0.4 m
AC_Pset_RenovationAndPhasing - Renovation Status: Existing
Pset_SlabCommon - LoadBearing: no; IsExternal: no

# IfcSlab: 05_ALLGEMEIN - TRAGENDE BAUTEILE 410, Belag-039
In: 1.OBERGESCHOSS
Classification: 351 Deckenkonstruktionen (Classification DIN 267:2018-12); Decke (ARCHICAD Klassifizierung); Material: 05_ALLGEMEIN - TRAGENDE BAUTEILE 0.41 m
AC_Pset_RenovationAndPhasing - Renovation Status: Existing
Pset_SlabCommon - LoadBearing: no; IsExternal: no

# IfcSlab: 05_ALLGEMEIN - TRAGENDE BAUTEILE 430 (4)
In: 1.OBERGESCHOSS
Classification: 351 Deckenkonstruktionen (Classification DIN 267:2018-12); Decke (ARCHICAD Klassifizierung); Material: 05_ALLGEMEIN - TRAGENDE BAUTEILE 0.43 m
AC_Pset_RenovationAndPhasing - Renovation Status: Existing
Pset_SlabCommon - LoadBearing: no; IsExternal: no

# IfcSlab: 05_ALLGEMEIN - TRAGENDE BAUTEILE 450 (2)
In: KELLERGESCHOSS
Classification: 351 Deckenkonstruktionen (Classification DIN 267:2018-12); Decke (ARCHICAD Klassifizierung); Material: 05_ALLGEMEIN - TRAGENDE BAUTEILE 0.45 m
AC_Pset_RenovationAndPhasing - Renovation Status: Existing
Pset_SlabCommon - LoadBearing: no; IsExternal: no
Name
Belag-016
Belag-017

# IfcSlab: 05_ALLGEMEIN - TRAGENDE BAUTEILE 460 (3)
In: KELLERGESCHOSS
Classification: 351 Deckenkonstruktionen (Classification DIN 267:2018-12); Decke (ARCHICAD Klassifizierung); Material: 05_ALLGEMEIN - TRAGENDE BAUTEILE 0.46 m
AC_Pset_RenovationAndPhasing - Renovation Status: Existing
Pset_SlabCommon - LoadBearing: no; IsExternal: no
Name
Belag-011
Belag-012
Belag-015

# IfcSlab: 05_ALLGEMEIN - TRAGENDE BAUTEILE 465, Belag-010
In: KELLERGESCHOSS
Classification: 351 Deckenkonstruktionen (Classification DIN 267:2018-12); Decke (ARCHICAD Klassifizierung); Material: 05_ALLGEMEIN - TRAGENDE BAUTEILE 0.465457 m
AC_Pset_RenovationAndPhasing - Renovation Status: Existing
Pset_SlabCommon - LoadBearing: no; IsExternal: no

# IfcSlab: 05_ALLGEMEIN - TRAGENDE BAUTEILE 480 (3)
Classification: 351 Deckenkonstruktionen (Classification DIN 267:2018-12); Decke (ARCHICAD Klassifizierung); Material: 05_ALLGEMEIN - TRAGENDE BAUTEILE 0.48 m
AC_Pset_RenovationAndPhasing - Renovation Status: Existing
Pset_SlabCommon - LoadBearing: no; IsExternal: no
Name | In
Belag-004 | ERDGESCHOSS
Belag-018 | KELLERGESCHOSS
Belag-019 | KELLERGESCHOSS

# IfcSlab: 05_ALLGEMEIN - TRAGENDE BAUTEILE 50, Belag-017
In: 2.OBERGESCHOSS
Classification: 351 Deckenkonstruktionen (Classification DIN 267:2018-12); Decke (ARCHICAD Klassifizierung); Material: 05_ALLGEMEIN - TRAGENDE BAUTEILE 0.050355 m
AC_Pset_RenovationAndPhasing - Renovation Status: Existing
Pset_SlabCommon - LoadBearing: no; IsExternal: no

# IfcSlab: 05_ALLGEMEIN - TRAGENDE BAUTEILE 500 (3)
Classification: 351 Deckenkonstruktionen (Classification DIN 267:2018-12); Decke (ARCHICAD Klassifizierung); Material: 05_ALLGEMEIN - TRAGENDE BAUTEILE 0.5 m
AC_Pset_RenovationAndPhasing - Renovation Status: Existing
Pset_SlabCommon - LoadBearing: no; IsExternal: no
Name | In
2 x Belag-039 | 1.OBERGESCHOSS
Belag-004 | ERDGESCHOSS

# IfcSlab: 05_ALLGEMEIN - TRAGENDE BAUTEILE 510, Belag-039
In: 1.OBERGESCHOSS
Classification: 351 Deckenkonstruktionen (Classification DIN 267:2018-12); Decke (ARCHICAD Klassifizierung); Material: 05_ALLGEMEIN - TRAGENDE BAUTEILE 0.51 m
AC_Pset_RenovationAndPhasing - Renovation Status: Existing
Pset_SlabCommon - LoadBearing: no; IsExternal: no

# IfcSlab: 05_ALLGEMEIN - TRAGENDE BAUTEILE 530, Belag-023
In: KELLERGESCHOSS
Classification: 351 Deckenkonstruktionen (Classification DIN 267:2018-12); Decke (ARCHICAD Klassifizierung); Material: 05_ALLGEMEIN - TRAGENDE BAUTEILE 0.53 m
AC_Pset_RenovationAndPhasing - Renovation Status: Existing
Pset_SlabCommon - LoadBearing: no; IsExternal: no

# IfcSlab: 05_ALLGEMEIN - TRAGENDE BAUTEILE 532, Belag-004
In: 2.OBERGESCHOSS
Classification: 351 Deckenkonstruktionen (Classification DIN 267:2018-12); Decke (ARCHICAD Klassifizierung); Material: 05_ALLGEMEIN - TRAGENDE BAUTEILE 0.532429 m
AC_Pset_RenovationAndPhasing - Renovation Status: Existing
Pset_SlabCommon - LoadBearing: no; IsExternal: no

# IfcSlab: 05_ALLGEMEIN - TRAGENDE BAUTEILE 533, Belag-029
In: 1.OBERGESCHOSS
Classification: 351 Deckenkonstruktionen (Classification DIN 267:2018-12); Decke (ARCHICAD Klassifizierung); Material: 05_ALLGEMEIN - TRAGENDE BAUTEILE 0.532779 m
AC_Pset_RenovationAndPhasing - Renovation Status: Existing
Pset_SlabCommon - LoadBearing: no; IsExternal: no

# IfcSlab: 05_ALLGEMEIN - TRAGENDE BAUTEILE 550, Belag-013
In: KELLERGESCHOSS
Classification: 351 Deckenkonstruktionen (Classification DIN 267:2018-12); Decke (ARCHICAD Klassifizierung); Material: 05_ALLGEMEIN - TRAGENDE BAUTEILE 0.55 m
AC_Pset_RenovationAndPhasing - Renovation Status: Existing
Pset_SlabCommon - LoadBearing: no; IsExternal: no

# IfcSlab: 05_ALLGEMEIN - TRAGENDE BAUTEILE 560 (3)
Classification: 351 Deckenkonstruktionen (Classification DIN 267:2018-12); Decke (ARCHICAD Klassifizierung); Material: 05_ALLGEMEIN - TRAGENDE BAUTEILE 0.56 m
AC_Pset_RenovationAndPhasing - Renovation Status: Existing
Pset_SlabCommon - LoadBearing: no; IsExternal: no
Name | In
Belag-017 | 2.OBERGESCHOSS
Belag-015 | KELLERGESCHOSS
Belag-023 | KELLERGESCHOSS

# IfcSlab: 05_ALLGEMEIN - TRAGENDE BAUTEILE 570 (2)
Classification: 351 Deckenkonstruktionen (Classification DIN 267:2018-12); Decke (ARCHICAD Klassifizierung); Material: 05_ALLGEMEIN - TRAGENDE BAUTEILE 0.57 m
AC_Pset_RenovationAndPhasing - Renovation Status: Existing
Pset_SlabCommon - LoadBearing: no; IsExternal: no
Name | In
Belag-039 | 1.OBERGESCHOSS
Belag-011 | KELLERGESCHOSS

# IfcSlab: 05_ALLGEMEIN - TRAGENDE BAUTEILE 582, Belag-012
In: KELLERGESCHOSS
Classification: 351 Deckenkonstruktionen (Classification DIN 267:2018-12); Decke (ARCHICAD Klassifizierung); Material: 05_ALLGEMEIN - TRAGENDE BAUTEILE 0.582052 m
AC_Pset_RenovationAndPhasing - Renovation Status: Existing
Pset_SlabCommon - LoadBearing: no; IsExternal: no

# IfcSlab: 05_ALLGEMEIN - TRAGENDE BAUTEILE 610, Belag-036
In: 1.OBERGESCHOSS
Classification: 351 Deckenkonstruktionen (Classification DIN 267:2018-12); Decke (ARCHICAD Klassifizierung); Material: 05_ALLGEMEIN - TRAGENDE BAUTEILE 0.61 m
AC_Pset_RenovationAndPhasing - Renovation Status: Existing
Pset_SlabCommon - LoadBearing: no; IsExternal: no

# IfcSlab: 05_ALLGEMEIN - TRAGENDE BAUTEILE 630, Belag-005
In: KELLERGESCHOSS
Classification: 351 Deckenkonstruktionen (Classification DIN 267:2018-12); Decke (ARCHICAD Klassifizierung); Material: 05_ALLGEMEIN - TRAGENDE BAUTEILE 0.63 m
AC_Pset_RenovationAndPhasing - Renovation Status: Existing
Pset_SlabCommon - LoadBearing: no; IsExternal: no

# IfcSlab: 05_ALLGEMEIN - TRAGENDE BAUTEILE 660 (2)
In: KELLERGESCHOSS
Classification: 351 Deckenkonstruktionen (Classification DIN 267:2018-12); Decke (ARCHICAD Klassifizierung); Material: 05_ALLGEMEIN - TRAGENDE BAUTEILE 0.66 m
AC_Pset_RenovationAndPhasing - Renovation Status: Existing
Pset_SlabCommon - LoadBearing: no; IsExternal: no
Name
Belag-005
Belag-017

# IfcSlab: 05_ALLGEMEIN - TRAGENDE BAUTEILE 670 (3)
In: 1.OBERGESCHOSS
Classification: 351 Deckenkonstruktionen (Classification DIN 267:2018-12); Decke (ARCHICAD Klassifizierung); Material: 05_ALLGEMEIN - TRAGENDE BAUTEILE 0.67 m
AC_Pset_RenovationAndPhasing - Renovation Status: Existing
Pset_SlabCommon - LoadBearing: no; IsExternal: no
Name
2 x Belag-039
Belag-041

# IfcSlab: 05_ALLGEMEIN - TRAGENDE BAUTEILE 680, Belag-042
In: 1.OBERGESCHOSS
Classification: 351 Deckenkonstruktionen (Classification DIN 267:2018-12); Decke (ARCHICAD Klassifizierung); Material: 05_ALLGEMEIN - TRAGENDE BAUTEILE 0.68 m
AC_Pset_RenovationAndPhasing - Renovation Status: Existing
Pset_SlabCommon - LoadBearing: no; IsExternal: no

# IfcSlab: 05_ALLGEMEIN - TRAGENDE BAUTEILE 687, Belag-017
In: 1.OBERGESCHOSS
Classification: 351 Deckenkonstruktionen (Classification DIN 267:2018-12); Decke (ARCHICAD Klassifizierung); Material: 05_ALLGEMEIN - TRAGENDE BAUTEILE 0.686814 m
AC_Pset_RenovationAndPhasing - Renovation Status: Existing
Pset_SlabCommon - LoadBearing: no; IsExternal: no

# IfcSlab: 05_ALLGEMEIN - TRAGENDE BAUTEILE 690, Belag-034
In: 1.OBERGESCHOSS
Classification: 351 Deckenkonstruktionen (Classification DIN 267:2018-12); Decke (ARCHICAD Klassifizierung); Material: 05_ALLGEMEIN - TRAGENDE BAUTEILE 0.69 m
AC_Pset_RenovationAndPhasing - Renovation Status: Existing
Pset_SlabCommon - LoadBearing: no; IsExternal: no

# IfcSlab: 05_ALLGEMEIN - TRAGENDE BAUTEILE 70 (4)
Classification: 351 Deckenkonstruktionen (Classification DIN 267:2018-12); Decke (ARCHICAD Klassifizierung); Material: 05_ALLGEMEIN - TRAGENDE BAUTEILE 0.07 m
AC_Pset_RenovationAndPhasing - Renovation Status: Existing
Pset_SlabCommon - LoadBearing: no; IsExternal: no
Name | In
Belag-022 | 1.OBERGESCHOSS
Belag-005 | KELLERGESCHOSS
Belag-006 | KELLERGESCHOSS
Belag-009 | KELLERGESCHOSS

# IfcSlab: 05_ALLGEMEIN - TRAGENDE BAUTEILE 700 (2)
Classification: 351 Deckenkonstruktionen (Classification DIN 267:2018-12); Decke (ARCHICAD Klassifizierung); Material: 05_ALLGEMEIN - TRAGENDE BAUTEILE 0.7 m
AC_Pset_RenovationAndPhasing - Renovation Status: Existing
Pset_SlabCommon - LoadBearing: no; IsExternal: no
Name | In
Belag-039 | 1.OBERGESCHOSS
Belag-025 | KELLERGESCHOSS

# IfcSlab: 05_ALLGEMEIN - TRAGENDE BAUTEILE 710, Belag-035
In: 1.OBERGESCHOSS
Classification: 351 Deckenkonstruktionen (Classification DIN 267:2018-12); Decke (ARCHICAD Klassifizierung); Material: 05_ALLGEMEIN - TRAGENDE BAUTEILE 0.71 m
AC_Pset_RenovationAndPhasing - Renovation Status: Existing
Pset_SlabCommon - LoadBearing: no; IsExternal: no

# IfcSlab: 05_ALLGEMEIN - TRAGENDE BAUTEILE 750, Belag-039
In: 1.OBERGESCHOSS
Classification: 351 Deckenkonstruktionen (Classification DIN 267:2018-12); Decke (ARCHICAD Klassifizierung); Material: 05_ALLGEMEIN - TRAGENDE BAUTEILE 0.75 m
AC_Pset_RenovationAndPhasing - Renovation Status: Existing
Pset_SlabCommon - LoadBearing: no; IsExternal: no

# IfcSlab: 05_ALLGEMEIN - TRAGENDE BAUTEILE 780, Belag-024
In: KELLERGESCHOSS
Classification: 351 Deckenkonstruktionen (Classification DIN 267:2018-12); Decke (ARCHICAD Klassifizierung); Material: 05_ALLGEMEIN - TRAGENDE BAUTEILE 0.78 m
AC_Pset_RenovationAndPhasing - Renovation Status: Existing
Pset_SlabCommon - LoadBearing: no; IsExternal: no

# IfcSlab: 05_ALLGEMEIN - TRAGENDE BAUTEILE 782, Belag-018
In: 2.OBERGESCHOSS
Classification: 351 Deckenkonstruktionen (Classification DIN 267:2018-12); Decke (ARCHICAD Klassifizierung); Material: 05_ALLGEMEIN - TRAGENDE BAUTEILE 0.782212 m
AC_Pset_RenovationAndPhasing - Renovation Status: Existing
Pset_SlabCommon - LoadBearing: no; IsExternal: no

# IfcSlab: 05_ALLGEMEIN - TRAGENDE BAUTEILE 800 (2)
In: 1.OBERGESCHOSS
Classification: 351 Deckenkonstruktionen (Classification DIN 267:2018-12); Decke (ARCHICAD Klassifizierung); Material: 05_ALLGEMEIN - TRAGENDE BAUTEILE 0.8 m
AC_Pset_RenovationAndPhasing - Renovation Status: Existing
Pset_SlabCommon - LoadBearing: no; IsExternal: no

# IfcSlab: 05_ALLGEMEIN - TRAGENDE BAUTEILE 820 (7)
Classification: 351 Deckenkonstruktionen (Classification DIN 267:2018-12); Decke (ARCHICAD Klassifizierung); Material: 05_ALLGEMEIN - TRAGENDE BAUTEILE 0.82 m
AC_Pset_RenovationAndPhasing - Renovation Status: Existing
Pset_SlabCommon - LoadBearing: no; IsExternal: no
Name | In
Belag-039 | 1.OBERGESCHOSS
Belag-040 | 1.OBERGESCHOSS
Belag-041 | 1.OBERGESCHOSS
Belag-043 | 1.OBERGESCHOSS
2 x Belag-005 | ERDGESCHOSS
Belag-023 | KELLERGESCHOSS

# IfcSlab: 05_ALLGEMEIN - TRAGENDE BAUTEILE 830, Belag-003
In: ERDGESCHOSS
Classification: 351 Deckenkonstruktionen (Classification DIN 267:2018-12); Decke (ARCHICAD Klassifizierung); Material: 05_ALLGEMEIN - TRAGENDE BAUTEILE 0.830188 m
AC_Pset_RenovationAndPhasing - Renovation Status: Existing
Pset_SlabCommon - LoadBearing: no; IsExternal: no

# IfcSlab: 05_ALLGEMEIN - TRAGENDE BAUTEILE 85, Belag-004
In: ERDGESCHOSS
Classification: 351 Deckenkonstruktionen (Classification DIN 267:2018-12); Decke (ARCHICAD Klassifizierung); Material: 05_ALLGEMEIN - TRAGENDE BAUTEILE 0.085 m
AC_Pset_RenovationAndPhasing - Renovation Status: Existing
Pset_SlabCommon - LoadBearing: no; IsExternal: no

# IfcSlab: 05_ALLGEMEIN - TRAGENDE BAUTEILE 850, Belag-040
In: 1.OBERGESCHOSS
Classification: 351 Deckenkonstruktionen (Classification DIN 267:2018-12); Decke (ARCHICAD Klassifizierung); Material: 05_ALLGEMEIN - TRAGENDE BAUTEILE 0.85 m
AC_Pset_RenovationAndPhasing - Renovation Status: Existing
Pset_SlabCommon - LoadBearing: no; IsExternal: no

# IfcSlab: 05_ALLGEMEIN - TRAGENDE BAUTEILE 860 (3)
Classification: 351 Deckenkonstruktionen (Classification DIN 267:2018-12); Decke (ARCHICAD Klassifizierung); Material: 05_ALLGEMEIN - TRAGENDE BAUTEILE 0.86 m
AC_Pset_RenovationAndPhasing - Renovation Status: Existing
Pset_SlabCommon - LoadBearing: no; IsExternal: no
Name | In
Belag-039 | 1.OBERGESCHOSS
2 x Belag-005 | KELLERGESCHOSS

# IfcSlab: 05_ALLGEMEIN - TRAGENDE BAUTEILE 90 (9)
Classification: 351 Deckenkonstruktionen (Classification DIN 267:2018-12); Decke (ARCHICAD Klassifizierung)
AC_Pset_RenovationAndPhasing - Renovation Status: Existing
Pset_SlabCommon - LoadBearing: no; IsExternal: no
Name | In | Material
Belag-005 | 1.OBERGESCHOSS | 05_ALLGEMEIN - TRAGENDE BAUTEILE 0.0901177 m
2 x Belag-003 | ERDGESCHOSS | 05_ALLGEMEIN - TRAGENDE BAUTEILE 0.09 m
4 x Belag-004 | ERDGESCHOSS | 05_ALLGEMEIN - TRAGENDE BAUTEILE 0.09 m
Belag-015 | ERDGESCHOSS | 05_ALLGEMEIN - TRAGENDE BAUTEILE 0.09 m
Belag-014 | KELLERGESCHOSS | 05_ALLGEMEIN - TRAGENDE BAUTEILE 0.09 m

# IfcSlab: 05_ALLGEMEIN - TRAGENDE BAUTEILE 910 (4)
In: 1.OBERGESCHOSS
Classification: 351 Deckenkonstruktionen (Classification DIN 267:2018-12); Decke (ARCHICAD Klassifizierung); Material: 05_ALLGEMEIN - TRAGENDE BAUTEILE 0.91 m
AC_Pset_RenovationAndPhasing - Renovation Status: Existing
Pset_SlabCommon - LoadBearing: no; IsExternal: no
Name
3 x Belag-037
Belag-040

# IfcSlab: 05_ALLGEMEIN - TRAGENDE BAUTEILE 93, Belag-030
In: 1.OBERGESCHOSS
Classification: 351 Deckenkonstruktionen (Classification DIN 267:2018-12); Decke (ARCHICAD Klassifizierung); Material: 05_ALLGEMEIN - TRAGENDE BAUTEILE 0.0925043 m
AC_Pset_RenovationAndPhasing - Renovation Status: Existing
Pset_SlabCommon - LoadBearing: no; IsExternal: no

# IfcSlab: 05_ALLGEMEIN - TRAGENDE BAUTEILE 950, Belag-004
In: KELLERGESCHOSS
Classification: 351 Deckenkonstruktionen (Classification DIN 267:2018-12); Decke (ARCHICAD Klassifizierung); Material: 05_ALLGEMEIN - TRAGENDE BAUTEILE 0.95 m
AC_Pset_RenovationAndPhasing - Renovation Status: Existing
Pset_SlabCommon - LoadBearing: no; IsExternal: no

# IfcSlab: 05_ALLGEMEIN - TRAGENDE BAUTEILE 960 (2)
Classification: 351 Deckenkonstruktionen (Classification DIN 267:2018-12); Decke (ARCHICAD Klassifizierung); Material: 05_ALLGEMEIN - TRAGENDE BAUTEILE 0.96 m
AC_Pset_RenovationAndPhasing - Renovation Status: Existing
Pset_SlabCommon - LoadBearing: no; IsExternal: no
Name | In
Belag-042 | 1.OBERGESCHOSS
Belag-004 | KELLERGESCHOSS

# IfcSlab: 29_Dach, Dachziegel rot 10 (35)
Type - PredefinedType: ROOF
Classification: Dach (ARCHICAD Klassifizierung); 363 Dachbeläge (Classification DIN 267:2018-12)
Pset_SlabCommon - ThermalTransmittance: 0; LoadBearing: yes; IsExternal: yes
AC_Pset_RenovationAndPhasing - Renovation Status: Existing
Name | In | Material
2 x Dach-011 | SPITZBODEN | 29_Dach, Dachziegel rot
10 x Dach-012 | SPITZBODEN | 29_Dach, Dachziegel rot
Dach-014 | SPITZBODEN | 29_Dach, Dachziegel rot
2 x Dach-015 | SPITZBODEN | 29_Dach, Dachziegel rot
2 x Dach-016 | SPITZBODEN | 29_Dach, Dachziegel rot
2 x Dach-017 | SPITZBODEN | 29_Dach, Dachziegel rot
Dach-018 | SPITZBODEN | 29_Dach, Dachziegel rot
3 x Dach-019 | SPITZBODEN | 29_Dach, Dachziegel rot
Dach-020 | SPITZBODEN | 29_Dach, Dachziegel rot
6 x Dach-011 | DACHGESCHOSS | 29_Dach, Dachziegel rot 0.01 m
Dach-011 | DACHGESCHOSS | 29_Dach, Dachziegel rot
2 x Dach-012 | DACHGESCHOSS | 29_Dach, Dachziegel rot
2 x Dach-012 | 2.OBERGESCHOSS | 29_Dach, Dachziegel rot

# IfcSlab: 29_Dach, Dachziegel rot 148 (4)
In: DACHGESCHOSS
Type - PredefinedType: ROOF
Classification: Dach (ARCHICAD Klassifizierung); 363 Dachbeläge (Classification DIN 267:2018-12); Material: 29_Dach, Dachziegel rot 0.147942 m
Pset_SlabCommon - ThermalTransmittance: 0; LoadBearing: yes; IsExternal: yes
AC_Pset_RenovationAndPhasing - Renovation Status: Existing
Name
Dach-016
2 x Dach-017
Dach-018

# IfcSlab: 29_Dach, Dachziegel rot 40, Dach-007
In: 1.OBERGESCHOSS
Type - PredefinedType: ROOF
Classification: Dach (ARCHICAD Klassifizierung); 363 Dachbeläge (Classification DIN 267:2018-12); Material: 29_Dach, Dachziegel rot 0.04 m
Pset_SlabCommon - ThermalTransmittance: 0; LoadBearing: yes; IsExternal: yes
AC_Pset_RenovationAndPhasing - Renovation Status: Existing

# IfcSlab: 29_Dach, Dachziegel rot 79, Dach-017
In: ERDGESCHOSS
Type - PredefinedType: ROOF
Classification: Dach (ARCHICAD Klassifizierung); 363 Dachbeläge (Classification DIN 267:2018-12); Material: 29_Dach, Dachziegel rot 0.0788643 m
Pset_SlabCommon - ThermalTransmittance: 0; LoadBearing: yes; IsExternal: yes
AC_Pset_RenovationAndPhasing - Renovation Status: Existing

# IfcSlab: 29_Dach, Dachziegel rot 80 (49)
Type - PredefinedType: ROOF
Classification: Dach (ARCHICAD Klassifizierung); 363 Dachbeläge (Classification DIN 267:2018-12)
Pset_SlabCommon - ThermalTransmittance: 0; LoadBearing: yes; IsExternal: yes
AC_Pset_RenovationAndPhasing - Renovation Status: Existing
Name | In | Material
2 x Dach-004 | SPITZBODEN | 29_Dach, Dachziegel rot
2 x Dach-004 | SPITZBODEN | 29_Dach, Dachziegel rot 0.08 m
3 x Dach-006 | SPITZBODEN | 29_Dach, Dachziegel rot
Dach-007 | SPITZBODEN | 29_Dach, Dachziegel rot
4 x Dach-006 | DACHGESCHOSS | 29_Dach, Dachziegel rot
Dach-007 | DACHGESCHOSS | 29_Dach, Dachziegel rot
4 x Dach-008 | DACHGESCHOSS | 29_Dach, Dachziegel rot
6 x Dach-009 | DACHGESCHOSS | 29_Dach, Dachziegel rot
4 x Dach-010 | DACHGESCHOSS | 29_Dach, Dachziegel rot
3 x Dach-012 | DACHGESCHOSS | 29_Dach, Dachziegel rot
2 x Dach-013 | DACHGESCHOSS | 29_Dach, Dachziegel rot
Dach-013 | DACHGESCHOSS | 29_Dach, Dachziegel rot 0.08 m
Dach-008 | 2.OBERGESCHOSS | 29_Dach, Dachziegel rot
Dach-009 | 2.OBERGESCHOSS | 29_Dach, Dachziegel rot
Dach-014 | 2.OBERGESCHOSS | 29_Dach, Dachziegel rot
Dach-015 | 2.OBERGESCHOSS | 29_Dach, Dachziegel rot
Dach-010 | 1.OBERGESCHOSS | 29_Dach, Dachziegel rot
Dach-001 | ERDGESCHOSS | 29_Dach, Dachziegel rot
2 x Dach-002 | ERDGESCHOSS | 29_Dach, Dachziegel rot
Dach-003 | ERDGESCHOSS | 29_Dach, Dachziegel rot
2 x Dach-004 | ERDGESCHOSS | 29_Dach, Dachziegel rot
3 x Dach-005 | ERDGESCHOSS | 29_Dach, Dachziegel rot
Dach-011 | KELLERGESCHOSS | 29_Dach, Dachziegel rot
Dach-012 | KELLERGESCHOSS | 29_Dach, Dachziegel rot

# IfcSlab: 48_Holz, Brettschichtholz 209 (2)
In: KELLERGESCHOSS
Classification: 351 Deckenkonstruktionen (Classification DIN 267:2018-12); Decke (ARCHICAD Klassifizierung); Material: 48_Holz, Brettschichtholz 0.208783 m
AC_Pset_RenovationAndPhasing - Renovation Status: Existing
Pset_SlabCommon - LoadBearing: no; IsExternal: no

# IfcSlab: 54_Metall, Edelstahl 30 (3)
In: ERDGESCHOSS
Classification: 351 Deckenkonstruktionen (Classification DIN 267:2018-12); Decke (ARCHICAD Klassifizierung); Material: 54_Metall, Edelstahl 0.03 m
AC_Pset_RenovationAndPhasing - Renovation Status: Existing
Pset_SlabCommon - LoadBearing: no; IsExternal: no

# IfcStair (21)
Classification: Treppe (ARCHICAD Klassifizierung); 544 Rampen, Treppen, Tribünen (Classification DIN 267:2018-12)
Pset_StairCommon - NumberOfTreads: 0; NumberOfRiser: 0; RequiredHeadroom: 2.2 m; IsExternal: no
AC_Pset_RenovationAndPhasing - Renovation Status: Existing
Name | In
Treppe-003 | DACHGESCHOSS
2 x Treppe-003 | 1.OBERGESCHOSS
Treppe-016 | 1.OBERGESCHOSS
7 x Treppe-003 | ERDGESCHOSS
10 x Treppe-003 | KELLERGESCHOSS

# IfcWall: 01_ALLGEMEIN - BAUTEIL 70 (3)
Type - PredefinedType: ELEMENTEDWALL
Classification: Elementwand (ARCHICAD Klassifizierung); Material: 01_ALLGEMEIN - BAUTEIL
Pset_WallCommon - ThermalTransmittance: 0; LoadBearing: yes; IsExternal: yes
AC_Pset_RenovationAndPhasing - Renovation Status: Existing
Name | In
Wand-030 | ERDGESCHOSS
Wand-030 | KELLERGESCHOSS
Wand-038 | KELLERGESCHOSS

# IfcWall: 01_ALLGEMEIN - BAUTEIL 80, Wand-038
In: KELLERGESCHOSS
Type - PredefinedType: ELEMENTEDWALL
Classification: Elementwand (ARCHICAD Klassifizierung); Material: 01_ALLGEMEIN - BAUTEIL
Pset_WallCommon - ThermalTransmittance: 0; LoadBearing: yes; IsExternal: yes
AC_Pset_RenovationAndPhasing - Renovation Status: Existing

# IfcWall: 01_ALLGEMEIN - BAUTEIL 82, Wand-038
In: KELLERGESCHOSS
Type - PredefinedType: ELEMENTEDWALL
Classification: Elementwand (ARCHICAD Klassifizierung); Material: 01_ALLGEMEIN - BAUTEIL
Pset_WallCommon - ThermalTransmittance: 0; LoadBearing: yes; IsExternal: yes
AC_Pset_RenovationAndPhasing - Renovation Status: Existing

# IfcWall: 05_ALLGEMEIN - TRAGENDE BAUTEILE, Wand-037
In: 2.OBERGESCHOSS
Type - PredefinedType: ELEMENTEDWALL
Classification: Elementwand (ARCHICAD Klassifizierung); Material: 05_ALLGEMEIN - TRAGENDE BAUTEILE
Pset_WallCommon - ThermalTransmittance: 0; LoadBearing: yes; IsExternal: yes
AC_Pset_RenovationAndPhasing - Renovation Status: Existing

# IfcWall: 05_ALLGEMEIN - TRAGENDE BAUTEILE 100 (2)
In: ERDGESCHOSS
Type - PredefinedType: ELEMENTEDWALL
Classification: Elementwand (ARCHICAD Klassifizierung); Material: 05_ALLGEMEIN - TRAGENDE BAUTEILE
Pset_WallCommon - ThermalTransmittance: 0; LoadBearing: yes; IsExternal: yes
AC_Pset_RenovationAndPhasing - Renovation Status: Existing
Name
Wand-031
Wand-033

# IfcWall: 05_ALLGEMEIN - TRAGENDE BAUTEILE 120 (3)
Type - PredefinedType: ELEMENTEDWALL
Classification: Elementwand (ARCHICAD Klassifizierung); Material: 05_ALLGEMEIN - TRAGENDE BAUTEILE
Pset_WallCommon - ThermalTransmittance: 0; LoadBearing: yes; IsExternal: yes
AC_Pset_RenovationAndPhasing - Renovation Status: Existing
Name | In
Wand-039 | 2.OBERGESCHOSS
Wand-037 | KELLERGESCHOSS
Wand-039 | KELLERGESCHOSS

# IfcWall: 05_ALLGEMEIN - TRAGENDE BAUTEILE 127 (2)
Type - PredefinedType: ELEMENTEDWALL
Classification: Elementwand (ARCHICAD Klassifizierung); Material: 05_ALLGEMEIN - TRAGENDE BAUTEILE
Pset_WallCommon - ThermalTransmittance: 0; LoadBearing: yes; IsExternal: yes
AC_Pset_RenovationAndPhasing - Renovation Status: Existing
Name | In
Wand-028 | ERDGESCHOSS
Wand-028 | KELLERGESCHOSS

# IfcWall: 05_ALLGEMEIN - TRAGENDE BAUTEILE 130 (2)
In: KELLERGESCHOSS
Type - PredefinedType: ELEMENTEDWALL
Classification: Elementwand (ARCHICAD Klassifizierung); Material: 05_ALLGEMEIN - TRAGENDE BAUTEILE
Pset_WallCommon - ThermalTransmittance: 0; LoadBearing: yes; IsExternal: yes
AC_Pset_RenovationAndPhasing - Renovation Status: Existing

# IfcWall: 05_ALLGEMEIN - TRAGENDE BAUTEILE 132 (6)
Type - PredefinedType: ELEMENTEDWALL
Classification: Elementwand (ARCHICAD Klassifizierung); Material: 05_ALLGEMEIN - TRAGENDE BAUTEILE
Pset_WallCommon - ThermalTransmittance: 0; LoadBearing: yes; IsExternal: yes
AC_Pset_RenovationAndPhasing - Renovation Status: Existing
Name | In
Wand-029 | ERDGESCHOSS
2 x Wand-029 | KELLERGESCHOSS
2 x Wand-030 | KELLERGESCHOSS
Wand-031 | KELLERGESCHOSS

# IfcWall: 05_ALLGEMEIN - TRAGENDE BAUTEILE 140 (2)
Type - PredefinedType: ELEMENTEDWALL
Classification: Elementwand (ARCHICAD Klassifizierung); Material: 05_ALLGEMEIN - TRAGENDE BAUTEILE
Pset_WallCommon - ThermalTransmittance: 0; LoadBearing: yes; IsExternal: yes
AC_Pset_RenovationAndPhasing - Renovation Status: Existing
Name | In
Wand-031 | DACHGESCHOSS
Wand-031 | 2.OBERGESCHOSS

# IfcWall: 05_ALLGEMEIN - TRAGENDE BAUTEILE 142, Wand-030
In: ERDGESCHOSS
Type - PredefinedType: ELEMENTEDWALL
Classification: Elementwand (ARCHICAD Klassifizierung); Material: 05_ALLGEMEIN - TRAGENDE BAUTEILE
Pset_WallCommon - ThermalTransmittance: 0; LoadBearing: yes; IsExternal: yes
AC_Pset_RenovationAndPhasing - Renovation Status: Existing

# IfcWall: 05_ALLGEMEIN - TRAGENDE BAUTEILE 150 (2)
In: KELLERGESCHOSS
Type - PredefinedType: ELEMENTEDWALL
Classification: Elementwand (ARCHICAD Klassifizierung); Material: 05_ALLGEMEIN - TRAGENDE BAUTEILE
Pset_WallCommon - ThermalTransmittance: 0; LoadBearing: yes; IsExternal: yes
AC_Pset_RenovationAndPhasing - Renovation Status: Existing

# IfcWall: 05_ALLGEMEIN - TRAGENDE BAUTEILE 200 (4)
Type - PredefinedType: ELEMENTEDWALL
Classification: Elementwand (ARCHICAD Klassifizierung); Material: 05_ALLGEMEIN - TRAGENDE BAUTEILE
Pset_WallCommon - ThermalTransmittance: 0; LoadBearing: yes; IsExternal: yes
AC_Pset_RenovationAndPhasing - Renovation Status: Existing
Name | In
Wand-031 | SPITZBODEN
2 x Wand-036 | 2.OBERGESCHOSS
Wand-035 | ERDGESCHOSS

# IfcWall: 05_ALLGEMEIN - TRAGENDE BAUTEILE 220 (3)
Type - PredefinedType: ELEMENTEDWALL
Classification: Elementwand (ARCHICAD Klassifizierung); Material: 05_ALLGEMEIN - TRAGENDE BAUTEILE
Pset_WallCommon - ThermalTransmittance: 0; LoadBearing: yes; IsExternal: yes
AC_Pset_RenovationAndPhasing - Renovation Status: Existing
Name | In
Wand-038 | DACHGESCHOSS
Wand-037 | 2.OBERGESCHOSS
Wand-038 | 2.OBERGESCHOSS

# IfcWall: 05_ALLGEMEIN - TRAGENDE BAUTEILE 230 (2)
In: DACHGESCHOSS
Type - PredefinedType: ELEMENTEDWALL
Classification: Elementwand (ARCHICAD Klassifizierung); Material: 05_ALLGEMEIN - TRAGENDE BAUTEILE
Pset_WallCommon - ThermalTransmittance: 0; LoadBearing: yes; IsExternal: yes
AC_Pset_RenovationAndPhasing - Renovation Status: Existing
Name
Wand-029
Wand-030

# IfcWall: 05_ALLGEMEIN - TRAGENDE BAUTEILE 240 (2)
In: KELLERGESCHOSS
Type - PredefinedType: ELEMENTEDWALL
Classification: Elementwand (ARCHICAD Klassifizierung); Material: 05_ALLGEMEIN - TRAGENDE BAUTEILE
Pset_WallCommon - ThermalTransmittance: 0; LoadBearing: yes; IsExternal: yes
AC_Pset_RenovationAndPhasing - Renovation Status: Existing

# IfcWall: 05_ALLGEMEIN - TRAGENDE BAUTEILE 250 (12)
Type - PredefinedType: ELEMENTEDWALL
Classification: Elementwand (ARCHICAD Klassifizierung); Material: 05_ALLGEMEIN - TRAGENDE BAUTEILE
Pset_WallCommon - ThermalTransmittance: 0; LoadBearing: yes; IsExternal: yes
AC_Pset_RenovationAndPhasing - Renovation Status: Existing
Name | In
Wand-029 | 2.OBERGESCHOSS
Wand-029 | 1.OBERGESCHOSS
Wand-038 | ERDGESCHOSS
Wand-040 | ERDGESCHOSS
4 x Wand-041 | KELLERGESCHOSS
4 x Wand-042 | KELLERGESCHOSS

# IfcWall: 05_ALLGEMEIN - TRAGENDE BAUTEILE 260 (3)
Type - PredefinedType: ELEMENTEDWALL
Classification: Elementwand (ARCHICAD Klassifizierung); Material: 05_ALLGEMEIN - TRAGENDE BAUTEILE
Pset_WallCommon - ThermalTransmittance: 0; LoadBearing: yes; IsExternal: yes
AC_Pset_RenovationAndPhasing - Renovation Status: Existing
Name | In
Wand-036 | DACHGESCHOSS
Wand-030 | 2.OBERGESCHOSS
Wand-034 | 2.OBERGESCHOSS

# IfcWall: 05_ALLGEMEIN - TRAGENDE BAUTEILE 264 (3)
In: KELLERGESCHOSS
Type - PredefinedType: ELEMENTEDWALL
Classification: Elementwand (ARCHICAD Klassifizierung); Material: 05_ALLGEMEIN - TRAGENDE BAUTEILE
Pset_WallCommon - ThermalTransmittance: 0; LoadBearing: yes; IsExternal: yes
AC_Pset_RenovationAndPhasing - Renovation Status: Existing
Name
Wand-038
2 x Wand-039

# IfcWall: 05_ALLGEMEIN - TRAGENDE BAUTEILE 280 (4)
Type - PredefinedType: ELEMENTEDWALL
Classification: Elementwand (ARCHICAD Klassifizierung); Material: 05_ALLGEMEIN - TRAGENDE BAUTEILE
Pset_WallCommon - ThermalTransmittance: 0; LoadBearing: yes; IsExternal: yes
AC_Pset_RenovationAndPhasing - Renovation Status: Existing
Name | In
Wand-031 | 2.OBERGESCHOSS
Wand-039 | ERDGESCHOSS
Wand-030 | KELLERGESCHOSS
Wand-039 | KELLERGESCHOSS

# IfcWall: 05_ALLGEMEIN - TRAGENDE BAUTEILE 290 (3)
Type - PredefinedType: ELEMENTEDWALL
Classification: Elementwand (ARCHICAD Klassifizierung); Material: 05_ALLGEMEIN - TRAGENDE BAUTEILE
Pset_WallCommon - ThermalTransmittance: 0; LoadBearing: yes; IsExternal: yes
AC_Pset_RenovationAndPhasing - Renovation Status: Existing
Name | In
Wand-030 | 2.OBERGESCHOSS
Wand-031 | 2.OBERGESCHOSS
Wand-038 | KELLERGESCHOSS

# IfcWall: 05_ALLGEMEIN - TRAGENDE BAUTEILE 30, Wand-042
In: 1.OBERGESCHOSS
Type - PredefinedType: ELEMENTEDWALL
Classification: Elementwand (ARCHICAD Klassifizierung); Material: 05_ALLGEMEIN - TRAGENDE BAUTEILE
Pset_WallCommon - ThermalTransmittance: 0; LoadBearing: yes; IsExternal: yes
AC_Pset_RenovationAndPhasing - Renovation Status: Existing

# IfcWall: 05_ALLGEMEIN - TRAGENDE BAUTEILE 300 (2)
Type - PredefinedType: ELEMENTEDWALL
Classification: Elementwand (ARCHICAD Klassifizierung); Material: 05_ALLGEMEIN - TRAGENDE BAUTEILE
Pset_WallCommon - ThermalTransmittance: 0; LoadBearing: yes; IsExternal: yes
AC_Pset_RenovationAndPhasing - Renovation Status: Existing
Name | In
Wand-036 | SPITZBODEN
Wand-036 | DACHGESCHOSS

# IfcWall: 05_ALLGEMEIN - TRAGENDE BAUTEILE 320 (3)
Type - PredefinedType: ELEMENTEDWALL
Classification: Elementwand (ARCHICAD Klassifizierung); Material: 05_ALLGEMEIN - TRAGENDE BAUTEILE
Pset_WallCommon - ThermalTransmittance: 0; LoadBearing: yes; IsExternal: yes
AC_Pset_RenovationAndPhasing - Renovation Status: Existing
Name | In
Wand-030 | DACHGESCHOSS
Wand-030 | ERDGESCHOSS
Wand-031 | ERDGESCHOSS

# IfcWall: 05_ALLGEMEIN - TRAGENDE BAUTEILE 376, Wand-031
In: KELLERGESCHOSS
Type - PredefinedType: ELEMENTEDWALL
Classification: Elementwand (ARCHICAD Klassifizierung); Material: 05_ALLGEMEIN - TRAGENDE BAUTEILE
Pset_WallCommon - ThermalTransmittance: 0; LoadBearing: yes; IsExternal: yes
AC_Pset_RenovationAndPhasing - Renovation Status: Existing

# IfcWall: 05_ALLGEMEIN - TRAGENDE BAUTEILE 380, Wand-029
In: 2.OBERGESCHOSS
Type - PredefinedType: ELEMENTEDWALL
Classification: Elementwand (ARCHICAD Klassifizierung); Material: 05_ALLGEMEIN - TRAGENDE BAUTEILE
Pset_WallCommon - ThermalTransmittance: 0; LoadBearing: yes; IsExternal: yes
AC_Pset_RenovationAndPhasing - Renovation Status: Existing

# IfcWall: 05_ALLGEMEIN - TRAGENDE BAUTEILE 380 - 440, Wand-040
In: 2.OBERGESCHOSS
Type - PredefinedType: ELEMENTEDWALL
Classification: Elementwand (ARCHICAD Klassifizierung); Material: 05_ALLGEMEIN - TRAGENDE BAUTEILE
Pset_WallCommon - ThermalTransmittance: 0; LoadBearing: yes; IsExternal: yes
AC_Pset_RenovationAndPhasing - Renovation Status: Existing

# IfcWall: 05_ALLGEMEIN - TRAGENDE BAUTEILE 390, Wand-030
In: ERDGESCHOSS
Type - PredefinedType: ELEMENTEDWALL
Classification: Elementwand (ARCHICAD Klassifizierung); Material: 05_ALLGEMEIN - TRAGENDE BAUTEILE
Pset_WallCommon - ThermalTransmittance: 0; LoadBearing: yes; IsExternal: yes
AC_Pset_RenovationAndPhasing - Renovation Status: Existing

# IfcWall: 05_ALLGEMEIN - TRAGENDE BAUTEILE 400 (19)
Type - PredefinedType: ELEMENTEDWALL
Classification: Elementwand (ARCHICAD Klassifizierung); Material: 05_ALLGEMEIN - TRAGENDE BAUTEILE
Pset_WallCommon - ThermalTransmittance: 0; LoadBearing: yes; IsExternal: yes
AC_Pset_RenovationAndPhasing - Renovation Status: Existing
Name | In
Wand-029 | 2.OBERGESCHOSS
Wand-031 | 2.OBERGESCHOSS
2 x Wand-034 | 2.OBERGESCHOSS
Wand-035 | 2.OBERGESCHOSS
Wand-037 | 2.OBERGESCHOSS
Wand-038 | 2.OBERGESCHOSS
Wand-030 | 1.OBERGESCHOSS
Wand-029 | ERDGESCHOSS
3 x Wand-030 | ERDGESCHOSS
Wand-037 | ERDGESCHOSS
Wand-038 | ERDGESCHOSS
2 x Wand-030 | KELLERGESCHOSS
Wand-032 | KELLERGESCHOSS
Wand-037 | KELLERGESCHOSS
Wand-038 | KELLERGESCHOSS

# IfcWall: 05_ALLGEMEIN - TRAGENDE BAUTEILE 405 (3)
Type - PredefinedType: ELEMENTEDWALL
Classification: Elementwand (ARCHICAD Klassifizierung); Material: 05_ALLGEMEIN - TRAGENDE BAUTEILE
Pset_WallCommon - ThermalTransmittance: 0; LoadBearing: yes; IsExternal: yes
AC_Pset_RenovationAndPhasing - Renovation Status: Existing
Name | In
Wand-029 | 2.OBERGESCHOSS
2 x Wand-034 | ERDGESCHOSS

# IfcWall: 05_ALLGEMEIN - TRAGENDE BAUTEILE 409, Wand-029
In: 2.OBERGESCHOSS
Type - PredefinedType: ELEMENTEDWALL
Classification: Elementwand (ARCHICAD Klassifizierung); Material: 05_ALLGEMEIN - TRAGENDE BAUTEILE
Pset_WallCommon - ThermalTransmittance: 0; LoadBearing: yes; IsExternal: yes
AC_Pset_RenovationAndPhasing - Renovation Status: Existing

# IfcWall: 05_ALLGEMEIN - TRAGENDE BAUTEILE 410 (6)
Type - PredefinedType: ELEMENTEDWALL
Classification: Elementwand (ARCHICAD Klassifizierung); Material: 05_ALLGEMEIN - TRAGENDE BAUTEILE
Pset_WallCommon - ThermalTransmittance: 0; LoadBearing: yes; IsExternal: yes
AC_Pset_RenovationAndPhasing - Renovation Status: Existing
Name | In
Wand-039 | 1.OBERGESCHOSS
Wand-040 | 1.OBERGESCHOSS
Wand-033 | ERDGESCHOSS
2 x Wand-038 | ERDGESCHOSS
Wand-036 | KELLERGESCHOSS

# IfcWall: 05_ALLGEMEIN - TRAGENDE BAUTEILE 415 (4)
Type - PredefinedType: ELEMENTEDWALL
Classification: Elementwand (ARCHICAD Klassifizierung); Material: 05_ALLGEMEIN - TRAGENDE BAUTEILE
Pset_WallCommon - ThermalTransmittance: 0; LoadBearing: yes; IsExternal: yes
AC_Pset_RenovationAndPhasing - Renovation Status: Existing
Name | In
Wand-038 | 1.OBERGESCHOSS
Wand-030 | ERDGESCHOSS
Wand-038 | ERDGESCHOSS
Wand-038 | KELLERGESCHOSS

# IfcWall: 05_ALLGEMEIN - TRAGENDE BAUTEILE 419, Wand-030
In: ERDGESCHOSS
Type - PredefinedType: ELEMENTEDWALL
Classification: Elementwand (ARCHICAD Klassifizierung); Material: 05_ALLGEMEIN - TRAGENDE BAUTEILE
Pset_WallCommon - ThermalTransmittance: 0; LoadBearing: yes; IsExternal: yes
AC_Pset_RenovationAndPhasing - Renovation Status: Existing

# IfcWall: 05_ALLGEMEIN - TRAGENDE BAUTEILE 420 (2)
Type - PredefinedType: ELEMENTEDWALL
Classification: Elementwand (ARCHICAD Klassifizierung); Material: 05_ALLGEMEIN - TRAGENDE BAUTEILE
Pset_WallCommon - ThermalTransmittance: 0; LoadBearing: yes; IsExternal: yes
AC_Pset_RenovationAndPhasing - Renovation Status: Existing
Name | In
Wand-039 | DACHGESCHOSS
Wand-036 | 2.OBERGESCHOSS

# IfcWall: 05_ALLGEMEIN - TRAGENDE BAUTEILE 430 (5)
Type - PredefinedType: ELEMENTEDWALL
Classification: Elementwand (ARCHICAD Klassifizierung); Material: 05_ALLGEMEIN - TRAGENDE BAUTEILE
Pset_WallCommon - ThermalTransmittance: 0; LoadBearing: yes; IsExternal: yes
AC_Pset_RenovationAndPhasing - Renovation Status: Existing
Name | In
3 x Wand-036 | 2.OBERGESCHOSS
Wand-033 | 1.OBERGESCHOSS
Wand-039 | ERDGESCHOSS

# IfcWall: 05_ALLGEMEIN - TRAGENDE BAUTEILE 450 (2)
In: 2.OBERGESCHOSS
Type - PredefinedType: ELEMENTEDWALL
Classification: Elementwand (ARCHICAD Klassifizierung); Material: 05_ALLGEMEIN - TRAGENDE BAUTEILE
Pset_WallCommon - ThermalTransmittance: 0; LoadBearing: yes; IsExternal: yes
AC_Pset_RenovationAndPhasing - Renovation Status: Existing
Name
Wand-031
Wand-037

# IfcWall: 05_ALLGEMEIN - TRAGENDE BAUTEILE 470, Wand-041
In: 1.OBERGESCHOSS
Type - PredefinedType: ELEMENTEDWALL
Classification: Elementwand (ARCHICAD Klassifizierung); Material: 05_ALLGEMEIN - TRAGENDE BAUTEILE
Pset_WallCommon - ThermalTransmittance: 0; LoadBearing: yes; IsExternal: yes
AC_Pset_RenovationAndPhasing - Renovation Status: Existing

# IfcWall: 05_ALLGEMEIN - TRAGENDE BAUTEILE 480 (2)
In: KELLERGESCHOSS
Type - PredefinedType: ELEMENTEDWALL
Classification: Elementwand (ARCHICAD Klassifizierung); Material: 05_ALLGEMEIN - TRAGENDE BAUTEILE
Pset_WallCommon - ThermalTransmittance: 0; LoadBearing: yes; IsExternal: yes
AC_Pset_RenovationAndPhasing - Renovation Status: Existing

# IfcWall: 05_ALLGEMEIN - TRAGENDE BAUTEILE 50 (2)
In: ERDGESCHOSS
Type - PredefinedType: ELEMENTEDWALL
Classification: Elementwand (ARCHICAD Klassifizierung); Material: 05_ALLGEMEIN - TRAGENDE BAUTEILE
Pset_WallCommon - ThermalTransmittance: 0; LoadBearing: yes; IsExternal: yes
AC_Pset_RenovationAndPhasing - Renovation Status: Existing

# IfcWall: 05_ALLGEMEIN - TRAGENDE BAUTEILE 500 (4)
Type - PredefinedType: ELEMENTEDWALL
Classification: Elementwand (ARCHICAD Klassifizierung); Material: 05_ALLGEMEIN - TRAGENDE BAUTEILE
Pset_WallCommon - ThermalTransmittance: 0; LoadBearing: yes; IsExternal: yes
AC_Pset_RenovationAndPhasing - Renovation Status: Existing
Name | In
3 x Wand-030 | 1.OBERGESCHOSS
Wand-030 | KELLERGESCHOSS

# IfcWall: 05_ALLGEMEIN - TRAGENDE BAUTEILE 510 (2)
Type - PredefinedType: ELEMENTEDWALL
Classification: Elementwand (ARCHICAD Klassifizierung); Material: 05_ALLGEMEIN - TRAGENDE BAUTEILE
Pset_WallCommon - ThermalTransmittance: 0; LoadBearing: yes; IsExternal: yes
AC_Pset_RenovationAndPhasing - Renovation Status: Existing
Name | In
Wand-029 | 2.OBERGESCHOSS
Wand-029 | ERDGESCHOSS

# IfcWall: 05_ALLGEMEIN - TRAGENDE BAUTEILE 511, Wand-030
In: KELLERGESCHOSS
Type - PredefinedType: ELEMENTEDWALL
Classification: Elementwand (ARCHICAD Klassifizierung); Material: 05_ALLGEMEIN - TRAGENDE BAUTEILE
Pset_WallCommon - ThermalTransmittance: 0; LoadBearing: yes; IsExternal: yes
AC_Pset_RenovationAndPhasing - Renovation Status: Existing

# IfcWall: 05_ALLGEMEIN - TRAGENDE BAUTEILE 518 (2)
In: 2.OBERGESCHOSS
Type - PredefinedType: ELEMENTEDWALL
Classification: Elementwand (ARCHICAD Klassifizierung); Material: 05_ALLGEMEIN - TRAGENDE BAUTEILE
Pset_WallCommon - ThermalTransmittance: 0; LoadBearing: yes; IsExternal: yes
AC_Pset_RenovationAndPhasing - Renovation Status: Existing

# IfcWall: 05_ALLGEMEIN - TRAGENDE BAUTEILE 520 (3)
Type - PredefinedType: ELEMENTEDWALL
Classification: Elementwand (ARCHICAD Klassifizierung); Material: 05_ALLGEMEIN - TRAGENDE BAUTEILE
Pset_WallCommon - ThermalTransmittance: 0; LoadBearing: yes; IsExternal: yes
AC_Pset_RenovationAndPhasing - Renovation Status: Existing
Name | In
Wand-036 | 2.OBERGESCHOSS
Wand-031 | 1.OBERGESCHOSS
Wand-031 | KELLERGESCHOSS

# IfcWall: 05_ALLGEMEIN - TRAGENDE BAUTEILE 525, Wand-030
In: KELLERGESCHOSS
Type - PredefinedType: ELEMENTEDWALL
Classification: Elementwand (ARCHICAD Klassifizierung); Material: 05_ALLGEMEIN - TRAGENDE BAUTEILE
Pset_WallCommon - ThermalTransmittance: 0; LoadBearing: yes; IsExternal: yes
AC_Pset_RenovationAndPhasing - Renovation Status: Existing

# IfcWall: 05_ALLGEMEIN - TRAGENDE BAUTEILE 530 (2)
Type - PredefinedType: ELEMENTEDWALL
Classification: Elementwand (ARCHICAD Klassifizierung); Material: 05_ALLGEMEIN - TRAGENDE BAUTEILE
Pset_WallCommon - ThermalTransmittance: 0; LoadBearing: yes; IsExternal: yes
AC_Pset_RenovationAndPhasing - Renovation Status: Existing
Name | In
Wand-036 | 2.OBERGESCHOSS
Wand-034 | KELLERGESCHOSS

# IfcWall: 05_ALLGEMEIN - TRAGENDE BAUTEILE 538, Wand-038
In: KELLERGESCHOSS
Type - PredefinedType: ELEMENTEDWALL
Classification: Elementwand (ARCHICAD Klassifizierung); Material: 05_ALLGEMEIN - TRAGENDE BAUTEILE
Pset_WallCommon - ThermalTransmittance: 0; LoadBearing: yes; IsExternal: yes
AC_Pset_RenovationAndPhasing - Renovation Status: Existing

# IfcWall: 05_ALLGEMEIN - TRAGENDE BAUTEILE 540 (3)
In: KELLERGESCHOSS
Type - PredefinedType: ELEMENTEDWALL
Classification: Elementwand (ARCHICAD Klassifizierung); Material: 05_ALLGEMEIN - TRAGENDE BAUTEILE
Pset_WallCommon - ThermalTransmittance: 0; LoadBearing: yes; IsExternal: yes
AC_Pset_RenovationAndPhasing - Renovation Status: Existing
Name
Wand-036
2 x Wand-039

# IfcWall: 05_ALLGEMEIN - TRAGENDE BAUTEILE 549, Wand-039
In: KELLERGESCHOSS
Type - PredefinedType: ELEMENTEDWALL
Classification: Elementwand (ARCHICAD Klassifizierung); Material: 05_ALLGEMEIN - TRAGENDE BAUTEILE
Pset_WallCommon - ThermalTransmittance: 0; LoadBearing: yes; IsExternal: yes
AC_Pset_RenovationAndPhasing - Renovation Status: Existing

# IfcWall: 05_ALLGEMEIN - TRAGENDE BAUTEILE 550 (2)
In: ERDGESCHOSS
Type - PredefinedType: ELEMENTEDWALL
Classification: Elementwand (ARCHICAD Klassifizierung); Material: 05_ALLGEMEIN - TRAGENDE BAUTEILE
Pset_WallCommon - ThermalTransmittance: 0; LoadBearing: yes; IsExternal: yes
AC_Pset_RenovationAndPhasing - Renovation Status: Existing

# IfcWall: 05_ALLGEMEIN - TRAGENDE BAUTEILE 570, Wand-036
In: KELLERGESCHOSS
Type - PredefinedType: ELEMENTEDWALL
Classification: Elementwand (ARCHICAD Klassifizierung); Material: 05_ALLGEMEIN - TRAGENDE BAUTEILE
Pset_WallCommon - ThermalTransmittance: 0; LoadBearing: yes; IsExternal: yes
AC_Pset_RenovationAndPhasing - Renovation Status: Existing

# IfcWall: 05_ALLGEMEIN - TRAGENDE BAUTEILE 580 (3)
Type - PredefinedType: ELEMENTEDWALL
Classification: Elementwand (ARCHICAD Klassifizierung); Material: 05_ALLGEMEIN - TRAGENDE BAUTEILE
Pset_WallCommon - ThermalTransmittance: 0; LoadBearing: yes; IsExternal: yes
AC_Pset_RenovationAndPhasing - Renovation Status: Existing
Name | In
Wand-041 | 1.OBERGESCHOSS
Wand-038 | ERDGESCHOSS
Wand-038 | KELLERGESCHOSS

# IfcWall: 05_ALLGEMEIN - TRAGENDE BAUTEILE 585 (2)
Type - PredefinedType: ELEMENTEDWALL
Classification: Elementwand (ARCHICAD Klassifizierung); Material: 05_ALLGEMEIN - TRAGENDE BAUTEILE
Pset_WallCommon - ThermalTransmittance: 0; LoadBearing: yes; IsExternal: yes
AC_Pset_RenovationAndPhasing - Renovation Status: Existing
Name | In
Wand-040 | ERDGESCHOSS
Wand-036 | KELLERGESCHOSS

# IfcWall: 05_ALLGEMEIN - TRAGENDE BAUTEILE 60, Wand-038
In: 2.OBERGESCHOSS
Type - PredefinedType: ELEMENTEDWALL
Classification: Elementwand (ARCHICAD Klassifizierung); Material: 05_ALLGEMEIN - TRAGENDE BAUTEILE
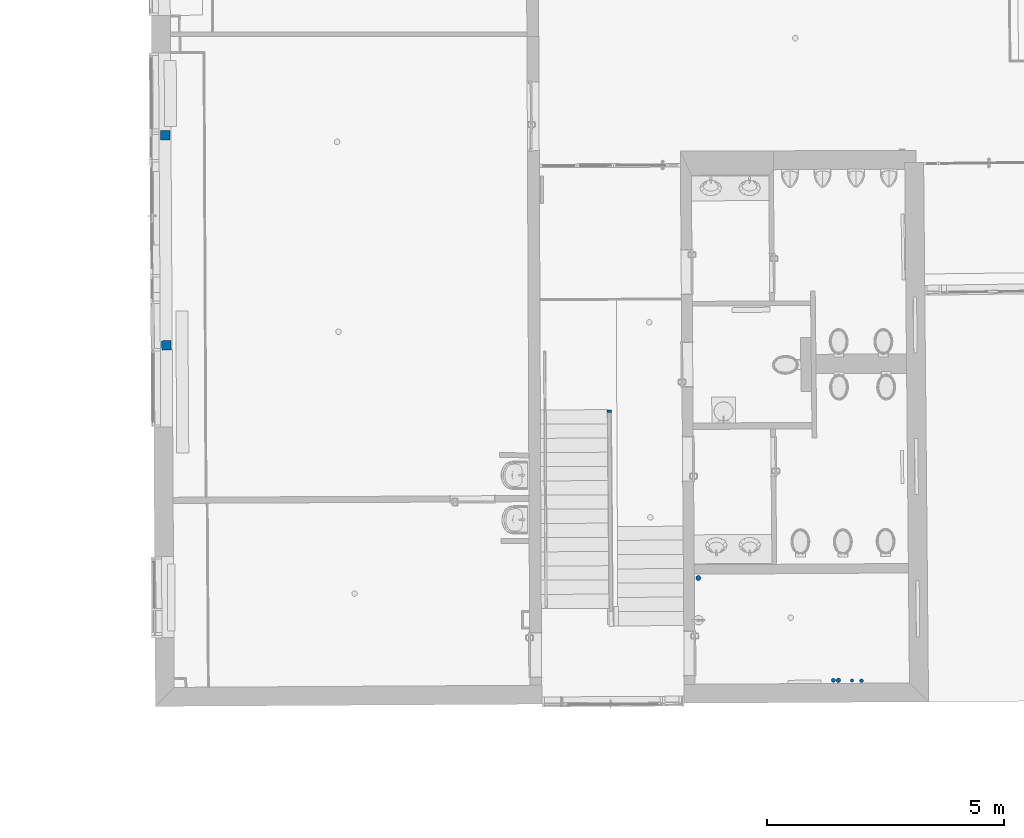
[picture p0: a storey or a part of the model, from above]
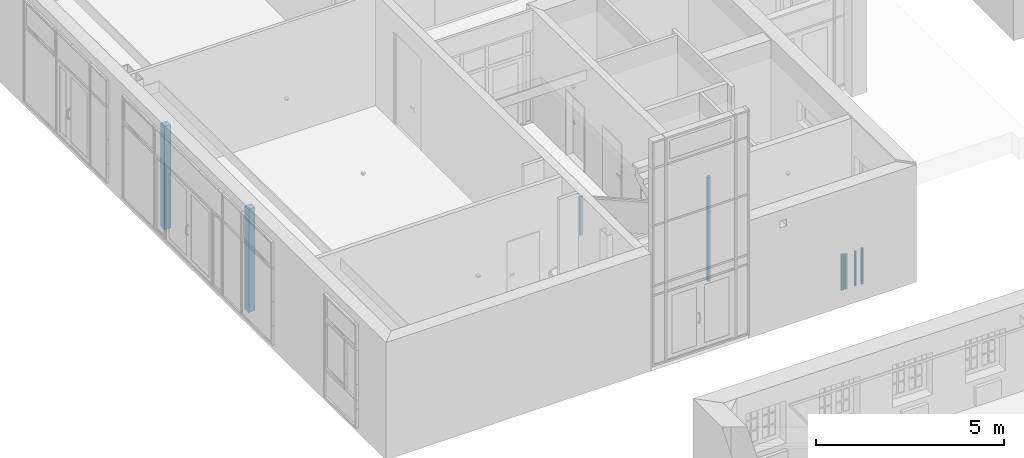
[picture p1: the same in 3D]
Properties of the parts of a building model (IFC2X3), part 4 of 4

# IfcWall: 05_ALLGEMEIN - TRAGENDE BAUTEILE 60, Wand-038
Pset_WallCommon - ThermalTransmittance: 0; LoadBearing: yes; IsExternal: yes
AC_Pset_RenovationAndPhasing - Renovation Status: Existing

# IfcWall: 05_ALLGEMEIN - TRAGENDE BAUTEILE 600 (2)
In: KELLERGESCHOSS
Type - PredefinedType: ELEMENTEDWALL
Classification: Elementwand (ARCHICAD Klassifizierung); Material: 05_ALLGEMEIN - TRAGENDE BAUTEILE
Pset_WallCommon - ThermalTransmittance: 0; LoadBearing: yes; IsExternal: yes
AC_Pset_RenovationAndPhasing - Renovation Status: Existing
Name
Wand-036
Wand-037

# IfcWall: 05_ALLGEMEIN - TRAGENDE BAUTEILE 619 (6)
In: DACHGESCHOSS
Type - PredefinedType: ELEMENTEDWALL
Classification: Elementwand (ARCHICAD Klassifizierung); Material: 05_ALLGEMEIN - TRAGENDE BAUTEILE
Pset_WallCommon - ThermalTransmittance: 0; LoadBearing: yes; IsExternal: yes
AC_Pset_RenovationAndPhasing - Renovation Status: Existing

# IfcWall: 05_ALLGEMEIN - TRAGENDE BAUTEILE 660 (2)
In: KELLERGESCHOSS
Type - PredefinedType: ELEMENTEDWALL
Classification: Elementwand (ARCHICAD Klassifizierung); Material: 05_ALLGEMEIN - TRAGENDE BAUTEILE
Pset_WallCommon - ThermalTransmittance: 0; LoadBearing: yes; IsExternal: yes
AC_Pset_RenovationAndPhasing - Renovation Status: Existing
Name
Wand-032
Wand-035

# IfcWall: 05_ALLGEMEIN - TRAGENDE BAUTEILE 690, Wand-039
In: KELLERGESCHOSS
Type - PredefinedType: ELEMENTEDWALL
Classification: Elementwand (ARCHICAD Klassifizierung); Material: 05_ALLGEMEIN - TRAGENDE BAUTEILE
Pset_WallCommon - ThermalTransmittance: 0; LoadBearing: yes; IsExternal: yes
AC_Pset_RenovationAndPhasing - Renovation Status: Existing

# IfcWall: 05_ALLGEMEIN - TRAGENDE BAUTEILE 700, Wand-036
In: KELLERGESCHOSS
Type - PredefinedType: ELEMENTEDWALL
Classification: Elementwand (ARCHICAD Klassifizierung); Material: 05_ALLGEMEIN - TRAGENDE BAUTEILE
Pset_WallCommon - ThermalTransmittance: 0; LoadBearing: yes; IsExternal: yes
AC_Pset_RenovationAndPhasing - Renovation Status: Existing

# IfcWall: 05_ALLGEMEIN - TRAGENDE BAUTEILE 790 (3)
In: 1.OBERGESCHOSS
Type - PredefinedType: ELEMENTEDWALL
Classification: Elementwand (ARCHICAD Klassifizierung); Material: 05_ALLGEMEIN - TRAGENDE BAUTEILE
Pset_WallCommon - ThermalTransmittance: 0; LoadBearing: yes; IsExternal: yes
AC_Pset_RenovationAndPhasing - Renovation Status: Existing

# IfcWall: 05_ALLGEMEIN - TRAGENDE BAUTEILE 800, Wand-030
In: 1.OBERGESCHOSS
Type - PredefinedType: ELEMENTEDWALL
Classification: Elementwand (ARCHICAD Klassifizierung); Material: 05_ALLGEMEIN - TRAGENDE BAUTEILE
Pset_WallCommon - ThermalTransmittance: 0; LoadBearing: yes; IsExternal: yes
AC_Pset_RenovationAndPhasing - Renovation Status: Existing

# IfcWall: 05_ALLGEMEIN - TRAGENDE BAUTEILE 82 (4)
Type - PredefinedType: ELEMENTEDWALL
Classification: Elementwand (ARCHICAD Klassifizierung); Material: 05_ALLGEMEIN - TRAGENDE BAUTEILE
Pset_WallCommon - ThermalTransmittance: 0; LoadBearing: yes; IsExternal: yes
AC_Pset_RenovationAndPhasing - Renovation Status: Existing
Name | In
Wand-038 | 1.OBERGESCHOSS
Wand-039 | 1.OBERGESCHOSS
Wand-040 | 1.OBERGESCHOSS
Wand-038 | ERDGESCHOSS

# IfcWall: 05_ALLGEMEIN - TRAGENDE BAUTEILE 87, Wand-038
In: ERDGESCHOSS
Type - PredefinedType: ELEMENTEDWALL
Classification: Elementwand (ARCHICAD Klassifizierung); Material: 05_ALLGEMEIN - TRAGENDE BAUTEILE
Pset_WallCommon - ThermalTransmittance: 0; LoadBearing: yes; IsExternal: yes
AC_Pset_RenovationAndPhasing - Renovation Status: Existing

# IfcWall: 43_Gipskarton, Wand-039
In: 2.OBERGESCHOSS
Type - PredefinedType: ELEMENTEDWALL
Classification: Elementwand (ARCHICAD Klassifizierung); Material: 43_Gipskarton
Pset_WallCommon - ThermalTransmittance: 0; LoadBearing: yes; IsExternal: yes
AC_Pset_RenovationAndPhasing - Renovation Status: Existing

# IfcWall: 43_Gipskarton 100 (5)
In: 2.OBERGESCHOSS
Type - PredefinedType: ELEMENTEDWALL
Classification: Elementwand (ARCHICAD Klassifizierung); Material: 43_Gipskarton
Pset_WallCommon - ThermalTransmittance: 0; LoadBearing: yes; IsExternal: yes
AC_Pset_RenovationAndPhasing - Renovation Status: Existing
Name
Wand-037
4 x Wand-038

# IfcWall: 43_Gipskarton 120, Wand-039
In: 2.OBERGESCHOSS
Type - PredefinedType: ELEMENTEDWALL
Classification: Elementwand (ARCHICAD Klassifizierung); Material: 43_Gipskarton
Pset_WallCommon - ThermalTransmittance: 0; LoadBearing: yes; IsExternal: yes
AC_Pset_RenovationAndPhasing - Renovation Status: Existing

# IfcWall: 43_Gipskarton 130, Wand-038
In: 2.OBERGESCHOSS
Type - PredefinedType: ELEMENTEDWALL
Classification: Elementwand (ARCHICAD Klassifizierung); Material: 43_Gipskarton
Pset_WallCommon - ThermalTransmittance: 0; LoadBearing: yes; IsExternal: yes
AC_Pset_RenovationAndPhasing - Renovation Status: Existing

# IfcWall: 43_Gipskarton 230, Wand-030
In: KELLERGESCHOSS
Type - PredefinedType: ELEMENTEDWALL
Classification: Elementwand (ARCHICAD Klassifizierung); Material: 43_Gipskarton
Pset_WallCommon - ThermalTransmittance: 0; LoadBearing: yes; IsExternal: yes
AC_Pset_RenovationAndPhasing - Renovation Status: Existing

# IfcWall: 43_Gipskarton 30 (43)
Type - PredefinedType: ELEMENTEDWALL
Classification: Elementwand (ARCHICAD Klassifizierung); Material: 43_Gipskarton
Pset_WallCommon - ThermalTransmittance: 0; LoadBearing: yes; IsExternal: yes
AC_Pset_RenovationAndPhasing - Renovation Status: Existing
Name | In
Wand-036 | 2.OBERGESCHOSS
5 x Wand-037 | 2.OBERGESCHOSS
14 x Wand-038 | 2.OBERGESCHOSS
7 x Wand-039 | 2.OBERGESCHOSS
7 x Wand-040 | 2.OBERGESCHOSS
Wand-041 | 2.OBERGESCHOSS
Wand-042 | 2.OBERGESCHOSS
3 x Wand-043 | 2.OBERGESCHOSS
3 x Wand-067 | KELLERGESCHOSS
Wand-068 | KELLERGESCHOSS

# IfcWall: Dach Sims 3 192 x 760, Wand-082
In: 2.OBERGESCHOSS
Type - PredefinedType: ELEMENTEDWALL
Classification: Elementwand (ARCHICAD Klassifizierung); Material: 01_ALLGEMEIN - BAUTEIL
Pset_WallCommon - ThermalTransmittance: 0; LoadBearing: yes; IsExternal: yes
AC_Pset_RenovationAndPhasing - Renovation Status: Existing

# IfcWall: Dachsims 2 241 x 886, Wand-075
In: 2.OBERGESCHOSS
Type - PredefinedType: ELEMENTEDWALL
Classification: Elementwand (ARCHICAD Klassifizierung); Material: 01_ALLGEMEIN - BAUTEIL
Pset_WallCommon - ThermalTransmittance: 0; LoadBearing: yes; IsExternal: yes
AC_Pset_RenovationAndPhasing - Renovation Status: Existing

# IfcWall: Fassade Sims 1 191 x 1241 (2)
In: 1.OBERGESCHOSS
Type - PredefinedType: ELEMENTEDWALL
Classification: Elementwand (ARCHICAD Klassifizierung)
Pset_WallCommon - ThermalTransmittance: 0; LoadBearing: yes; IsExternal: yes
AC_Pset_RenovationAndPhasing - Renovation Status: Existing

# IfcWall: Fassade Sims 2 100 x 317 (9)
In: KELLERGESCHOSS
Type - PredefinedType: ELEMENTEDWALL
Classification: Elementwand (ARCHICAD Klassifizierung); Material: 01_ALLGEMEIN - BAUTEIL
Pset_WallCommon - ThermalTransmittance: 0; LoadBearing: yes; IsExternal: yes
AC_Pset_RenovationAndPhasing - Renovation Status: Existing
Name
8 x Wand-072
Wand-073

# IfcWall: Fassade Sims 3 354 x 1078 (3)
In: KELLERGESCHOSS
Type - PredefinedType: ELEMENTEDWALL
Classification: Elementwand (ARCHICAD Klassifizierung); Material: 01_ALLGEMEIN - BAUTEIL
Pset_WallCommon - ThermalTransmittance: 0; LoadBearing: yes; IsExternal: yes
AC_Pset_RenovationAndPhasing - Renovation Status: Existing

# IfcWall: Fassade Sims 4 191 x 476 (10)
In: 2.OBERGESCHOSS
Type - PredefinedType: ELEMENTEDWALL
Classification: Elementwand (ARCHICAD Klassifizierung); Material: 01_ALLGEMEIN - BAUTEIL
Pset_WallCommon - ThermalTransmittance: 0; LoadBearing: yes; IsExternal: yes
AC_Pset_RenovationAndPhasing - Renovation Status: Existing
Name
7 x Wand-076
Wand-077
2 x Wand-078

# IfcWall: Fassade Sims 5 130 x 418, Wand-072
In: ERDGESCHOSS
Type - PredefinedType: ELEMENTEDWALL
Classification: Elementwand (ARCHICAD Klassifizierung); Material: 01_ALLGEMEIN - BAUTEIL
Pset_WallCommon - ThermalTransmittance: 0; LoadBearing: yes; IsExternal: yes
AC_Pset_RenovationAndPhasing - Renovation Status: Existing

# IfcWall: Fassade Sims 6 137 x 242, Wand-072
In: ERDGESCHOSS
Type - PredefinedType: ELEMENTEDWALL
Classification: Elementwand (ARCHICAD Klassifizierung); Material: 01_ALLGEMEIN - BAUTEIL
Pset_WallCommon - ThermalTransmittance: 0; LoadBearing: yes; IsExternal: yes
AC_Pset_RenovationAndPhasing - Renovation Status: Existing

# IfcWall: Fassade Sims 7 23 x 138 (16)
In: 1.OBERGESCHOSS
Type - PredefinedType: ELEMENTEDWALL
Classification: Elementwand (ARCHICAD Klassifizierung); Material: 01_ALLGEMEIN - BAUTEIL
Pset_WallCommon - ThermalTransmittance: 0; LoadBearing: yes; IsExternal: yes
AC_Pset_RenovationAndPhasing - Renovation Status: Existing
Name
5 x Wand-083
Wand-084
2 x Wand-085
Wand-086
Wand-087
Wand-088
Wand-089
Wand-090
Wand-091
Wand-092
Wand-093

# IfcWall: Fassade Sims Eingang 120 x 2804 (6)
In: ERDGESCHOSS
Type - PredefinedType: ELEMENTEDWALL
Classification: Elementwand (ARCHICAD Klassifizierung)
Pset_WallCommon - ThermalTransmittance: 0; LoadBearing: yes; IsExternal: yes
AC_Pset_RenovationAndPhasing - Renovation Status: Existing
Name
3 x Wand-036
Wand-037
Wand-038
Wand-039

# IfcWall: Fassade Sims Eingang 2 636 x 260, Wand-040
In: ERDGESCHOSS
Type - PredefinedType: ELEMENTEDWALL
Classification: Elementwand (ARCHICAD Klassifizierung); Material: 01_ALLGEMEIN - BAUTEIL
Pset_WallCommon - ThermalTransmittance: 0; LoadBearing: yes; IsExternal: yes
AC_Pset_RenovationAndPhasing - Renovation Status: Existing

# IfcWall: Sockel 1 59 x 750 (27)
In: KELLERGESCHOSS
Type - PredefinedType: ELEMENTEDWALL
Classification: Elementwand (ARCHICAD Klassifizierung); Material: 01_ALLGEMEIN - BAUTEIL
Pset_WallCommon - ThermalTransmittance: 0; LoadBearing: yes; IsExternal: yes
AC_Pset_RenovationAndPhasing - Renovation Status: Existing
Name
3 x Wand-074
Wand-075
8 x Wand-076
4 x Wand-077
4 x Wand-078
5 x Wand-079
Wand-080
Wand-081

# IfcWall: Stütze 117 x 1928 (4)
In: KELLERGESCHOSS
Type - PredefinedType: ELEMENTEDWALL
Classification: Elementwand (ARCHICAD Klassifizierung); Material: 05_ALLGEMEIN - TRAGENDE BAUTEILE
Pset_WallCommon - ThermalTransmittance: 0; LoadBearing: yes; IsExternal: yes
AC_Pset_RenovationAndPhasing - Renovation Status: Existing
Name
2 x Wand-069
2 x Wand-070

# IfcWallStandardCase: 01_ALLGEMEIN - BAUTEIL 100 (14)
In: KELLERGESCHOSS
Type - PredefinedType: ELEMENTEDWALL
Classification: Elementwand (ARCHICAD Klassifizierung); Material: 01_ALLGEMEIN - BAUTEIL 0.1 m
Pset_WallCommon - ThermalTransmittance: 0; LoadBearing: yes; IsExternal: yes
AC_Pset_RenovationAndPhasing - Renovation Status: Existing

# IfcWallStandardCase: 01_ALLGEMEIN - BAUTEIL 105 (135)
Type - PredefinedType: ELEMENTEDWALL
Classification: Elementwand (ARCHICAD Klassifizierung); Material: 01_ALLGEMEIN - BAUTEIL 0.105 m
Pset_WallCommon - ThermalTransmittance: 0; LoadBearing: yes; IsExternal: yes
AC_Pset_RenovationAndPhasing - Renovation Status: Existing
Name | In
2 x Wand-036 | 2.OBERGESCHOSS
16 x Wand-037 | 2.OBERGESCHOSS
7 x Wand-038 | 2.OBERGESCHOSS
3 x Wand-039 | 2.OBERGESCHOSS
Wand-040 | 2.OBERGESCHOSS
4 x Wand-042 | 2.OBERGESCHOSS
Wand-044 | 2.OBERGESCHOSS
Wand-047 | 2.OBERGESCHOSS
Wand-048 | 2.OBERGESCHOSS
Wand-049 | 2.OBERGESCHOSS
Wand-050 | 2.OBERGESCHOSS
20 x Wand-035 | 1.OBERGESCHOSS
8 x Wand-036 | 1.OBERGESCHOSS
3 x Wand-037 | 1.OBERGESCHOSS
2 x Wand-035 | ERDGESCHOSS
9 x Wand-036 | ERDGESCHOSS
5 x Wand-037 | ERDGESCHOSS
4 x Wand-038 | ERDGESCHOSS
4 x Wand-039 | ERDGESCHOSS
2 x Wand-040 | ERDGESCHOSS
8 x Wand-041 | ERDGESCHOSS
2 x Wand-030 | KELLERGESCHOSS
Wand-035 | KELLERGESCHOSS
16 x Wand-036 | KELLERGESCHOSS
4 x Wand-037 | KELLERGESCHOSS
4 x Wand-038 | KELLERGESCHOSS
5 x Wand-039 | KELLERGESCHOSS

# IfcWallStandardCase: 01_ALLGEMEIN - BAUTEIL 120 (6)
In: KELLERGESCHOSS
Type - PredefinedType: ELEMENTEDWALL
Classification: Elementwand (ARCHICAD Klassifizierung); Material: 01_ALLGEMEIN - BAUTEIL 0.12 m
Pset_WallCommon - ThermalTransmittance: 0; LoadBearing: yes; IsExternal: yes
AC_Pset_RenovationAndPhasing - Renovation Status: Existing
Name
Wand-030
Wand-031
Wand-032
Wand-033
Wand-034
Wand-035

# IfcWallStandardCase: 01_ALLGEMEIN - BAUTEIL 160 (2)
Type - PredefinedType: ELEMENTEDWALL
Classification: Elementwand (ARCHICAD Klassifizierung); Material: 01_ALLGEMEIN - BAUTEIL 0.16 m
Pset_WallCommon - ThermalTransmittance: 0; LoadBearing: yes; IsExternal: yes
AC_Pset_RenovationAndPhasing - Renovation Status: Existing
Name | In
Wand-030 | ERDGESCHOSS
Wand-030 | KELLERGESCHOSS

# IfcWallStandardCase: 01_ALLGEMEIN - BAUTEIL 175, Wand-036
In: 1.OBERGESCHOSS
Type - PredefinedType: ELEMENTEDWALL
Classification: Elementwand (ARCHICAD Klassifizierung); Material: 01_ALLGEMEIN - BAUTEIL 0.175 m
Pset_WallCommon - ThermalTransmittance: 0; LoadBearing: yes; IsExternal: yes
AC_Pset_RenovationAndPhasing - Renovation Status: Existing

# IfcWallStandardCase: 01_ALLGEMEIN - BAUTEIL 190, Wand-036
In: KELLERGESCHOSS
Type - PredefinedType: ELEMENTEDWALL
Classification: Elementwand (ARCHICAD Klassifizierung); Material: 01_ALLGEMEIN - BAUTEIL 0.19 m
Pset_WallCommon - ThermalTransmittance: 0; LoadBearing: yes; IsExternal: yes
AC_Pset_RenovationAndPhasing - Renovation Status: Existing

# IfcWallStandardCase: 01_ALLGEMEIN - BAUTEIL 200 (4)
In: KELLERGESCHOSS
Type - PredefinedType: ELEMENTEDWALL
Classification: Elementwand (ARCHICAD Klassifizierung); Material: 01_ALLGEMEIN - BAUTEIL 0.2 m
Pset_WallCommon - ThermalTransmittance: 0; LoadBearing: yes; IsExternal: yes
AC_Pset_RenovationAndPhasing - Renovation Status: Existing
Name
2 x Wand-031
Wand-032
Wand-033

# IfcWallStandardCase: 01_ALLGEMEIN - BAUTEIL 225 (2)
In: ERDGESCHOSS
Type - PredefinedType: ELEMENTEDWALL
Classification: Elementwand (ARCHICAD Klassifizierung); Material: 01_ALLGEMEIN - BAUTEIL 0.225 m
Pset_WallCommon - ThermalTransmittance: 0; LoadBearing: yes; IsExternal: yes
AC_Pset_RenovationAndPhasing - Renovation Status: Existing

# IfcWallStandardCase: 01_ALLGEMEIN - BAUTEIL 255 (16)
Type - PredefinedType: ELEMENTEDWALL
Classification: Elementwand (ARCHICAD Klassifizierung); Material: 01_ALLGEMEIN - BAUTEIL 0.255 m
Pset_WallCommon - ThermalTransmittance: 0; LoadBearing: yes; IsExternal: yes
AC_Pset_RenovationAndPhasing - Renovation Status: Existing
Name | In
5 x Wand-030 | ERDGESCHOSS
3 x Wand-031 | ERDGESCHOSS
Wand-032 | ERDGESCHOSS
5 x Wand-030 | KELLERGESCHOSS
2 x Wand-031 | KELLERGESCHOSS

# IfcWallStandardCase: 01_ALLGEMEIN - BAUTEIL 60 (12)
Type - PredefinedType: ELEMENTEDWALL
Classification: Elementwand (ARCHICAD Klassifizierung); Material: 01_ALLGEMEIN - BAUTEIL 0.06 m
Pset_WallCommon - ThermalTransmittance: 0; LoadBearing: yes; IsExternal: yes
AC_Pset_RenovationAndPhasing - Renovation Status: Existing
Name | In
4 x Wand-035 | 1.OBERGESCHOSS
Wand-030 | ERDGESCHOSS
4 x Wand-037 | ERDGESCHOSS
3 x Wand-030 | KELLERGESCHOSS

# IfcWallStandardCase: 01_ALLGEMEIN - BAUTEIL 65 (9)
Type - PredefinedType: ELEMENTEDWALL
Classification: Elementwand (ARCHICAD Klassifizierung); Material: 01_ALLGEMEIN - BAUTEIL 0.065 m
Pset_WallCommon - ThermalTransmittance: 0; LoadBearing: yes; IsExternal: yes
AC_Pset_RenovationAndPhasing - Renovation Status: Existing
Name | In
2 x Wand-037 | 1.OBERGESCHOSS
Wand-036 | ERDGESCHOSS
Wand-037 | ERDGESCHOSS
3 x Wand-036 | KELLERGESCHOSS
Wand-038 | KELLERGESCHOSS
Wand-039 | KELLERGESCHOSS

# IfcWallStandardCase: 01_ALLGEMEIN - BAUTEIL 70, Wand-030
In: KELLERGESCHOSS
Type - PredefinedType: ELEMENTEDWALL
Classification: Elementwand (ARCHICAD Klassifizierung); Material: 01_ALLGEMEIN - BAUTEIL 0.07 m
Pset_WallCommon - ThermalTransmittance: 0; LoadBearing: yes; IsExternal: yes
AC_Pset_RenovationAndPhasing - Renovation Status: Existing

# IfcWallStandardCase: 05_ALLGEMEIN - TRAGENDE BAUTEILE 100 (38)
Type - PredefinedType: ELEMENTEDWALL
Classification: Elementwand (ARCHICAD Klassifizierung); Material: 05_ALLGEMEIN - TRAGENDE BAUTEILE 0.1 m
Pset_WallCommon - ThermalTransmittance: 0; LoadBearing: yes; IsExternal: yes
AC_Pset_RenovationAndPhasing - Renovation Status: Existing
Name | In
4 x Wand-030 | DACHGESCHOSS
2 x Wand-031 | DACHGESCHOSS
Wand-031 | 2.OBERGESCHOSS
2 x Wand-038 | 1.OBERGESCHOSS
Wand-039 | 1.OBERGESCHOSS
Wand-030 | ERDGESCHOSS
Wand-038 | ERDGESCHOSS
4 x Wand-030 | KELLERGESCHOSS
2 x Wand-031 | KELLERGESCHOSS
14 x Wand-032 | KELLERGESCHOSS
Wand-037 | KELLERGESCHOSS
2 x Wand-038 | KELLERGESCHOSS
2 x Wand-039 | KELLERGESCHOSS
Wand-040 | KELLERGESCHOSS

# IfcWallStandardCase: 05_ALLGEMEIN - TRAGENDE BAUTEILE 105 (4)
In: KELLERGESCHOSS
Type - PredefinedType: ELEMENTEDWALL
Classification: Elementwand (ARCHICAD Klassifizierung); Material: 05_ALLGEMEIN - TRAGENDE BAUTEILE 0.105 m
Pset_WallCommon - ThermalTransmittance: 0; LoadBearing: yes; IsExternal: yes
AC_Pset_RenovationAndPhasing - Renovation Status: Existing

# IfcWallStandardCase: 05_ALLGEMEIN - TRAGENDE BAUTEILE 120 (8)
Type - PredefinedType: ELEMENTEDWALL
Classification: Elementwand (ARCHICAD Klassifizierung); Material: 05_ALLGEMEIN - TRAGENDE BAUTEILE 0.12 m
Pset_WallCommon - ThermalTransmittance: 0; LoadBearing: yes; IsExternal: yes
AC_Pset_RenovationAndPhasing - Renovation Status: Existing
Name | In
2 x Wand-036 | 2.OBERGESCHOSS
2 x Wand-036 | 1.OBERGESCHOSS
2 x Wand-036 | ERDGESCHOSS
2 x Wand-038 | KELLERGESCHOSS

# IfcWallStandardCase: 05_ALLGEMEIN - TRAGENDE BAUTEILE 125 (3)
Type - PredefinedType: ELEMENTEDWALL
Classification: Elementwand (ARCHICAD Klassifizierung); Material: 05_ALLGEMEIN - TRAGENDE BAUTEILE 0.125 m
Pset_WallCommon - ThermalTransmittance: 0; LoadBearing: yes; IsExternal: yes
AC_Pset_RenovationAndPhasing - Renovation Status: Existing
Name | In
Wand-039 | ERDGESCHOSS
Wand-030 | KELLERGESCHOSS
Wand-031 | KELLERGESCHOSS

# IfcWallStandardCase: 05_ALLGEMEIN - TRAGENDE BAUTEILE 127 (3)
Type - PredefinedType: ELEMENTEDWALL
Classification: Elementwand (ARCHICAD Klassifizierung)
Pset_WallCommon - ThermalTransmittance: 0; LoadBearing: yes; IsExternal: yes
AC_Pset_RenovationAndPhasing - Renovation Status: Existing
Name | In | Material
Wand-038 | 1.OBERGESCHOSS | 05_ALLGEMEIN - TRAGENDE BAUTEILE 0.126795 m
2 x Wand-028 | KELLERGESCHOSS | 05_ALLGEMEIN - TRAGENDE BAUTEILE 0.126967 m

# IfcWallStandardCase: 05_ALLGEMEIN - TRAGENDE BAUTEILE 130 (5)
Type - PredefinedType: ELEMENTEDWALL
Classification: Elementwand (ARCHICAD Klassifizierung); Material: 05_ALLGEMEIN - TRAGENDE BAUTEILE 0.13 m
Pset_WallCommon - ThermalTransmittance: 0; LoadBearing: yes; IsExternal: yes
AC_Pset_RenovationAndPhasing - Renovation Status: Existing
Name | In
Wand-036 | ERDGESCHOSS
2 x Wand-028 | KELLERGESCHOSS
Wand-031 | KELLERGESCHOSS
Wand-036 | KELLERGESCHOSS

# IfcWallStandardCase: 05_ALLGEMEIN - TRAGENDE BAUTEILE 136, Wand-030
In: KELLERGESCHOSS
Type - PredefinedType: ELEMENTEDWALL
Classification: Elementwand (ARCHICAD Klassifizierung); Material: 05_ALLGEMEIN - TRAGENDE BAUTEILE 0.135904 m
Pset_WallCommon - ThermalTransmittance: 0; LoadBearing: yes; IsExternal: yes
AC_Pset_RenovationAndPhasing - Renovation Status: Existing

# IfcWallStandardCase: 05_ALLGEMEIN - TRAGENDE BAUTEILE 137, Wand-028
In: KELLERGESCHOSS
Type - PredefinedType: ELEMENTEDWALL
Classification: Elementwand (ARCHICAD Klassifizierung); Material: 05_ALLGEMEIN - TRAGENDE BAUTEILE 0.136641 m
Pset_WallCommon - ThermalTransmittance: 0; LoadBearing: yes; IsExternal: yes
AC_Pset_RenovationAndPhasing - Renovation Status: Existing

# IfcWallStandardCase: 05_ALLGEMEIN - TRAGENDE BAUTEILE 140, Wand-039
In: 2.OBERGESCHOSS
Type - PredefinedType: ELEMENTEDWALL
Classification: Elementwand (ARCHICAD Klassifizierung); Material: 05_ALLGEMEIN - TRAGENDE BAUTEILE 0.14 m
Pset_WallCommon - ThermalTransmittance: 0; LoadBearing: yes; IsExternal: yes
AC_Pset_RenovationAndPhasing - Renovation Status: Existing

# IfcWallStandardCase: 05_ALLGEMEIN - TRAGENDE BAUTEILE 150 (5)
Type - PredefinedType: ELEMENTEDWALL
Classification: Elementwand (ARCHICAD Klassifizierung); Material: 05_ALLGEMEIN - TRAGENDE BAUTEILE 0.15 m
Pset_WallCommon - ThermalTransmittance: 0; LoadBearing: yes; IsExternal: yes
AC_Pset_RenovationAndPhasing - Renovation Status: Existing
Name | In
Wand-030 | DACHGESCHOSS
Wand-036 | DACHGESCHOSS
Wand-039 | 2.OBERGESCHOSS
Wand-040 | 2.OBERGESCHOSS
Wand-031 | KELLERGESCHOSS

# IfcWallStandardCase: 05_ALLGEMEIN - TRAGENDE BAUTEILE 160, Wand-039
In: 2.OBERGESCHOSS
Type - PredefinedType: ELEMENTEDWALL
Classification: Elementwand (ARCHICAD Klassifizierung); Material: 05_ALLGEMEIN - TRAGENDE BAUTEILE 0.16 m
Pset_WallCommon - ThermalTransmittance: 0; LoadBearing: yes; IsExternal: yes
AC_Pset_RenovationAndPhasing - Renovation Status: Existing

# IfcWallStandardCase: 05_ALLGEMEIN - TRAGENDE BAUTEILE 171, Wand-037
In: 2.OBERGESCHOSS
Type - PredefinedType: ELEMENTEDWALL
Classification: Elementwand (ARCHICAD Klassifizierung); Material: 05_ALLGEMEIN - TRAGENDE BAUTEILE 0.171 m
Pset_WallCommon - ThermalTransmittance: 0; LoadBearing: yes; IsExternal: yes
AC_Pset_RenovationAndPhasing - Renovation Status: Existing

# IfcWallStandardCase: 05_ALLGEMEIN - TRAGENDE BAUTEILE 176, Wand-028
In: KELLERGESCHOSS
Type - PredefinedType: ELEMENTEDWALL
Classification: Elementwand (ARCHICAD Klassifizierung); Material: 05_ALLGEMEIN - TRAGENDE BAUTEILE 0.175574 m
Pset_WallCommon - ThermalTransmittance: 0; LoadBearing: yes; IsExternal: yes
AC_Pset_RenovationAndPhasing - Renovation Status: Existing

# IfcWallStandardCase: 05_ALLGEMEIN - TRAGENDE BAUTEILE 200 (14)
Type - PredefinedType: ELEMENTEDWALL
Classification: Elementwand (ARCHICAD Klassifizierung); Material: 05_ALLGEMEIN - TRAGENDE BAUTEILE 0.2 m
Pset_WallCommon - ThermalTransmittance: 0; LoadBearing: yes; IsExternal: yes
AC_Pset_RenovationAndPhasing - Renovation Status: Existing
Name | In
2 x Wand-030 | SPITZBODEN
Wand-031 | SPITZBODEN
Wand-029 | DACHGESCHOSS
Wand-036 | 2.OBERGESCHOSS
Wand-037 | 2.OBERGESCHOSS
Wand-034 | ERDGESCHOSS
Wand-035 | ERDGESCHOSS
Wand-038 | ERDGESCHOSS
Wand-039 | ERDGESCHOSS
2 x Wand-030 | KELLERGESCHOSS
Wand-032 | KELLERGESCHOSS
Wand-035 | KELLERGESCHOSS

# IfcWallStandardCase: 05_ALLGEMEIN - TRAGENDE BAUTEILE 224, Wand-030
In: DACHGESCHOSS
Type - PredefinedType: ELEMENTEDWALL
Classification: Elementwand (ARCHICAD Klassifizierung); Material: 05_ALLGEMEIN - TRAGENDE BAUTEILE 0.223807 m
Pset_WallCommon - ThermalTransmittance: 0; LoadBearing: yes; IsExternal: yes
AC_Pset_RenovationAndPhasing - Renovation Status: Existing

# IfcWallStandardCase: 05_ALLGEMEIN - TRAGENDE BAUTEILE 230 (5)
Type - PredefinedType: ELEMENTEDWALL
Classification: Elementwand (ARCHICAD Klassifizierung); Material: 05_ALLGEMEIN - TRAGENDE BAUTEILE 0.23 m
Pset_WallCommon - ThermalTransmittance: 0; LoadBearing: yes; IsExternal: yes
AC_Pset_RenovationAndPhasing - Renovation Status: Existing
Name | In
Wand-029 | 2.OBERGESCHOSS
Wand-042 | 1.OBERGESCHOSS
Wand-030 | ERDGESCHOSS
Wand-030 | KELLERGESCHOSS
Wand-031 | KELLERGESCHOSS

# IfcWallStandardCase: 05_ALLGEMEIN - TRAGENDE BAUTEILE 240 (5)
Type - PredefinedType: ELEMENTEDWALL
Classification: Elementwand (ARCHICAD Klassifizierung); Material: 05_ALLGEMEIN - TRAGENDE BAUTEILE 0.24 m
Pset_WallCommon - ThermalTransmittance: 0; LoadBearing: yes; IsExternal: yes
AC_Pset_RenovationAndPhasing - Renovation Status: Existing
Name | In
Wand-030 | ERDGESCHOSS
2 x Wand-031 | ERDGESCHOSS
2 x Wand-031 | KELLERGESCHOSS

# IfcWallStandardCase: 05_ALLGEMEIN - TRAGENDE BAUTEILE 250 (20)
Type - PredefinedType: ELEMENTEDWALL
Classification: Elementwand (ARCHICAD Klassifizierung); Material: 05_ALLGEMEIN - TRAGENDE BAUTEILE 0.25 m
Pset_WallCommon - ThermalTransmittance: 0; LoadBearing: yes; IsExternal: yes
AC_Pset_RenovationAndPhasing - Renovation Status: Existing
Name | In
Wand-030 | ERDGESCHOSS
Wand-039 | ERDGESCHOSS
2 x Wand-030 | KELLERGESCHOSS
2 x Wand-031 | KELLERGESCHOSS
Wand-034 | KELLERGESCHOSS
Wand-035 | KELLERGESCHOSS
Wand-036 | KELLERGESCHOSS
Wand-037 | KELLERGESCHOSS
Wand-038 | KELLERGESCHOSS
Wand-039 | KELLERGESCHOSS
Wand-040 | KELLERGESCHOSS
2 x Wand-041 | KELLERGESCHOSS
2 x Wand-042 | KELLERGESCHOSS
Wand-043 | KELLERGESCHOSS
Wand-044 | KELLERGESCHOSS
Wand-045 | KELLERGESCHOSS

# IfcWallStandardCase: 05_ALLGEMEIN - TRAGENDE BAUTEILE 255, Wand-030
In: ERDGESCHOSS
Type - PredefinedType: ELEMENTEDWALL
Classification: Elementwand (ARCHICAD Klassifizierung); Material: 05_ALLGEMEIN - TRAGENDE BAUTEILE 0.255399 m
Pset_WallCommon - ThermalTransmittance: 0; LoadBearing: yes; IsExternal: yes
AC_Pset_RenovationAndPhasing - Renovation Status: Existing

# IfcWallStandardCase: 05_ALLGEMEIN - TRAGENDE BAUTEILE 260 (2)
In: KELLERGESCHOSS
Type - PredefinedType: ELEMENTEDWALL
Classification: Elementwand (ARCHICAD Klassifizierung); Material: 05_ALLGEMEIN - TRAGENDE BAUTEILE 0.26 m
Pset_WallCommon - ThermalTransmittance: 0; LoadBearing: yes; IsExternal: yes
AC_Pset_RenovationAndPhasing - Renovation Status: Existing
Name
Wand-028
Wand-031

# IfcWallStandardCase: 05_ALLGEMEIN - TRAGENDE BAUTEILE 264, Wand-038
In: KELLERGESCHOSS
Type - PredefinedType: ELEMENTEDWALL
Classification: Elementwand (ARCHICAD Klassifizierung); Material: 05_ALLGEMEIN - TRAGENDE BAUTEILE 0.263583 m
Pset_WallCommon - ThermalTransmittance: 0; LoadBearing: yes; IsExternal: yes
AC_Pset_RenovationAndPhasing - Renovation Status: Existing

# IfcWallStandardCase: 05_ALLGEMEIN - TRAGENDE BAUTEILE 270 (5)
Type - PredefinedType: ELEMENTEDWALL
Classification: Elementwand (ARCHICAD Klassifizierung); Material: 05_ALLGEMEIN - TRAGENDE BAUTEILE 0.27 m
Pset_WallCommon - ThermalTransmittance: 0; LoadBearing: yes; IsExternal: yes
AC_Pset_RenovationAndPhasing - Renovation Status: Existing
Name | In
2 x Wand-039 | 2.OBERGESCHOSS
Wand-032 | KELLERGESCHOSS
2 x Wand-039 | KELLERGESCHOSS

# IfcWallStandardCase: 05_ALLGEMEIN - TRAGENDE BAUTEILE 280 (10)
Type - PredefinedType: ELEMENTEDWALL
Classification: Elementwand (ARCHICAD Klassifizierung); Material: 05_ALLGEMEIN - TRAGENDE BAUTEILE 0.28 m
Pset_WallCommon - ThermalTransmittance: 0; LoadBearing: yes; IsExternal: yes
AC_Pset_RenovationAndPhasing - Renovation Status: Existing
Name | In
Wand-036 | DACHGESCHOSS
Wand-036 | 2.OBERGESCHOSS
Wand-040 | 2.OBERGESCHOSS
Wand-038 | 1.OBERGESCHOSS
Wand-037 | ERDGESCHOSS
Wand-030 | KELLERGESCHOSS
2 x Wand-031 | KELLERGESCHOSS
Wand-037 | KELLERGESCHOSS
Wand-039 | KELLERGESCHOSS

# IfcWallStandardCase: 05_ALLGEMEIN - TRAGENDE BAUTEILE 290 (5)
Type - PredefinedType: ELEMENTEDWALL
Classification: Elementwand (ARCHICAD Klassifizierung); Material: 05_ALLGEMEIN - TRAGENDE BAUTEILE 0.29 m
Pset_WallCommon - ThermalTransmittance: 0; LoadBearing: yes; IsExternal: yes
AC_Pset_RenovationAndPhasing - Renovation Status: Existing
Name | In
Wand-036 | 2.OBERGESCHOSS
2 x Wand-039 | 2.OBERGESCHOSS
Wand-035 | ERDGESCHOSS
Wand-035 | KELLERGESCHOSS

# IfcWallStandardCase: 05_ALLGEMEIN - TRAGENDE BAUTEILE 30 (3)
Type - PredefinedType: ELEMENTEDWALL
Classification: Elementwand (ARCHICAD Klassifizierung); Material: 05_ALLGEMEIN - TRAGENDE BAUTEILE 0.03 m
Pset_WallCommon - ThermalTransmittance: 0; LoadBearing: yes; IsExternal: yes
AC_Pset_RenovationAndPhasing - Renovation Status: Existing
Name | In
Wand-040 | ERDGESCHOSS
Wand-041 | ERDGESCHOSS
Wand-049 | KELLERGESCHOSS

# IfcWallStandardCase: 05_ALLGEMEIN - TRAGENDE BAUTEILE 300, Wand-030
In: KELLERGESCHOSS
Type - PredefinedType: ELEMENTEDWALL
Classification: Elementwand (ARCHICAD Klassifizierung); Material: 05_ALLGEMEIN - TRAGENDE BAUTEILE 0.3 m
Pset_WallCommon - ThermalTransmittance: 0; LoadBearing: yes; IsExternal: yes
AC_Pset_RenovationAndPhasing - Renovation Status: Existing

# IfcWallStandardCase: 05_ALLGEMEIN - TRAGENDE BAUTEILE 330, Wand-030
In: ERDGESCHOSS
Type - PredefinedType: ELEMENTEDWALL
Classification: Elementwand (ARCHICAD Klassifizierung); Material: 05_ALLGEMEIN - TRAGENDE BAUTEILE 0.33 m
Pset_WallCommon - ThermalTransmittance: 0; LoadBearing: yes; IsExternal: yes
AC_Pset_RenovationAndPhasing - Renovation Status: Existing

# IfcWallStandardCase: 05_ALLGEMEIN - TRAGENDE BAUTEILE 340, Wand-031
In: KELLERGESCHOSS
Type - PredefinedType: ELEMENTEDWALL
Classification: Elementwand (ARCHICAD Klassifizierung); Material: 05_ALLGEMEIN - TRAGENDE BAUTEILE 0.34 m
Pset_WallCommon - ThermalTransmittance: 0; LoadBearing: yes; IsExternal: yes
AC_Pset_RenovationAndPhasing - Renovation Status: Existing

# IfcWallStandardCase: 05_ALLGEMEIN - TRAGENDE BAUTEILE 350 (2)
Type - PredefinedType: ELEMENTEDWALL
Classification: Elementwand (ARCHICAD Klassifizierung); Material: 05_ALLGEMEIN - TRAGENDE BAUTEILE 0.35 m
Pset_WallCommon - ThermalTransmittance: 0; LoadBearing: yes; IsExternal: yes
AC_Pset_RenovationAndPhasing - Renovation Status: Existing
Name | In
Wand-029 | 2.OBERGESCHOSS
Wand-031 | ERDGESCHOSS

# IfcWallStandardCase: 05_ALLGEMEIN - TRAGENDE BAUTEILE 360, Wand-031
In: KELLERGESCHOSS
Type - PredefinedType: ELEMENTEDWALL
Classification: Elementwand (ARCHICAD Klassifizierung); Material: 05_ALLGEMEIN - TRAGENDE BAUTEILE 0.36 m
Pset_WallCommon - ThermalTransmittance: 0; LoadBearing: yes; IsExternal: yes
AC_Pset_RenovationAndPhasing - Renovation Status: Existing

# IfcWallStandardCase: 05_ALLGEMEIN - TRAGENDE BAUTEILE 365 (8)
In: KELLERGESCHOSS
Type - PredefinedType: ELEMENTEDWALL
Classification: Elementwand (ARCHICAD Klassifizierung); Material: 05_ALLGEMEIN - TRAGENDE BAUTEILE 0.365 m
Pset_WallCommon - ThermalTransmittance: 0; LoadBearing: yes; IsExternal: yes
AC_Pset_RenovationAndPhasing - Renovation Status: Existing
Name
Wand-030
Wand-031
Wand-032
Wand-033
Wand-034
Wand-035
2 x Wand-036

# IfcWallStandardCase: 05_ALLGEMEIN - TRAGENDE BAUTEILE 370, Wand-031
In: KELLERGESCHOSS
Type - PredefinedType: ELEMENTEDWALL
Classification: Elementwand (ARCHICAD Klassifizierung); Material: 05_ALLGEMEIN - TRAGENDE BAUTEILE 0.37 m
Pset_WallCommon - ThermalTransmittance: 0; LoadBearing: yes; IsExternal: yes
AC_Pset_RenovationAndPhasing - Renovation Status: Existing

# IfcWallStandardCase: 05_ALLGEMEIN - TRAGENDE BAUTEILE 380 (5)
Type - PredefinedType: ELEMENTEDWALL
Classification: Elementwand (ARCHICAD Klassifizierung); Material: 05_ALLGEMEIN - TRAGENDE BAUTEILE 0.38 m
Pset_WallCommon - ThermalTransmittance: 0; LoadBearing: yes; IsExternal: yes
AC_Pset_RenovationAndPhasing - Renovation Status: Existing
Name | In
2 x Wand-029 | 2.OBERGESCHOSS
Wand-034 | 1.OBERGESCHOSS
Wand-030 | ERDGESCHOSS
Wand-030 | KELLERGESCHOSS

# IfcWallStandardCase: 05_ALLGEMEIN - TRAGENDE BAUTEILE 390 (2)
In: ERDGESCHOSS
Type - PredefinedType: ELEMENTEDWALL
Classification: Elementwand (ARCHICAD Klassifizierung); Material: 05_ALLGEMEIN - TRAGENDE BAUTEILE 0.39 m
Pset_WallCommon - ThermalTransmittance: 0; LoadBearing: yes; IsExternal: yes
AC_Pset_RenovationAndPhasing - Renovation Status: Existing
Name
Wand-030
Wand-031

# IfcWallStandardCase: 05_ALLGEMEIN - TRAGENDE BAUTEILE 400 (44)
Type - PredefinedType: ELEMENTEDWALL
Classification: Elementwand (ARCHICAD Klassifizierung); Material: 05_ALLGEMEIN - TRAGENDE BAUTEILE 0.4 m
Pset_WallCommon - ThermalTransmittance: 0; LoadBearing: yes; IsExternal: yes
AC_Pset_RenovationAndPhasing - Renovation Status: Existing
Name | In
Wand-029 | DACHGESCHOSS
2 x Wand-040 | DACHGESCHOSS
2 x Wand-029 | 2.OBERGESCHOSS
Wand-030 | 2.OBERGESCHOSS
2 x Wand-033 | 2.OBERGESCHOSS
Wand-034 | 2.OBERGESCHOSS
Wand-035 | 2.OBERGESCHOSS
Wand-038 | 2.OBERGESCHOSS
3 x Wand-029 | 1.OBERGESCHOSS
3 x Wand-030 | 1.OBERGESCHOSS
Wand-031 | 1.OBERGESCHOSS
2 x Wand-033 | 1.OBERGESCHOSS
Wand-034 | 1.OBERGESCHOSS
2 x Wand-035 | 1.OBERGESCHOSS
Wand-037 | 1.OBERGESCHOSS
Wand-038 | 1.OBERGESCHOSS
5 x Wand-030 | ERDGESCHOSS
Wand-032 | ERDGESCHOSS
Wand-029 | KELLERGESCHOSS
6 x Wand-030 | KELLERGESCHOSS
Wand-031 | KELLERGESCHOSS
4 x Wand-033 | KELLERGESCHOSS
Wand-035 | KELLERGESCHOSS

# IfcWallStandardCase: 05_ALLGEMEIN - TRAGENDE BAUTEILE 405 (3)
Type - PredefinedType: ELEMENTEDWALL
Classification: Elementwand (ARCHICAD Klassifizierung); Material: 05_ALLGEMEIN - TRAGENDE BAUTEILE 0.405 m
Pset_WallCommon - ThermalTransmittance: 0; LoadBearing: yes; IsExternal: yes
AC_Pset_RenovationAndPhasing - Renovation Status: Existing
Name | In
2 x Wand-030 | ERDGESCHOSS
Wand-031 | KELLERGESCHOSS

# IfcWallStandardCase: 05_ALLGEMEIN - TRAGENDE BAUTEILE 410 (21)
Type - PredefinedType: ELEMENTEDWALL
Classification: Elementwand (ARCHICAD Klassifizierung); Material: 05_ALLGEMEIN - TRAGENDE BAUTEILE 0.41 m
Pset_WallCommon - ThermalTransmittance: 0; LoadBearing: yes; IsExternal: yes
AC_Pset_RenovationAndPhasing - Renovation Status: Existing
Name | In
4 x Wand-038 | 2.OBERGESCHOSS
Wand-039 | 2.OBERGESCHOSS
3 x Wand-038 | 1.OBERGESCHOSS
Wand-039 | 1.OBERGESCHOSS
Wand-036 | ERDGESCHOSS
2 x Wand-039 | ERDGESCHOSS
2 x Wand-030 | KELLERGESCHOSS
Wand-036 | KELLERGESCHOSS
2 x Wand-037 | KELLERGESCHOSS
3 x Wand-038 | KELLERGESCHOSS
Wand-039 | KELLERGESCHOSS

# IfcWallStandardCase: 05_ALLGEMEIN - TRAGENDE BAUTEILE 415 (9)
Type - PredefinedType: ELEMENTEDWALL
Classification: Elementwand (ARCHICAD Klassifizierung); Material: 05_ALLGEMEIN - TRAGENDE BAUTEILE 0.414616 m
Pset_WallCommon - ThermalTransmittance: 0; LoadBearing: yes; IsExternal: yes
AC_Pset_RenovationAndPhasing - Renovation Status: Existing
Name | In
3 x Wand-038 | 1.OBERGESCHOSS
Wand-039 | 1.OBERGESCHOSS
3 x Wand-040 | 1.OBERGESCHOSS
Wand-038 | ERDGESCHOSS
Wand-039 | ERDGESCHOSS

# IfcWallStandardCase: 05_ALLGEMEIN - TRAGENDE BAUTEILE 418, Wand-030
In: ERDGESCHOSS
Type - PredefinedType: ELEMENTEDWALL
Classification: Elementwand (ARCHICAD Klassifizierung); Material: 05_ALLGEMEIN - TRAGENDE BAUTEILE 0.418 m
Pset_WallCommon - ThermalTransmittance: 0; LoadBearing: yes; IsExternal: yes
AC_Pset_RenovationAndPhasing - Renovation Status: Existing

# IfcWallStandardCase: 05_ALLGEMEIN - TRAGENDE BAUTEILE 420 (16)
Type - PredefinedType: ELEMENTEDWALL
Classification: Elementwand (ARCHICAD Klassifizierung)
Pset_WallCommon - ThermalTransmittance: 0; LoadBearing: yes; IsExternal: yes
AC_Pset_RenovationAndPhasing - Renovation Status: Existing
Name | In | Material
2 x Wand-036 | 2.OBERGESCHOSS | 05_ALLGEMEIN - TRAGENDE BAUTEILE 0.42 m
Wand-037 | 2.OBERGESCHOSS | 05_ALLGEMEIN - TRAGENDE BAUTEILE 0.42 m
2 x Wand-039 | 2.OBERGESCHOSS | 05_ALLGEMEIN - TRAGENDE BAUTEILE 0.419634 m
3 x Wand-041 | 1.OBERGESCHOSS | 05_ALLGEMEIN - TRAGENDE BAUTEILE 0.42 m
Wand-042 | 1.OBERGESCHOSS | 05_ALLGEMEIN - TRAGENDE BAUTEILE 0.42 m
Wand-043 | 1.OBERGESCHOSS | 05_ALLGEMEIN - TRAGENDE BAUTEILE 0.42 m
4 x Wand-036 | ERDGESCHOSS | 05_ALLGEMEIN - TRAGENDE BAUTEILE 0.42 m
Wand-039 | ERDGESCHOSS | 05_ALLGEMEIN - TRAGENDE BAUTEILE 0.42 m
Wand-039 | KELLERGESCHOSS | 05_ALLGEMEIN - TRAGENDE BAUTEILE 0.42 m

# IfcWallStandardCase: 05_ALLGEMEIN - TRAGENDE BAUTEILE 424, Wand-043
In: ERDGESCHOSS
Type - PredefinedType: ELEMENTEDWALL
Classification: Elementwand (ARCHICAD Klassifizierung); Material: 05_ALLGEMEIN - TRAGENDE BAUTEILE 0.423553 m
Pset_WallCommon - ThermalTransmittance: 0; LoadBearing: yes; IsExternal: yes
AC_Pset_RenovationAndPhasing - Renovation Status: Existing

# IfcWallStandardCase: 05_ALLGEMEIN - TRAGENDE BAUTEILE 425, Wand-029
In: DACHGESCHOSS
Type - PredefinedType: ELEMENTEDWALL
Classification: Elementwand (ARCHICAD Klassifizierung); Material: 05_ALLGEMEIN - TRAGENDE BAUTEILE 0.425 m
Pset_WallCommon - ThermalTransmittance: 0; LoadBearing: yes; IsExternal: yes
AC_Pset_RenovationAndPhasing - Renovation Status: Existing

# IfcWallStandardCase: 05_ALLGEMEIN - TRAGENDE BAUTEILE 430 (2)
Type - PredefinedType: ELEMENTEDWALL
Classification: Elementwand (ARCHICAD Klassifizierung); Material: 05_ALLGEMEIN - TRAGENDE BAUTEILE 0.43 m
Pset_WallCommon - ThermalTransmittance: 0; LoadBearing: yes; IsExternal: yes
AC_Pset_RenovationAndPhasing - Renovation Status: Existing
Name | In
Wand-030 | ERDGESCHOSS
Wand-031 | KELLERGESCHOSS

# IfcWallStandardCase: 05_ALLGEMEIN - TRAGENDE BAUTEILE 431, Wand-043
In: ERDGESCHOSS
Type - PredefinedType: ELEMENTEDWALL
Classification: Elementwand (ARCHICAD Klassifizierung); Material: 05_ALLGEMEIN - TRAGENDE BAUTEILE 0.430884 m
Pset_WallCommon - ThermalTransmittance: 0; LoadBearing: yes; IsExternal: yes
AC_Pset_RenovationAndPhasing - Renovation Status: Existing

# IfcWallStandardCase: 05_ALLGEMEIN - TRAGENDE BAUTEILE 440, Wand-037
In: 2.OBERGESCHOSS
Type - PredefinedType: ELEMENTEDWALL
Classification: Elementwand (ARCHICAD Klassifizierung); Material: 05_ALLGEMEIN - TRAGENDE BAUTEILE 0.44 m
Pset_WallCommon - ThermalTransmittance: 0; LoadBearing: yes; IsExternal: yes
AC_Pset_RenovationAndPhasing - Renovation Status: Existing

# IfcWallStandardCase: 05_ALLGEMEIN - TRAGENDE BAUTEILE 450 (8)
Type - PredefinedType: ELEMENTEDWALL
Classification: Elementwand (ARCHICAD Klassifizierung); Material: 05_ALLGEMEIN - TRAGENDE BAUTEILE 0.45 m
Pset_WallCommon - ThermalTransmittance: 0; LoadBearing: yes; IsExternal: yes
AC_Pset_RenovationAndPhasing - Renovation Status: Existing
Name | In
5 x Wand-029 | 2.OBERGESCHOSS
2 x Wand-037 | 2.OBERGESCHOSS
Wand-036 | KELLERGESCHOSS

# IfcWallStandardCase: 05_ALLGEMEIN - TRAGENDE BAUTEILE 460, Wand-030
In: KELLERGESCHOSS
Type - PredefinedType: ELEMENTEDWALL
Classification: Elementwand (ARCHICAD Klassifizierung); Material: 05_ALLGEMEIN - TRAGENDE BAUTEILE 0.46 m
Pset_WallCommon - ThermalTransmittance: 0; LoadBearing: yes; IsExternal: yes
AC_Pset_RenovationAndPhasing - Renovation Status: Existing

# IfcWallStandardCase: 05_ALLGEMEIN - TRAGENDE BAUTEILE 47, Wand-038
In: 1.OBERGESCHOSS
Type - PredefinedType: ELEMENTEDWALL
Classification: Elementwand (ARCHICAD Klassifizierung); Material: 05_ALLGEMEIN - TRAGENDE BAUTEILE 0.047 m
Pset_WallCommon - ThermalTransmittance: 0; LoadBearing: yes; IsExternal: yes
AC_Pset_RenovationAndPhasing - Renovation Status: Existing

# IfcWallStandardCase: 05_ALLGEMEIN - TRAGENDE BAUTEILE 470 (5)
Type - PredefinedType: ELEMENTEDWALL
Classification: Elementwand (ARCHICAD Klassifizierung); Material: 05_ALLGEMEIN - TRAGENDE BAUTEILE 0.47 m
Pset_WallCommon - ThermalTransmittance: 0; LoadBearing: yes; IsExternal: yes
AC_Pset_RenovationAndPhasing - Renovation Status: Existing
Name | In
2 x Wand-029 | DACHGESCHOSS
Wand-029 | 2.OBERGESCHOSS
Wand-030 | ERDGESCHOSS
Wand-030 | KELLERGESCHOSS

# IfcWallStandardCase: 05_ALLGEMEIN - TRAGENDE BAUTEILE 475, Wand-029
In: 2.OBERGESCHOSS
Type - PredefinedType: ELEMENTEDWALL
Classification: Elementwand (ARCHICAD Klassifizierung); Material: 05_ALLGEMEIN - TRAGENDE BAUTEILE 0.475 m
Pset_WallCommon - ThermalTransmittance: 0; LoadBearing: yes; IsExternal: yes
AC_Pset_RenovationAndPhasing - Renovation Status: Existing

# IfcWallStandardCase: 05_ALLGEMEIN - TRAGENDE BAUTEILE 490, Wand-039
In: 2.OBERGESCHOSS
Type - PredefinedType: ELEMENTEDWALL
Classification: Elementwand (ARCHICAD Klassifizierung); Material: 05_ALLGEMEIN - TRAGENDE BAUTEILE 0.49 m
Pset_WallCommon - ThermalTransmittance: 0; LoadBearing: yes; IsExternal: yes
AC_Pset_RenovationAndPhasing - Renovation Status: Existing

# IfcWallStandardCase: 05_ALLGEMEIN - TRAGENDE BAUTEILE 504 (11)
Type - PredefinedType: ELEMENTEDWALL
Classification: Elementwand (ARCHICAD Klassifizierung); Material: 05_ALLGEMEIN - TRAGENDE BAUTEILE 0.504364 m
Pset_WallCommon - ThermalTransmittance: 0; LoadBearing: yes; IsExternal: yes
AC_Pset_RenovationAndPhasing - Renovation Status: Existing
Name | In
3 x Wand-043 | 1.OBERGESCHOSS
8 x Wand-043 | KELLERGESCHOSS

# IfcWallStandardCase: 05_ALLGEMEIN - TRAGENDE BAUTEILE 510 (4)
Type - PredefinedType: ELEMENTEDWALL
Classification: Elementwand (ARCHICAD Klassifizierung); Material: 05_ALLGEMEIN - TRAGENDE BAUTEILE 0.51 m
Pset_WallCommon - ThermalTransmittance: 0; LoadBearing: yes; IsExternal: yes
AC_Pset_RenovationAndPhasing - Renovation Status: Existing
Name | In
Wand-029 | 2.OBERGESCHOSS
Wand-029 | 1.OBERGESCHOSS
Wand-039 | 1.OBERGESCHOSS
Wand-030 | KELLERGESCHOSS

# IfcWallStandardCase: 05_ALLGEMEIN - TRAGENDE BAUTEILE 518 (4)
In: 2.OBERGESCHOSS
Type - PredefinedType: ELEMENTEDWALL
Classification: Elementwand (ARCHICAD Klassifizierung); Material: 05_ALLGEMEIN - TRAGENDE BAUTEILE 0.518 m
Pset_WallCommon - ThermalTransmittance: 0; LoadBearing: yes; IsExternal: yes
AC_Pset_RenovationAndPhasing - Renovation Status: Existing

# IfcWallStandardCase: 05_ALLGEMEIN - TRAGENDE BAUTEILE 52, Wand-031
In: ERDGESCHOSS
Type - PredefinedType: ELEMENTEDWALL
Classification: Elementwand (ARCHICAD Klassifizierung); Material: 05_ALLGEMEIN - TRAGENDE BAUTEILE 0.052 m
Pset_WallCommon - ThermalTransmittance: 0; LoadBearing: yes; IsExternal: yes
AC_Pset_RenovationAndPhasing - Renovation Status: Existing

# IfcWallStandardCase: 05_ALLGEMEIN - TRAGENDE BAUTEILE 520 (3)
Type - PredefinedType: ELEMENTEDWALL
Classification: Elementwand (ARCHICAD Klassifizierung); Material: 05_ALLGEMEIN - TRAGENDE BAUTEILE 0.52 m
Pset_WallCommon - ThermalTransmittance: 0; LoadBearing: yes; IsExternal: yes
AC_Pset_RenovationAndPhasing - Renovation Status: Existing
Name | In
Wand-036 | 1.OBERGESCHOSS
Wand-029 | ERDGESCHOSS
Wand-031 | ERDGESCHOSS

# IfcWallStandardCase: 05_ALLGEMEIN - TRAGENDE BAUTEILE 530 (4)
Type - PredefinedType: ELEMENTEDWALL
Classification: Elementwand (ARCHICAD Klassifizierung); Material: 05_ALLGEMEIN - TRAGENDE BAUTEILE 0.53 m
Pset_WallCommon - ThermalTransmittance: 0; LoadBearing: yes; IsExternal: yes
AC_Pset_RenovationAndPhasing - Renovation Status: Existing
Name | In
Wand-028 | 1.OBERGESCHOSS
Wand-036 | 1.OBERGESCHOSS
Wand-028 | ERDGESCHOSS
Wand-036 | ERDGESCHOSS

# IfcWallStandardCase: 05_ALLGEMEIN - TRAGENDE BAUTEILE 535, Wand-030
In: ERDGESCHOSS
Type - PredefinedType: ELEMENTEDWALL
Classification: Elementwand (ARCHICAD Klassifizierung); Material: 05_ALLGEMEIN - TRAGENDE BAUTEILE 0.535 m
Pset_WallCommon - ThermalTransmittance: 0; LoadBearing: yes; IsExternal: yes
AC_Pset_RenovationAndPhasing - Renovation Status: Existing

# IfcWallStandardCase: 05_ALLGEMEIN - TRAGENDE BAUTEILE 540, Wand-032
In: ERDGESCHOSS
Type - PredefinedType: ELEMENTEDWALL
Classification: Elementwand (ARCHICAD Klassifizierung); Material: 05_ALLGEMEIN - TRAGENDE BAUTEILE 0.54 m
Pset_WallCommon - ThermalTransmittance: 0; LoadBearing: yes; IsExternal: yes
AC_Pset_RenovationAndPhasing - Renovation Status: Existing

# IfcWallStandardCase: 05_ALLGEMEIN - TRAGENDE BAUTEILE 547, Wand-037
In: KELLERGESCHOSS
Type - PredefinedType: ELEMENTEDWALL
Classification: Elementwand (ARCHICAD Klassifizierung); Material: 05_ALLGEMEIN - TRAGENDE BAUTEILE 0.547 m
Pset_WallCommon - ThermalTransmittance: 0; LoadBearing: yes; IsExternal: yes
AC_Pset_RenovationAndPhasing - Renovation Status: Existing

# IfcWallStandardCase: 05_ALLGEMEIN - TRAGENDE BAUTEILE 550, Wand-039
In: 2.OBERGESCHOSS
Type - PredefinedType: ELEMENTEDWALL
Classification: Elementwand (ARCHICAD Klassifizierung); Material: 05_ALLGEMEIN - TRAGENDE BAUTEILE 0.55 m
Pset_WallCommon - ThermalTransmittance: 0; LoadBearing: yes; IsExternal: yes
AC_Pset_RenovationAndPhasing - Renovation Status: Existing

# IfcWallStandardCase: 05_ALLGEMEIN - TRAGENDE BAUTEILE 554, Wand-039
In: KELLERGESCHOSS
Type - PredefinedType: ELEMENTEDWALL
Classification: Elementwand (ARCHICAD Klassifizierung); Material: 05_ALLGEMEIN - TRAGENDE BAUTEILE 0.55439 m
Pset_WallCommon - ThermalTransmittance: 0; LoadBearing: yes; IsExternal: yes
AC_Pset_RenovationAndPhasing - Renovation Status: Existing

# IfcWallStandardCase: 05_ALLGEMEIN - TRAGENDE BAUTEILE 560 (5)
Type - PredefinedType: ELEMENTEDWALL
Classification: Elementwand (ARCHICAD Klassifizierung); Material: 05_ALLGEMEIN - TRAGENDE BAUTEILE 0.56 m
Pset_WallCommon - ThermalTransmittance: 0; LoadBearing: yes; IsExternal: yes
AC_Pset_RenovationAndPhasing - Renovation Status: Existing
Name | In
Wand-036 | 1.OBERGESCHOSS
Wand-030 | ERDGESCHOSS
Wand-029 | KELLERGESCHOSS
Wand-030 | KELLERGESCHOSS
Wand-038 | KELLERGESCHOSS

# IfcWallStandardCase: 05_ALLGEMEIN - TRAGENDE BAUTEILE 570, Wand-036
In: ERDGESCHOSS
Type - PredefinedType: ELEMENTEDWALL
Classification: Elementwand (ARCHICAD Klassifizierung); Material: 05_ALLGEMEIN - TRAGENDE BAUTEILE 0.57 m
Pset_WallCommon - ThermalTransmittance: 0; LoadBearing: yes; IsExternal: yes
AC_Pset_RenovationAndPhasing - Renovation Status: Existing

# IfcWallStandardCase: 05_ALLGEMEIN - TRAGENDE BAUTEILE 580 (7)
Type - PredefinedType: ELEMENTEDWALL
Classification: Elementwand (ARCHICAD Klassifizierung); Material: 05_ALLGEMEIN - TRAGENDE BAUTEILE 0.58 m
Pset_WallCommon - ThermalTransmittance: 0; LoadBearing: yes; IsExternal: yes
AC_Pset_RenovationAndPhasing - Renovation Status: Existing
Name | In
Wand-038 | 1.OBERGESCHOSS
Wand-039 | 1.OBERGESCHOSS
Wand-037 | ERDGESCHOSS
Wand-029 | KELLERGESCHOSS
Wand-030 | KELLERGESCHOSS
Wand-036 | KELLERGESCHOSS
Wand-038 | KELLERGESCHOSS

# IfcWallStandardCase: 05_ALLGEMEIN - TRAGENDE BAUTEILE 586, Wand-039
In: KELLERGESCHOSS
Type - PredefinedType: ELEMENTEDWALL
Classification: Elementwand (ARCHICAD Klassifizierung); Material: 05_ALLGEMEIN - TRAGENDE BAUTEILE 0.585873 m
Pset_WallCommon - ThermalTransmittance: 0; LoadBearing: yes; IsExternal: yes
AC_Pset_RenovationAndPhasing - Renovation Status: Existing

# IfcWallStandardCase: 05_ALLGEMEIN - TRAGENDE BAUTEILE 590 (3)
Type - PredefinedType: ELEMENTEDWALL
Classification: Elementwand (ARCHICAD Klassifizierung); Material: 05_ALLGEMEIN - TRAGENDE BAUTEILE 0.59 m
Pset_WallCommon - ThermalTransmittance: 0; LoadBearing: yes; IsExternal: yes
AC_Pset_RenovationAndPhasing - Renovation Status: Existing
Name | In
Wand-030 | 1.OBERGESCHOSS
Wand-038 | 1.OBERGESCHOSS
Wand-028 | KELLERGESCHOSS

# IfcWallStandardCase: 05_ALLGEMEIN - TRAGENDE BAUTEILE 60 (2)
Type - PredefinedType: ELEMENTEDWALL
Classification: Elementwand (ARCHICAD Klassifizierung); Material: 05_ALLGEMEIN - TRAGENDE BAUTEILE 0.06 m
Pset_WallCommon - ThermalTransmittance: 0; LoadBearing: yes; IsExternal: yes
AC_Pset_RenovationAndPhasing - Renovation Status: Existing
Name | In
Wand-032 | ERDGESCHOSS
Wand-031 | KELLERGESCHOSS

# IfcWallStandardCase: 05_ALLGEMEIN - TRAGENDE BAUTEILE 600 (3)
Type - PredefinedType: ELEMENTEDWALL
Classification: Elementwand (ARCHICAD Klassifizierung); Material: 05_ALLGEMEIN - TRAGENDE BAUTEILE 0.6 m
Pset_WallCommon - ThermalTransmittance: 0; LoadBearing: yes; IsExternal: yes
AC_Pset_RenovationAndPhasing - Renovation Status: Existing
Name | In
2 x Wand-030 | 2.OBERGESCHOSS
Wand-041 | 1.OBERGESCHOSS

# IfcWallStandardCase: 05_ALLGEMEIN - TRAGENDE BAUTEILE 620, Wand-032
In: KELLERGESCHOSS
Type - PredefinedType: ELEMENTEDWALL
Classification: Elementwand (ARCHICAD Klassifizierung); Material: 05_ALLGEMEIN - TRAGENDE BAUTEILE 0.62 m
Pset_WallCommon - ThermalTransmittance: 0; LoadBearing: yes; IsExternal: yes
AC_Pset_RenovationAndPhasing - Renovation Status: Existing

# IfcWallStandardCase: 05_ALLGEMEIN - TRAGENDE BAUTEILE 790 (3)
In: 1.OBERGESCHOSS
Type - PredefinedType: ELEMENTEDWALL
Classification: Elementwand (ARCHICAD Klassifizierung); Material: 05_ALLGEMEIN - TRAGENDE BAUTEILE 0.79 m
Pset_WallCommon - ThermalTransmittance: 0; LoadBearing: yes; IsExternal: yes
AC_Pset_RenovationAndPhasing - Renovation Status: Existing

# IfcWallStandardCase: 05_ALLGEMEIN - TRAGENDE BAUTEILE 80 (2)
Type - PredefinedType: ELEMENTEDWALL
Classification: Elementwand (ARCHICAD Klassifizierung); Material: 05_ALLGEMEIN - TRAGENDE BAUTEILE 0.08 m
Pset_WallCommon - ThermalTransmittance: 0; LoadBearing: yes; IsExternal: yes
AC_Pset_RenovationAndPhasing - Renovation Status: Existing
Name | In
Wand-038 | ERDGESCHOSS
Wand-030 | KELLERGESCHOSS

# IfcWallStandardCase: 05_ALLGEMEIN - TRAGENDE BAUTEILE 82 (3)
Type - PredefinedType: ELEMENTEDWALL
Classification: Elementwand (ARCHICAD Klassifizierung)
Pset_WallCommon - ThermalTransmittance: 0; LoadBearing: yes; IsExternal: yes
AC_Pset_RenovationAndPhasing - Renovation Status: Existing
Name | In | Material
Wand-038 | 2.OBERGESCHOSS | 05_ALLGEMEIN - TRAGENDE BAUTEILE 0.082 m
Wand-038 | 1.OBERGESCHOSS | 05_ALLGEMEIN - TRAGENDE BAUTEILE 0.0820227 m
Wand-039 | 1.OBERGESCHOSS | 05_ALLGEMEIN - TRAGENDE BAUTEILE 0.0820227 m

# IfcWallStandardCase: 05_ALLGEMEIN - TRAGENDE BAUTEILE 850, Wand-029
In: 2.OBERGESCHOSS
Type - PredefinedType: ELEMENTEDWALL
Classification: Elementwand (ARCHICAD Klassifizierung); Material: 05_ALLGEMEIN - TRAGENDE BAUTEILE 0.85 m
Pset_WallCommon - ThermalTransmittance: 0; LoadBearing: yes; IsExternal: yes
AC_Pset_RenovationAndPhasing - Renovation Status: Existing

# IfcWallStandardCase: 05_ALLGEMEIN - TRAGENDE BAUTEILE 96, Wand-042
In: 1.OBERGESCHOSS
Type - PredefinedType: ELEMENTEDWALL
Classification: Elementwand (ARCHICAD Klassifizierung); Material: 05_ALLGEMEIN - TRAGENDE BAUTEILE 0.0959783 m
Pset_WallCommon - ThermalTransmittance: 0; LoadBearing: yes; IsExternal: yes
AC_Pset_RenovationAndPhasing - Renovation Status: Existing

# IfcWallStandardCase: 43_Gipskarton 100 (64)
Type - PredefinedType: ELEMENTEDWALL
Classification: Elementwand (ARCHICAD Klassifizierung); Material: 43_Gipskarton 0.1 m
Pset_WallCommon - ThermalTransmittance: 0; LoadBearing: yes; IsExternal: yes
AC_Pset_RenovationAndPhasing - Renovation Status: Existing
Name | In
2 x Wand-036 | 2.OBERGESCHOSS
3 x Wand-037 | 2.OBERGESCHOSS
Wand-038 | 2.OBERGESCHOSS
4 x Wand-039 | 2.OBERGESCHOSS
6 x Wand-040 | 2.OBERGESCHOSS
Wand-041 | 2.OBERGESCHOSS
Wand-042 | 2.OBERGESCHOSS
Wand-043 | 2.OBERGESCHOSS
Wand-038 | 1.OBERGESCHOSS
Wand-039 | 1.OBERGESCHOSS
15 x Wand-040 | 1.OBERGESCHOSS
3 x Wand-041 | 1.OBERGESCHOSS
2 x Wand-042 | 1.OBERGESCHOSS
Wand-030 | ERDGESCHOSS
Wand-038 | ERDGESCHOSS
2 x Wand-039 | ERDGESCHOSS
2 x Wand-040 | ERDGESCHOSS
Wand-030 | KELLERGESCHOSS
10 x Wand-038 | KELLERGESCHOSS
6 x Wand-039 | KELLERGESCHOSS

# IfcWallStandardCase: 43_Gipskarton 103, Wand-040
In: 1.OBERGESCHOSS
Type - PredefinedType: ELEMENTEDWALL
Classification: Elementwand (ARCHICAD Klassifizierung); Material: 43_Gipskarton 0.103444 m
Pset_WallCommon - ThermalTransmittance: 0; LoadBearing: yes; IsExternal: yes
AC_Pset_RenovationAndPhasing - Renovation Status: Existing

# IfcWallStandardCase: 43_Gipskarton 105 (6)
In: ERDGESCHOSS
Type - PredefinedType: ELEMENTEDWALL
Classification: Elementwand (ARCHICAD Klassifizierung); Material: 43_Gipskarton 0.105 m
Pset_WallCommon - ThermalTransmittance: 0; LoadBearing: yes; IsExternal: yes
AC_Pset_RenovationAndPhasing - Renovation Status: Existing

# IfcWallStandardCase: 43_Gipskarton 110 (3)
In: KELLERGESCHOSS
Type - PredefinedType: ELEMENTEDWALL
Classification: Elementwand (ARCHICAD Klassifizierung); Material: 43_Gipskarton 0.11 m
Pset_WallCommon - ThermalTransmittance: 0; LoadBearing: yes; IsExternal: yes
AC_Pset_RenovationAndPhasing - Renovation Status: Existing
Name
Wand-031
Wand-038
Wand-039

# IfcWallStandardCase: 43_Gipskarton 112 (2)
In: ERDGESCHOSS
Type - PredefinedType: ELEMENTEDWALL
Classification: Elementwand (ARCHICAD Klassifizierung); Material: 43_Gipskarton 0.111969 m
Pset_WallCommon - ThermalTransmittance: 0; LoadBearing: yes; IsExternal: yes
AC_Pset_RenovationAndPhasing - Renovation Status: Existing

# IfcWallStandardCase: 43_Gipskarton 120, Wand-039
In: 2.OBERGESCHOSS
Type - PredefinedType: ELEMENTEDWALL
Classification: Elementwand (ARCHICAD Klassifizierung); Material: 43_Gipskarton 0.12 m
Pset_WallCommon - ThermalTransmittance: 0; LoadBearing: yes; IsExternal: yes
AC_Pset_RenovationAndPhasing - Renovation Status: Existing

# IfcWallStandardCase: 43_Gipskarton 122 (3)
In: ERDGESCHOSS
Type - PredefinedType: ELEMENTEDWALL
Classification: Elementwand (ARCHICAD Klassifizierung); Material: 43_Gipskarton 0.122212 m
Pset_WallCommon - ThermalTransmittance: 0; LoadBearing: yes; IsExternal: yes
AC_Pset_RenovationAndPhasing - Renovation Status: Existing

# IfcWallStandardCase: 43_Gipskarton 160, Wand-038
In: 2.OBERGESCHOSS
Type - PredefinedType: ELEMENTEDWALL
Classification: Elementwand (ARCHICAD Klassifizierung); Material: 43_Gipskarton 0.16 m
Pset_WallCommon - ThermalTransmittance: 0; LoadBearing: yes; IsExternal: yes
AC_Pset_RenovationAndPhasing - Renovation Status: Existing

# IfcWallStandardCase: 43_Gipskarton 230 (2)
In: KELLERGESCHOSS
Type - PredefinedType: ELEMENTEDWALL
Classification: Elementwand (ARCHICAD Klassifizierung); Material: 43_Gipskarton 0.23 m
Pset_WallCommon - ThermalTransmittance: 0; LoadBearing: yes; IsExternal: yes
AC_Pset_RenovationAndPhasing - Renovation Status: Existing

# IfcWallStandardCase: 43_Gipskarton 250, Wand-039
In: ERDGESCHOSS
Type - PredefinedType: ELEMENTEDWALL
Classification: Elementwand (ARCHICAD Klassifizierung); Material: 43_Gipskarton 0.25 m
Pset_WallCommon - ThermalTransmittance: 0; LoadBearing: yes; IsExternal: yes
AC_Pset_RenovationAndPhasing - Renovation Status: Existing

# IfcWallStandardCase: 43_Gipskarton 260, Wand-032
In: KELLERGESCHOSS
Type - PredefinedType: ELEMENTEDWALL
Classification: Elementwand (ARCHICAD Klassifizierung); Material: 43_Gipskarton 0.26 m
Pset_WallCommon - ThermalTransmittance: 0; LoadBearing: yes; IsExternal: yes
AC_Pset_RenovationAndPhasing - Renovation Status: Existing

# IfcWallStandardCase: 43_Gipskarton 270, Wand-032
In: KELLERGESCHOSS
Type - PredefinedType: ELEMENTEDWALL
Classification: Elementwand (ARCHICAD Klassifizierung); Material: 43_Gipskarton 0.27 m
Pset_WallCommon - ThermalTransmittance: 0; LoadBearing: yes; IsExternal: yes
AC_Pset_RenovationAndPhasing - Renovation Status: Existing

# IfcWallStandardCase: 43_Gipskarton 290, Wand-031
In: KELLERGESCHOSS
Type - PredefinedType: ELEMENTEDWALL
Classification: Elementwand (ARCHICAD Klassifizierung); Material: 43_Gipskarton 0.29 m
Pset_WallCommon - ThermalTransmittance: 0; LoadBearing: yes; IsExternal: yes
AC_Pset_RenovationAndPhasing - Renovation Status: Existing

# IfcWallStandardCase: 43_Gipskarton 30 (287)
Type - PredefinedType: ELEMENTEDWALL
Classification: Elementwand (ARCHICAD Klassifizierung); Material: 43_Gipskarton 0.03 m
Pset_WallCommon - ThermalTransmittance: 0; LoadBearing: yes; IsExternal: yes
AC_Pset_RenovationAndPhasing - Renovation Status: Existing
Name | In
3 x Wand-036 | 2.OBERGESCHOSS
13 x Wand-037 | 2.OBERGESCHOSS
6 x Wand-038 | 2.OBERGESCHOSS
4 x Wand-039 | 2.OBERGESCHOSS
4 x Wand-040 | 2.OBERGESCHOSS
Wand-041 | 2.OBERGESCHOSS
Wand-042 | 2.OBERGESCHOSS
5 x Wand-040 | 1.OBERGESCHOSS
8 x Wand-041 | 1.OBERGESCHOSS
8 x Wand-042 | 1.OBERGESCHOSS
4 x Wand-043 | 1.OBERGESCHOSS
Wand-044 | 1.OBERGESCHOSS
4 x Wand-031 | ERDGESCHOSS
14 x Wand-032 | ERDGESCHOSS
6 x Wand-033 | ERDGESCHOSS
3 x Wand-034 | ERDGESCHOSS
2 x Wand-035 | ERDGESCHOSS
4 x Wand-036 | ERDGESCHOSS
Wand-037 | ERDGESCHOSS
3 x Wand-038 | ERDGESCHOSS
13 x Wand-039 | ERDGESCHOSS
14 x Wand-040 | ERDGESCHOSS
15 x Wand-041 | ERDGESCHOSS
8 x Wand-042 | ERDGESCHOSS
5 x Wand-043 | ERDGESCHOSS
4 x Wand-044 | ERDGESCHOSS
7 x Wand-045 | ERDGESCHOSS
3 x Wand-046 | ERDGESCHOSS
2 x Wand-047 | ERDGESCHOSS
2 x Wand-048 | ERDGESCHOSS
3 x Wand-031 | KELLERGESCHOSS
9 x Wand-032 | KELLERGESCHOSS
2 x Wand-033 | KELLERGESCHOSS
7 x Wand-034 | KELLERGESCHOSS
4 x Wand-035 | KELLERGESCHOSS
2 x Wand-038 | KELLERGESCHOSS
8 x Wand-039 | KELLERGESCHOSS
6 x Wand-040 | KELLERGESCHOSS
3 x Wand-041 | KELLERGESCHOSS
2 x Wand-042 | KELLERGESCHOSS
2 x Wand-043 | KELLERGESCHOSS
3 x Wand-044 | KELLERGESCHOSS
4 x Wand-045 | KELLERGESCHOSS
3 x Wand-046 | KELLERGESCHOSS
3 x Wand-047 | KELLERGESCHOSS
2 x Wand-048 | KELLERGESCHOSS
6 x Wand-049 | KELLERGESCHOSS
6 x Wand-050 | KELLERGESCHOSS
3 x Wand-051 | KELLERGESCHOSS
3 x Wand-052 | KELLERGESCHOSS
3 x Wand-053 | KELLERGESCHOSS
2 x Wand-054 | KELLERGESCHOSS
3 x Wand-055 | KELLERGESCHOSS
2 x Wand-056 | KELLERGESCHOSS
Wand-057 | KELLERGESCHOSS
Wand-058 | KELLERGESCHOSS
3 x Wand-059 | KELLERGESCHOSS
Wand-060 | KELLERGESCHOSS
Wand-061 | KELLERGESCHOSS
Wand-062 | KELLERGESCHOSS
Wand-063 | KELLERGESCHOSS
Wand-064 | KELLERGESCHOSS
Wand-065 | KELLERGESCHOSS
Wand-066 | KELLERGESCHOSS
2 x Wand-067 | KELLERGESCHOSS
Wand-068 | KELLERGESCHOSS
Wand-069 | KELLERGESCHOSS
Wand-070 | KELLERGESCHOSS
Wand-071 | KELLERGESCHOSS
3 x Wand-072 | KELLERGESCHOSS
2 x Wand-073 | KELLERGESCHOSS
Wand-074 | KELLERGESCHOSS
Wand-075 | KELLERGESCHOSS
Wand-076 | KELLERGESCHOSS
Wand-077 | KELLERGESCHOSS
Wand-078 | KELLERGESCHOSS

# IfcWallStandardCase: 43_Gipskarton 330 (2)
Type - PredefinedType: ELEMENTEDWALL
Classification: Elementwand (ARCHICAD Klassifizierung); Material: 43_Gipskarton 0.33 m
Pset_WallCommon - ThermalTransmittance: 0; LoadBearing: yes; IsExternal: yes
AC_Pset_RenovationAndPhasing - Renovation Status: Existing
Name | In
Wand-036 | 2.OBERGESCHOSS
Wand-038 | KELLERGESCHOSS

# IfcWallStandardCase: 43_Gipskarton 75, Wand-039
In: 2.OBERGESCHOSS
Type - PredefinedType: ELEMENTEDWALL
Classification: Elementwand (ARCHICAD Klassifizierung); Material: 43_Gipskarton 0.075 m
Pset_WallCommon - ThermalTransmittance: 0; LoadBearing: yes; IsExternal: yes
AC_Pset_RenovationAndPhasing - Renovation Status: Existing

# IfcWallStandardCase: 56_Metall, Stahl verzinkt 60, Wand-030
In: KELLERGESCHOSS
Type - PredefinedType: ELEMENTEDWALL
Classification: Elementwand (ARCHICAD Klassifizierung); Material: 56_Metall, Stahl verzinkt 0.06 m
Pset_WallCommon - ThermalTransmittance: 0; LoadBearing: yes; IsExternal: yes
AC_Pset_RenovationAndPhasing - Renovation Status: Existing

# IfcWallStandardCase: 59_MW Kalksandstein 134, Wand-039
In: KELLERGESCHOSS
Type - PredefinedType: ELEMENTEDWALL
Classification: Elementwand (ARCHICAD Klassifizierung); Material: 59_MW Kalksandstein 0.134459 m
Pset_WallCommon - ThermalTransmittance: 0; LoadBearing: yes; IsExternal: yes
AC_Pset_RenovationAndPhasing - Renovation Status: Existing

# IfcWallStandardCase: 59_MW Kalksandstein-600 138, Wand-040
In: KELLERGESCHOSS
Type - PredefinedType: ELEMENTEDWALL
Classification: Elementwand (ARCHICAD Klassifizierung); Material: 59_MW Kalksandstein-600 0.138294 m
Pset_WallCommon - ThermalTransmittance: 0; LoadBearing: yes; IsExternal: yes
AC_Pset_RenovationAndPhasing - Renovation Status: Existing

# IfcWallStandardCase: 59_MW Kalksandstein-600 145, Wand-040
In: KELLERGESCHOSS
Type - PredefinedType: ELEMENTEDWALL
Classification: Elementwand (ARCHICAD Klassifizierung); Material: 59_MW Kalksandstein-600 0.145295 m
Pset_WallCommon - ThermalTransmittance: 0; LoadBearing: yes; IsExternal: yes
AC_Pset_RenovationAndPhasing - Renovation Status: Existing

# IfcWallStandardCase: 60_MW Porenbeton 200 (2)
In: KELLERGESCHOSS
Type - PredefinedType: ELEMENTEDWALL
Classification: Elementwand (ARCHICAD Klassifizierung); Material: 60_MW Porenbeton 0.2 m
Pset_WallCommon - ThermalTransmittance: 0; LoadBearing: yes; IsExternal: yes
AC_Pset_RenovationAndPhasing - Renovation Status: Existing
Name
Wand-037
Wand-038

# IfcWindow: Dachfenster Glaskuppel 01 25 (4)
In: 1.OBERGESCHOSS
Type - ParameterTakesPrecedence: no; Sizeable: no
Classification: Dachfenster (ARCHICAD Klassifizierung)
AC_Pset_RenovationAndPhasing - Renovation Status: Existing
Name | OverallHeight (m) = OverallWidth (m)
Dachfenster-001 | 1.48524
3 x Dachfenster-001 | 1.485

# IfcWindow: Dachfenster Glaskuppel 03 25 (3)
In: DACHGESCHOSS
Type - ParameterTakesPrecedence: no; Sizeable: no
Classification: Dachfenster (ARCHICAD Klassifizierung)
AC_Pset_RenovationAndPhasing - Renovation Status: Existing
Name | OverallHeight (m) | OverallWidth (m)
Dachfenster-003 | 0.59345 | 0.456072
Dachfenster-002 | 0.539127 | 0.448854
Dachfenster-002 | 0.58772 | 0.433214

# IfcWindow: Dachfenster Kippflügel 25 (8)
In: DACHGESCHOSS
Type - ParameterTakesPrecedence: no; Sizeable: no
Classification: Dachfenster (ARCHICAD Klassifizierung)
AC_Pset_RenovationAndPhasing - Renovation Status: Existing
Name | OverallHeight (m) | OverallWidth (m)
2 x Dachfenster-002 | 1.3601 | 0.710824
3 x Dachfenster-002 | 1.44252 | 0.711425
3 x Dachfenster-002 | 0.503648 | 0.710654
